VERSION 5.8 ;
BUSBITCHARS "[]" ;
DIVIDERCHAR "/" ;
UNITS
    DATABASE MICRONS 1000 ;
END UNITS

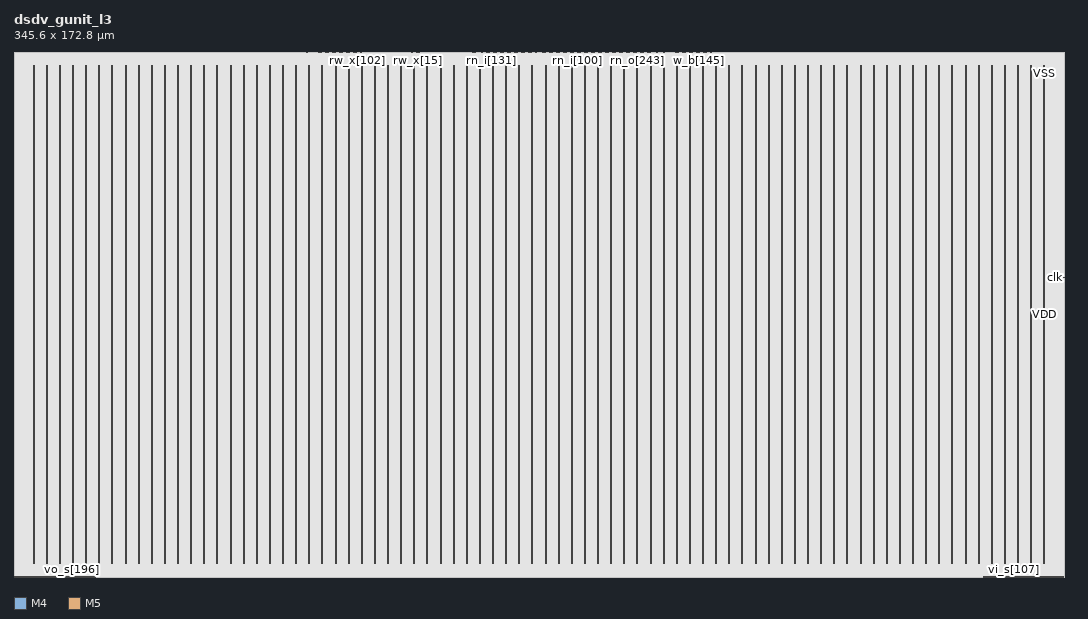
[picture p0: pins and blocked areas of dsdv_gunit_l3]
MACRO dsdv_gunit_l3
  FOREIGN dsdv_gunit_l3 0 0 ;
  CLASS BLOCK ;
  SIZE 345.6 BY 172.8 ;
  PIN clk
    DIRECTION INPUT ;
    USE SIGNAL ;
    PORT
      LAYER M4 ;
        RECT  345.516 98.448 345.6 98.472 ;
    END
  END clk
  PIN fault
    DIRECTION OUTPUT ;
    USE SIGNAL ;
    PORT
      LAYER M5 ;
        RECT  175.92 172.716 175.944 172.8 ;
    END
  END fault
  PIN rn_i[0]
    DIRECTION INPUT ;
    USE SIGNAL ;
    PORT
      LAYER M5 ;
        RECT  176.016 172.716 176.04 172.8 ;
    END
  END rn_i[0]
  PIN rn_i[100]
    DIRECTION INPUT ;
    USE SIGNAL ;
    PORT
      LAYER M5 ;
        RECT  185.616 172.716 185.64 172.8 ;
    END
  END rn_i[100]
  PIN rn_i[101]
    DIRECTION INPUT ;
    USE SIGNAL ;
    PORT
      LAYER M5 ;
        RECT  185.712 172.716 185.736 172.8 ;
    END
  END rn_i[101]
  PIN rn_i[102]
    DIRECTION INPUT ;
    USE SIGNAL ;
    PORT
      LAYER M5 ;
        RECT  185.808 172.716 185.832 172.8 ;
    END
  END rn_i[102]
  PIN rn_i[103]
    DIRECTION INPUT ;
    USE SIGNAL ;
    PORT
      LAYER M5 ;
        RECT  185.904 172.716 185.928 172.8 ;
    END
  END rn_i[103]
  PIN rn_i[104]
    DIRECTION INPUT ;
    USE SIGNAL ;
    PORT
      LAYER M5 ;
        RECT  186 172.716 186.024 172.8 ;
    END
  END rn_i[104]
  PIN rn_i[105]
    DIRECTION INPUT ;
    USE SIGNAL ;
    PORT
      LAYER M5 ;
        RECT  186.096 172.716 186.12 172.8 ;
    END
  END rn_i[105]
  PIN rn_i[106]
    DIRECTION INPUT ;
    USE SIGNAL ;
    PORT
      LAYER M5 ;
        RECT  186.192 172.716 186.216 172.8 ;
    END
  END rn_i[106]
  PIN rn_i[107]
    DIRECTION INPUT ;
    USE SIGNAL ;
    PORT
      LAYER M5 ;
        RECT  186.288 172.716 186.312 172.8 ;
    END
  END rn_i[107]
  PIN rn_i[108]
    DIRECTION INPUT ;
    USE SIGNAL ;
    PORT
      LAYER M5 ;
        RECT  186.384 172.716 186.408 172.8 ;
    END
  END rn_i[108]
  PIN rn_i[109]
    DIRECTION INPUT ;
    USE SIGNAL ;
    PORT
      LAYER M5 ;
        RECT  186.48 172.716 186.504 172.8 ;
    END
  END rn_i[109]
  PIN rn_i[10]
    DIRECTION INPUT ;
    USE SIGNAL ;
    PORT
      LAYER M5 ;
        RECT  176.976 172.716 177 172.8 ;
    END
  END rn_i[10]
  PIN rn_i[110]
    DIRECTION INPUT ;
    USE SIGNAL ;
    PORT
      LAYER M5 ;
        RECT  186.576 172.716 186.6 172.8 ;
    END
  END rn_i[110]
  PIN rn_i[111]
    DIRECTION INPUT ;
    USE SIGNAL ;
    PORT
      LAYER M5 ;
        RECT  186.672 172.716 186.696 172.8 ;
    END
  END rn_i[111]
  PIN rn_i[112]
    DIRECTION INPUT ;
    USE SIGNAL ;
    PORT
      LAYER M5 ;
        RECT  186.768 172.716 186.792 172.8 ;
    END
  END rn_i[112]
  PIN rn_i[113]
    DIRECTION INPUT ;
    USE SIGNAL ;
    PORT
      LAYER M5 ;
        RECT  186.864 172.716 186.888 172.8 ;
    END
  END rn_i[113]
  PIN rn_i[114]
    DIRECTION INPUT ;
    USE SIGNAL ;
    PORT
      LAYER M5 ;
        RECT  186.96 172.716 186.984 172.8 ;
    END
  END rn_i[114]
  PIN rn_i[115]
    DIRECTION INPUT ;
    USE SIGNAL ;
    PORT
      LAYER M5 ;
        RECT  187.056 172.716 187.08 172.8 ;
    END
  END rn_i[115]
  PIN rn_i[116]
    DIRECTION INPUT ;
    USE SIGNAL ;
    PORT
      LAYER M5 ;
        RECT  187.152 172.716 187.176 172.8 ;
    END
  END rn_i[116]
  PIN rn_i[117]
    DIRECTION INPUT ;
    USE SIGNAL ;
    PORT
      LAYER M5 ;
        RECT  187.248 172.716 187.272 172.8 ;
    END
  END rn_i[117]
  PIN rn_i[118]
    DIRECTION INPUT ;
    USE SIGNAL ;
    PORT
      LAYER M5 ;
        RECT  187.344 172.716 187.368 172.8 ;
    END
  END rn_i[118]
  PIN rn_i[119]
    DIRECTION INPUT ;
    USE SIGNAL ;
    PORT
      LAYER M5 ;
        RECT  187.44 172.716 187.464 172.8 ;
    END
  END rn_i[119]
  PIN rn_i[11]
    DIRECTION INPUT ;
    USE SIGNAL ;
    PORT
      LAYER M5 ;
        RECT  177.072 172.716 177.096 172.8 ;
    END
  END rn_i[11]
  PIN rn_i[120]
    DIRECTION INPUT ;
    USE SIGNAL ;
    PORT
      LAYER M5 ;
        RECT  187.536 172.716 187.56 172.8 ;
    END
  END rn_i[120]
  PIN rn_i[121]
    DIRECTION INPUT ;
    USE SIGNAL ;
    PORT
      LAYER M5 ;
        RECT  187.632 172.716 187.656 172.8 ;
    END
  END rn_i[121]
  PIN rn_i[122]
    DIRECTION INPUT ;
    USE SIGNAL ;
    PORT
      LAYER M5 ;
        RECT  187.728 172.716 187.752 172.8 ;
    END
  END rn_i[122]
  PIN rn_i[123]
    DIRECTION INPUT ;
    USE SIGNAL ;
    PORT
      LAYER M5 ;
        RECT  187.824 172.716 187.848 172.8 ;
    END
  END rn_i[123]
  PIN rn_i[124]
    DIRECTION INPUT ;
    USE SIGNAL ;
    PORT
      LAYER M5 ;
        RECT  187.92 172.716 187.944 172.8 ;
    END
  END rn_i[124]
  PIN rn_i[125]
    DIRECTION INPUT ;
    USE SIGNAL ;
    PORT
      LAYER M5 ;
        RECT  188.016 172.716 188.04 172.8 ;
    END
  END rn_i[125]
  PIN rn_i[126]
    DIRECTION INPUT ;
    USE SIGNAL ;
    PORT
      LAYER M5 ;
        RECT  188.112 172.716 188.136 172.8 ;
    END
  END rn_i[126]
  PIN rn_i[127]
    DIRECTION INPUT ;
    USE SIGNAL ;
    PORT
      LAYER M5 ;
        RECT  156.72 172.716 156.744 172.8 ;
    END
  END rn_i[127]
  PIN rn_i[128]
    DIRECTION INPUT ;
    USE SIGNAL ;
    PORT
      LAYER M5 ;
        RECT  156.816 172.716 156.84 172.8 ;
    END
  END rn_i[128]
  PIN rn_i[129]
    DIRECTION INPUT ;
    USE SIGNAL ;
    PORT
      LAYER M5 ;
        RECT  156.912 172.716 156.936 172.8 ;
    END
  END rn_i[129]
  PIN rn_i[12]
    DIRECTION INPUT ;
    USE SIGNAL ;
    PORT
      LAYER M5 ;
        RECT  177.168 172.716 177.192 172.8 ;
    END
  END rn_i[12]
  PIN rn_i[130]
    DIRECTION INPUT ;
    USE SIGNAL ;
    PORT
      LAYER M5 ;
        RECT  157.008 172.716 157.032 172.8 ;
    END
  END rn_i[130]
  PIN rn_i[131]
    DIRECTION INPUT ;
    USE SIGNAL ;
    PORT
      LAYER M5 ;
        RECT  157.104 172.716 157.128 172.8 ;
    END
  END rn_i[131]
  PIN rn_i[132]
    DIRECTION INPUT ;
    USE SIGNAL ;
    PORT
      LAYER M5 ;
        RECT  157.2 172.716 157.224 172.8 ;
    END
  END rn_i[132]
  PIN rn_i[133]
    DIRECTION INPUT ;
    USE SIGNAL ;
    PORT
      LAYER M5 ;
        RECT  157.296 172.716 157.32 172.8 ;
    END
  END rn_i[133]
  PIN rn_i[134]
    DIRECTION INPUT ;
    USE SIGNAL ;
    PORT
      LAYER M5 ;
        RECT  157.392 172.716 157.416 172.8 ;
    END
  END rn_i[134]
  PIN rn_i[135]
    DIRECTION INPUT ;
    USE SIGNAL ;
    PORT
      LAYER M5 ;
        RECT  157.488 172.716 157.512 172.8 ;
    END
  END rn_i[135]
  PIN rn_i[136]
    DIRECTION INPUT ;
    USE SIGNAL ;
    PORT
      LAYER M5 ;
        RECT  157.584 172.716 157.608 172.8 ;
    END
  END rn_i[136]
  PIN rn_i[137]
    DIRECTION INPUT ;
    USE SIGNAL ;
    PORT
      LAYER M5 ;
        RECT  157.68 172.716 157.704 172.8 ;
    END
  END rn_i[137]
  PIN rn_i[138]
    DIRECTION INPUT ;
    USE SIGNAL ;
    PORT
      LAYER M5 ;
        RECT  157.776 172.716 157.8 172.8 ;
    END
  END rn_i[138]
  PIN rn_i[139]
    DIRECTION INPUT ;
    USE SIGNAL ;
    PORT
      LAYER M5 ;
        RECT  157.872 172.716 157.896 172.8 ;
    END
  END rn_i[139]
  PIN rn_i[13]
    DIRECTION INPUT ;
    USE SIGNAL ;
    PORT
      LAYER M5 ;
        RECT  177.264 172.716 177.288 172.8 ;
    END
  END rn_i[13]
  PIN rn_i[140]
    DIRECTION INPUT ;
    USE SIGNAL ;
    PORT
      LAYER M5 ;
        RECT  157.968 172.716 157.992 172.8 ;
    END
  END rn_i[140]
  PIN rn_i[141]
    DIRECTION INPUT ;
    USE SIGNAL ;
    PORT
      LAYER M5 ;
        RECT  158.064 172.716 158.088 172.8 ;
    END
  END rn_i[141]
  PIN rn_i[142]
    DIRECTION INPUT ;
    USE SIGNAL ;
    PORT
      LAYER M5 ;
        RECT  158.16 172.716 158.184 172.8 ;
    END
  END rn_i[142]
  PIN rn_i[143]
    DIRECTION INPUT ;
    USE SIGNAL ;
    PORT
      LAYER M5 ;
        RECT  158.256 172.716 158.28 172.8 ;
    END
  END rn_i[143]
  PIN rn_i[144]
    DIRECTION INPUT ;
    USE SIGNAL ;
    PORT
      LAYER M5 ;
        RECT  158.352 172.716 158.376 172.8 ;
    END
  END rn_i[144]
  PIN rn_i[145]
    DIRECTION INPUT ;
    USE SIGNAL ;
    PORT
      LAYER M5 ;
        RECT  158.448 172.716 158.472 172.8 ;
    END
  END rn_i[145]
  PIN rn_i[146]
    DIRECTION INPUT ;
    USE SIGNAL ;
    PORT
      LAYER M5 ;
        RECT  158.544 172.716 158.568 172.8 ;
    END
  END rn_i[146]
  PIN rn_i[147]
    DIRECTION INPUT ;
    USE SIGNAL ;
    PORT
      LAYER M5 ;
        RECT  158.64 172.716 158.664 172.8 ;
    END
  END rn_i[147]
  PIN rn_i[148]
    DIRECTION INPUT ;
    USE SIGNAL ;
    PORT
      LAYER M5 ;
        RECT  158.736 172.716 158.76 172.8 ;
    END
  END rn_i[148]
  PIN rn_i[149]
    DIRECTION INPUT ;
    USE SIGNAL ;
    PORT
      LAYER M5 ;
        RECT  158.832 172.716 158.856 172.8 ;
    END
  END rn_i[149]
  PIN rn_i[14]
    DIRECTION INPUT ;
    USE SIGNAL ;
    PORT
      LAYER M5 ;
        RECT  177.36 172.716 177.384 172.8 ;
    END
  END rn_i[14]
  PIN rn_i[150]
    DIRECTION INPUT ;
    USE SIGNAL ;
    PORT
      LAYER M5 ;
        RECT  158.928 172.716 158.952 172.8 ;
    END
  END rn_i[150]
  PIN rn_i[151]
    DIRECTION INPUT ;
    USE SIGNAL ;
    PORT
      LAYER M5 ;
        RECT  159.024 172.716 159.048 172.8 ;
    END
  END rn_i[151]
  PIN rn_i[152]
    DIRECTION INPUT ;
    USE SIGNAL ;
    PORT
      LAYER M5 ;
        RECT  159.12 172.716 159.144 172.8 ;
    END
  END rn_i[152]
  PIN rn_i[153]
    DIRECTION INPUT ;
    USE SIGNAL ;
    PORT
      LAYER M5 ;
        RECT  159.216 172.716 159.24 172.8 ;
    END
  END rn_i[153]
  PIN rn_i[154]
    DIRECTION INPUT ;
    USE SIGNAL ;
    PORT
      LAYER M5 ;
        RECT  159.312 172.716 159.336 172.8 ;
    END
  END rn_i[154]
  PIN rn_i[155]
    DIRECTION INPUT ;
    USE SIGNAL ;
    PORT
      LAYER M5 ;
        RECT  159.408 172.716 159.432 172.8 ;
    END
  END rn_i[155]
  PIN rn_i[156]
    DIRECTION INPUT ;
    USE SIGNAL ;
    PORT
      LAYER M5 ;
        RECT  159.504 172.716 159.528 172.8 ;
    END
  END rn_i[156]
  PIN rn_i[157]
    DIRECTION INPUT ;
    USE SIGNAL ;
    PORT
      LAYER M5 ;
        RECT  159.6 172.716 159.624 172.8 ;
    END
  END rn_i[157]
  PIN rn_i[158]
    DIRECTION INPUT ;
    USE SIGNAL ;
    PORT
      LAYER M5 ;
        RECT  159.696 172.716 159.72 172.8 ;
    END
  END rn_i[158]
  PIN rn_i[159]
    DIRECTION INPUT ;
    USE SIGNAL ;
    PORT
      LAYER M5 ;
        RECT  188.208 172.716 188.232 172.8 ;
    END
  END rn_i[159]
  PIN rn_i[15]
    DIRECTION INPUT ;
    USE SIGNAL ;
    PORT
      LAYER M5 ;
        RECT  177.456 172.716 177.48 172.8 ;
    END
  END rn_i[15]
  PIN rn_i[160]
    DIRECTION INPUT ;
    USE SIGNAL ;
    PORT
      LAYER M5 ;
        RECT  188.304 172.716 188.328 172.8 ;
    END
  END rn_i[160]
  PIN rn_i[161]
    DIRECTION INPUT ;
    USE SIGNAL ;
    PORT
      LAYER M5 ;
        RECT  188.4 172.716 188.424 172.8 ;
    END
  END rn_i[161]
  PIN rn_i[162]
    DIRECTION INPUT ;
    USE SIGNAL ;
    PORT
      LAYER M5 ;
        RECT  188.496 172.716 188.52 172.8 ;
    END
  END rn_i[162]
  PIN rn_i[163]
    DIRECTION INPUT ;
    USE SIGNAL ;
    PORT
      LAYER M5 ;
        RECT  188.592 172.716 188.616 172.8 ;
    END
  END rn_i[163]
  PIN rn_i[164]
    DIRECTION INPUT ;
    USE SIGNAL ;
    PORT
      LAYER M5 ;
        RECT  188.688 172.716 188.712 172.8 ;
    END
  END rn_i[164]
  PIN rn_i[165]
    DIRECTION INPUT ;
    USE SIGNAL ;
    PORT
      LAYER M5 ;
        RECT  188.784 172.716 188.808 172.8 ;
    END
  END rn_i[165]
  PIN rn_i[166]
    DIRECTION INPUT ;
    USE SIGNAL ;
    PORT
      LAYER M5 ;
        RECT  188.88 172.716 188.904 172.8 ;
    END
  END rn_i[166]
  PIN rn_i[167]
    DIRECTION INPUT ;
    USE SIGNAL ;
    PORT
      LAYER M5 ;
        RECT  188.976 172.716 189 172.8 ;
    END
  END rn_i[167]
  PIN rn_i[168]
    DIRECTION INPUT ;
    USE SIGNAL ;
    PORT
      LAYER M5 ;
        RECT  189.072 172.716 189.096 172.8 ;
    END
  END rn_i[168]
  PIN rn_i[169]
    DIRECTION INPUT ;
    USE SIGNAL ;
    PORT
      LAYER M5 ;
        RECT  189.168 172.716 189.192 172.8 ;
    END
  END rn_i[169]
  PIN rn_i[16]
    DIRECTION INPUT ;
    USE SIGNAL ;
    PORT
      LAYER M5 ;
        RECT  177.552 172.716 177.576 172.8 ;
    END
  END rn_i[16]
  PIN rn_i[170]
    DIRECTION INPUT ;
    USE SIGNAL ;
    PORT
      LAYER M5 ;
        RECT  189.264 172.716 189.288 172.8 ;
    END
  END rn_i[170]
  PIN rn_i[171]
    DIRECTION INPUT ;
    USE SIGNAL ;
    PORT
      LAYER M5 ;
        RECT  189.36 172.716 189.384 172.8 ;
    END
  END rn_i[171]
  PIN rn_i[172]
    DIRECTION INPUT ;
    USE SIGNAL ;
    PORT
      LAYER M5 ;
        RECT  189.456 172.716 189.48 172.8 ;
    END
  END rn_i[172]
  PIN rn_i[173]
    DIRECTION INPUT ;
    USE SIGNAL ;
    PORT
      LAYER M5 ;
        RECT  189.552 172.716 189.576 172.8 ;
    END
  END rn_i[173]
  PIN rn_i[174]
    DIRECTION INPUT ;
    USE SIGNAL ;
    PORT
      LAYER M5 ;
        RECT  189.648 172.716 189.672 172.8 ;
    END
  END rn_i[174]
  PIN rn_i[175]
    DIRECTION INPUT ;
    USE SIGNAL ;
    PORT
      LAYER M5 ;
        RECT  189.744 172.716 189.768 172.8 ;
    END
  END rn_i[175]
  PIN rn_i[176]
    DIRECTION INPUT ;
    USE SIGNAL ;
    PORT
      LAYER M5 ;
        RECT  189.84 172.716 189.864 172.8 ;
    END
  END rn_i[176]
  PIN rn_i[177]
    DIRECTION INPUT ;
    USE SIGNAL ;
    PORT
      LAYER M5 ;
        RECT  189.936 172.716 189.96 172.8 ;
    END
  END rn_i[177]
  PIN rn_i[178]
    DIRECTION INPUT ;
    USE SIGNAL ;
    PORT
      LAYER M5 ;
        RECT  190.032 172.716 190.056 172.8 ;
    END
  END rn_i[178]
  PIN rn_i[179]
    DIRECTION INPUT ;
    USE SIGNAL ;
    PORT
      LAYER M5 ;
        RECT  190.128 172.716 190.152 172.8 ;
    END
  END rn_i[179]
  PIN rn_i[17]
    DIRECTION INPUT ;
    USE SIGNAL ;
    PORT
      LAYER M5 ;
        RECT  177.648 172.716 177.672 172.8 ;
    END
  END rn_i[17]
  PIN rn_i[180]
    DIRECTION INPUT ;
    USE SIGNAL ;
    PORT
      LAYER M5 ;
        RECT  190.224 172.716 190.248 172.8 ;
    END
  END rn_i[180]
  PIN rn_i[181]
    DIRECTION INPUT ;
    USE SIGNAL ;
    PORT
      LAYER M5 ;
        RECT  190.32 172.716 190.344 172.8 ;
    END
  END rn_i[181]
  PIN rn_i[182]
    DIRECTION INPUT ;
    USE SIGNAL ;
    PORT
      LAYER M5 ;
        RECT  190.416 172.716 190.44 172.8 ;
    END
  END rn_i[182]
  PIN rn_i[183]
    DIRECTION INPUT ;
    USE SIGNAL ;
    PORT
      LAYER M5 ;
        RECT  190.512 172.716 190.536 172.8 ;
    END
  END rn_i[183]
  PIN rn_i[184]
    DIRECTION INPUT ;
    USE SIGNAL ;
    PORT
      LAYER M5 ;
        RECT  190.608 172.716 190.632 172.8 ;
    END
  END rn_i[184]
  PIN rn_i[185]
    DIRECTION INPUT ;
    USE SIGNAL ;
    PORT
      LAYER M5 ;
        RECT  190.704 172.716 190.728 172.8 ;
    END
  END rn_i[185]
  PIN rn_i[186]
    DIRECTION INPUT ;
    USE SIGNAL ;
    PORT
      LAYER M5 ;
        RECT  190.8 172.716 190.824 172.8 ;
    END
  END rn_i[186]
  PIN rn_i[187]
    DIRECTION INPUT ;
    USE SIGNAL ;
    PORT
      LAYER M5 ;
        RECT  190.896 172.716 190.92 172.8 ;
    END
  END rn_i[187]
  PIN rn_i[188]
    DIRECTION INPUT ;
    USE SIGNAL ;
    PORT
      LAYER M5 ;
        RECT  190.992 172.716 191.016 172.8 ;
    END
  END rn_i[188]
  PIN rn_i[189]
    DIRECTION INPUT ;
    USE SIGNAL ;
    PORT
      LAYER M5 ;
        RECT  191.088 172.716 191.112 172.8 ;
    END
  END rn_i[189]
  PIN rn_i[18]
    DIRECTION INPUT ;
    USE SIGNAL ;
    PORT
      LAYER M5 ;
        RECT  177.744 172.716 177.768 172.8 ;
    END
  END rn_i[18]
  PIN rn_i[190]
    DIRECTION INPUT ;
    USE SIGNAL ;
    PORT
      LAYER M5 ;
        RECT  191.184 172.716 191.208 172.8 ;
    END
  END rn_i[190]
  PIN rn_i[191]
    DIRECTION INPUT ;
    USE SIGNAL ;
    PORT
      LAYER M5 ;
        RECT  178.992 172.716 179.016 172.8 ;
    END
  END rn_i[191]
  PIN rn_i[192]
    DIRECTION INPUT ;
    USE SIGNAL ;
    PORT
      LAYER M5 ;
        RECT  179.088 172.716 179.112 172.8 ;
    END
  END rn_i[192]
  PIN rn_i[193]
    DIRECTION INPUT ;
    USE SIGNAL ;
    PORT
      LAYER M5 ;
        RECT  179.184 172.716 179.208 172.8 ;
    END
  END rn_i[193]
  PIN rn_i[194]
    DIRECTION INPUT ;
    USE SIGNAL ;
    PORT
      LAYER M5 ;
        RECT  179.28 172.716 179.304 172.8 ;
    END
  END rn_i[194]
  PIN rn_i[195]
    DIRECTION INPUT ;
    USE SIGNAL ;
    PORT
      LAYER M5 ;
        RECT  179.376 172.716 179.4 172.8 ;
    END
  END rn_i[195]
  PIN rn_i[196]
    DIRECTION INPUT ;
    USE SIGNAL ;
    PORT
      LAYER M5 ;
        RECT  179.472 172.716 179.496 172.8 ;
    END
  END rn_i[196]
  PIN rn_i[197]
    DIRECTION INPUT ;
    USE SIGNAL ;
    PORT
      LAYER M5 ;
        RECT  179.568 172.716 179.592 172.8 ;
    END
  END rn_i[197]
  PIN rn_i[198]
    DIRECTION INPUT ;
    USE SIGNAL ;
    PORT
      LAYER M5 ;
        RECT  179.664 172.716 179.688 172.8 ;
    END
  END rn_i[198]
  PIN rn_i[199]
    DIRECTION INPUT ;
    USE SIGNAL ;
    PORT
      LAYER M5 ;
        RECT  179.76 172.716 179.784 172.8 ;
    END
  END rn_i[199]
  PIN rn_i[19]
    DIRECTION INPUT ;
    USE SIGNAL ;
    PORT
      LAYER M5 ;
        RECT  177.84 172.716 177.864 172.8 ;
    END
  END rn_i[19]
  PIN rn_i[1]
    DIRECTION INPUT ;
    USE SIGNAL ;
    PORT
      LAYER M5 ;
        RECT  176.112 172.716 176.136 172.8 ;
    END
  END rn_i[1]
  PIN rn_i[200]
    DIRECTION INPUT ;
    USE SIGNAL ;
    PORT
      LAYER M5 ;
        RECT  179.856 172.716 179.88 172.8 ;
    END
  END rn_i[200]
  PIN rn_i[201]
    DIRECTION INPUT ;
    USE SIGNAL ;
    PORT
      LAYER M5 ;
        RECT  179.952 172.716 179.976 172.8 ;
    END
  END rn_i[201]
  PIN rn_i[202]
    DIRECTION INPUT ;
    USE SIGNAL ;
    PORT
      LAYER M5 ;
        RECT  180.048 172.716 180.072 172.8 ;
    END
  END rn_i[202]
  PIN rn_i[203]
    DIRECTION INPUT ;
    USE SIGNAL ;
    PORT
      LAYER M5 ;
        RECT  180.144 172.716 180.168 172.8 ;
    END
  END rn_i[203]
  PIN rn_i[204]
    DIRECTION INPUT ;
    USE SIGNAL ;
    PORT
      LAYER M5 ;
        RECT  180.24 172.716 180.264 172.8 ;
    END
  END rn_i[204]
  PIN rn_i[205]
    DIRECTION INPUT ;
    USE SIGNAL ;
    PORT
      LAYER M5 ;
        RECT  180.336 172.716 180.36 172.8 ;
    END
  END rn_i[205]
  PIN rn_i[206]
    DIRECTION INPUT ;
    USE SIGNAL ;
    PORT
      LAYER M5 ;
        RECT  180.432 172.716 180.456 172.8 ;
    END
  END rn_i[206]
  PIN rn_i[207]
    DIRECTION INPUT ;
    USE SIGNAL ;
    PORT
      LAYER M5 ;
        RECT  180.528 172.716 180.552 172.8 ;
    END
  END rn_i[207]
  PIN rn_i[208]
    DIRECTION INPUT ;
    USE SIGNAL ;
    PORT
      LAYER M5 ;
        RECT  180.624 172.716 180.648 172.8 ;
    END
  END rn_i[208]
  PIN rn_i[209]
    DIRECTION INPUT ;
    USE SIGNAL ;
    PORT
      LAYER M5 ;
        RECT  180.72 172.716 180.744 172.8 ;
    END
  END rn_i[209]
  PIN rn_i[20]
    DIRECTION INPUT ;
    USE SIGNAL ;
    PORT
      LAYER M5 ;
        RECT  177.936 172.716 177.96 172.8 ;
    END
  END rn_i[20]
  PIN rn_i[210]
    DIRECTION INPUT ;
    USE SIGNAL ;
    PORT
      LAYER M5 ;
        RECT  180.816 172.716 180.84 172.8 ;
    END
  END rn_i[210]
  PIN rn_i[211]
    DIRECTION INPUT ;
    USE SIGNAL ;
    PORT
      LAYER M5 ;
        RECT  180.912 172.716 180.936 172.8 ;
    END
  END rn_i[211]
  PIN rn_i[212]
    DIRECTION INPUT ;
    USE SIGNAL ;
    PORT
      LAYER M5 ;
        RECT  181.008 172.716 181.032 172.8 ;
    END
  END rn_i[212]
  PIN rn_i[213]
    DIRECTION INPUT ;
    USE SIGNAL ;
    PORT
      LAYER M5 ;
        RECT  181.104 172.716 181.128 172.8 ;
    END
  END rn_i[213]
  PIN rn_i[214]
    DIRECTION INPUT ;
    USE SIGNAL ;
    PORT
      LAYER M5 ;
        RECT  181.2 172.716 181.224 172.8 ;
    END
  END rn_i[214]
  PIN rn_i[215]
    DIRECTION INPUT ;
    USE SIGNAL ;
    PORT
      LAYER M5 ;
        RECT  181.296 172.716 181.32 172.8 ;
    END
  END rn_i[215]
  PIN rn_i[216]
    DIRECTION INPUT ;
    USE SIGNAL ;
    PORT
      LAYER M5 ;
        RECT  181.392 172.716 181.416 172.8 ;
    END
  END rn_i[216]
  PIN rn_i[217]
    DIRECTION INPUT ;
    USE SIGNAL ;
    PORT
      LAYER M5 ;
        RECT  181.488 172.716 181.512 172.8 ;
    END
  END rn_i[217]
  PIN rn_i[218]
    DIRECTION INPUT ;
    USE SIGNAL ;
    PORT
      LAYER M5 ;
        RECT  181.584 172.716 181.608 172.8 ;
    END
  END rn_i[218]
  PIN rn_i[219]
    DIRECTION INPUT ;
    USE SIGNAL ;
    PORT
      LAYER M5 ;
        RECT  181.68 172.716 181.704 172.8 ;
    END
  END rn_i[219]
  PIN rn_i[21]
    DIRECTION INPUT ;
    USE SIGNAL ;
    PORT
      LAYER M5 ;
        RECT  178.032 172.716 178.056 172.8 ;
    END
  END rn_i[21]
  PIN rn_i[220]
    DIRECTION INPUT ;
    USE SIGNAL ;
    PORT
      LAYER M5 ;
        RECT  181.776 172.716 181.8 172.8 ;
    END
  END rn_i[220]
  PIN rn_i[221]
    DIRECTION INPUT ;
    USE SIGNAL ;
    PORT
      LAYER M5 ;
        RECT  181.872 172.716 181.896 172.8 ;
    END
  END rn_i[221]
  PIN rn_i[222]
    DIRECTION INPUT ;
    USE SIGNAL ;
    PORT
      LAYER M5 ;
        RECT  181.968 172.716 181.992 172.8 ;
    END
  END rn_i[222]
  PIN rn_i[223]
    DIRECTION INPUT ;
    USE SIGNAL ;
    PORT
      LAYER M5 ;
        RECT  201.264 172.716 201.288 172.8 ;
    END
  END rn_i[223]
  PIN rn_i[224]
    DIRECTION INPUT ;
    USE SIGNAL ;
    PORT
      LAYER M5 ;
        RECT  201.36 172.716 201.384 172.8 ;
    END
  END rn_i[224]
  PIN rn_i[225]
    DIRECTION INPUT ;
    USE SIGNAL ;
    PORT
      LAYER M5 ;
        RECT  201.456 172.716 201.48 172.8 ;
    END
  END rn_i[225]
  PIN rn_i[226]
    DIRECTION INPUT ;
    USE SIGNAL ;
    PORT
      LAYER M5 ;
        RECT  201.552 172.716 201.576 172.8 ;
    END
  END rn_i[226]
  PIN rn_i[227]
    DIRECTION INPUT ;
    USE SIGNAL ;
    PORT
      LAYER M5 ;
        RECT  201.648 172.716 201.672 172.8 ;
    END
  END rn_i[227]
  PIN rn_i[228]
    DIRECTION INPUT ;
    USE SIGNAL ;
    PORT
      LAYER M5 ;
        RECT  201.744 172.716 201.768 172.8 ;
    END
  END rn_i[228]
  PIN rn_i[229]
    DIRECTION INPUT ;
    USE SIGNAL ;
    PORT
      LAYER M5 ;
        RECT  201.84 172.716 201.864 172.8 ;
    END
  END rn_i[229]
  PIN rn_i[22]
    DIRECTION INPUT ;
    USE SIGNAL ;
    PORT
      LAYER M5 ;
        RECT  178.128 172.716 178.152 172.8 ;
    END
  END rn_i[22]
  PIN rn_i[230]
    DIRECTION INPUT ;
    USE SIGNAL ;
    PORT
      LAYER M5 ;
        RECT  201.936 172.716 201.96 172.8 ;
    END
  END rn_i[230]
  PIN rn_i[231]
    DIRECTION INPUT ;
    USE SIGNAL ;
    PORT
      LAYER M5 ;
        RECT  202.032 172.716 202.056 172.8 ;
    END
  END rn_i[231]
  PIN rn_i[232]
    DIRECTION INPUT ;
    USE SIGNAL ;
    PORT
      LAYER M5 ;
        RECT  202.128 172.716 202.152 172.8 ;
    END
  END rn_i[232]
  PIN rn_i[233]
    DIRECTION INPUT ;
    USE SIGNAL ;
    PORT
      LAYER M5 ;
        RECT  202.224 172.716 202.248 172.8 ;
    END
  END rn_i[233]
  PIN rn_i[234]
    DIRECTION INPUT ;
    USE SIGNAL ;
    PORT
      LAYER M5 ;
        RECT  202.32 172.716 202.344 172.8 ;
    END
  END rn_i[234]
  PIN rn_i[235]
    DIRECTION INPUT ;
    USE SIGNAL ;
    PORT
      LAYER M5 ;
        RECT  202.416 172.716 202.44 172.8 ;
    END
  END rn_i[235]
  PIN rn_i[236]
    DIRECTION INPUT ;
    USE SIGNAL ;
    PORT
      LAYER M5 ;
        RECT  202.512 172.716 202.536 172.8 ;
    END
  END rn_i[236]
  PIN rn_i[237]
    DIRECTION INPUT ;
    USE SIGNAL ;
    PORT
      LAYER M5 ;
        RECT  202.608 172.716 202.632 172.8 ;
    END
  END rn_i[237]
  PIN rn_i[238]
    DIRECTION INPUT ;
    USE SIGNAL ;
    PORT
      LAYER M5 ;
        RECT  202.704 172.716 202.728 172.8 ;
    END
  END rn_i[238]
  PIN rn_i[239]
    DIRECTION INPUT ;
    USE SIGNAL ;
    PORT
      LAYER M5 ;
        RECT  202.8 172.716 202.824 172.8 ;
    END
  END rn_i[239]
  PIN rn_i[23]
    DIRECTION INPUT ;
    USE SIGNAL ;
    PORT
      LAYER M5 ;
        RECT  178.224 172.716 178.248 172.8 ;
    END
  END rn_i[23]
  PIN rn_i[240]
    DIRECTION INPUT ;
    USE SIGNAL ;
    PORT
      LAYER M5 ;
        RECT  202.896 172.716 202.92 172.8 ;
    END
  END rn_i[240]
  PIN rn_i[241]
    DIRECTION INPUT ;
    USE SIGNAL ;
    PORT
      LAYER M5 ;
        RECT  202.992 172.716 203.016 172.8 ;
    END
  END rn_i[241]
  PIN rn_i[242]
    DIRECTION INPUT ;
    USE SIGNAL ;
    PORT
      LAYER M5 ;
        RECT  203.088 172.716 203.112 172.8 ;
    END
  END rn_i[242]
  PIN rn_i[243]
    DIRECTION INPUT ;
    USE SIGNAL ;
    PORT
      LAYER M5 ;
        RECT  203.184 172.716 203.208 172.8 ;
    END
  END rn_i[243]
  PIN rn_i[244]
    DIRECTION INPUT ;
    USE SIGNAL ;
    PORT
      LAYER M5 ;
        RECT  203.28 172.716 203.304 172.8 ;
    END
  END rn_i[244]
  PIN rn_i[245]
    DIRECTION INPUT ;
    USE SIGNAL ;
    PORT
      LAYER M5 ;
        RECT  203.376 172.716 203.4 172.8 ;
    END
  END rn_i[245]
  PIN rn_i[246]
    DIRECTION INPUT ;
    USE SIGNAL ;
    PORT
      LAYER M5 ;
        RECT  203.472 172.716 203.496 172.8 ;
    END
  END rn_i[246]
  PIN rn_i[247]
    DIRECTION INPUT ;
    USE SIGNAL ;
    PORT
      LAYER M5 ;
        RECT  203.568 172.716 203.592 172.8 ;
    END
  END rn_i[247]
  PIN rn_i[248]
    DIRECTION INPUT ;
    USE SIGNAL ;
    PORT
      LAYER M5 ;
        RECT  203.664 172.716 203.688 172.8 ;
    END
  END rn_i[248]
  PIN rn_i[249]
    DIRECTION INPUT ;
    USE SIGNAL ;
    PORT
      LAYER M5 ;
        RECT  203.76 172.716 203.784 172.8 ;
    END
  END rn_i[249]
  PIN rn_i[24]
    DIRECTION INPUT ;
    USE SIGNAL ;
    PORT
      LAYER M5 ;
        RECT  178.32 172.716 178.344 172.8 ;
    END
  END rn_i[24]
  PIN rn_i[250]
    DIRECTION INPUT ;
    USE SIGNAL ;
    PORT
      LAYER M5 ;
        RECT  203.856 172.716 203.88 172.8 ;
    END
  END rn_i[250]
  PIN rn_i[251]
    DIRECTION INPUT ;
    USE SIGNAL ;
    PORT
      LAYER M5 ;
        RECT  203.952 172.716 203.976 172.8 ;
    END
  END rn_i[251]
  PIN rn_i[252]
    DIRECTION INPUT ;
    USE SIGNAL ;
    PORT
      LAYER M5 ;
        RECT  204.048 172.716 204.072 172.8 ;
    END
  END rn_i[252]
  PIN rn_i[253]
    DIRECTION INPUT ;
    USE SIGNAL ;
    PORT
      LAYER M5 ;
        RECT  204.144 172.716 204.168 172.8 ;
    END
  END rn_i[253]
  PIN rn_i[254]
    DIRECTION INPUT ;
    USE SIGNAL ;
    PORT
      LAYER M5 ;
        RECT  204.24 172.716 204.264 172.8 ;
    END
  END rn_i[254]
  PIN rn_i[255]
    DIRECTION INPUT ;
    USE SIGNAL ;
    PORT
      LAYER M5 ;
        RECT  165.936 172.716 165.96 172.8 ;
    END
  END rn_i[255]
  PIN rn_i[256]
    DIRECTION INPUT ;
    USE SIGNAL ;
    PORT
      LAYER M5 ;
        RECT  166.032 172.716 166.056 172.8 ;
    END
  END rn_i[256]
  PIN rn_i[257]
    DIRECTION INPUT ;
    USE SIGNAL ;
    PORT
      LAYER M5 ;
        RECT  166.128 172.716 166.152 172.8 ;
    END
  END rn_i[257]
  PIN rn_i[258]
    DIRECTION INPUT ;
    USE SIGNAL ;
    PORT
      LAYER M5 ;
        RECT  166.224 172.716 166.248 172.8 ;
    END
  END rn_i[258]
  PIN rn_i[259]
    DIRECTION INPUT ;
    USE SIGNAL ;
    PORT
      LAYER M5 ;
        RECT  166.32 172.716 166.344 172.8 ;
    END
  END rn_i[259]
  PIN rn_i[25]
    DIRECTION INPUT ;
    USE SIGNAL ;
    PORT
      LAYER M5 ;
        RECT  178.416 172.716 178.44 172.8 ;
    END
  END rn_i[25]
  PIN rn_i[260]
    DIRECTION INPUT ;
    USE SIGNAL ;
    PORT
      LAYER M5 ;
        RECT  166.416 172.716 166.44 172.8 ;
    END
  END rn_i[260]
  PIN rn_i[261]
    DIRECTION INPUT ;
    USE SIGNAL ;
    PORT
      LAYER M5 ;
        RECT  166.512 172.716 166.536 172.8 ;
    END
  END rn_i[261]
  PIN rn_i[262]
    DIRECTION INPUT ;
    USE SIGNAL ;
    PORT
      LAYER M5 ;
        RECT  166.608 172.716 166.632 172.8 ;
    END
  END rn_i[262]
  PIN rn_i[263]
    DIRECTION INPUT ;
    USE SIGNAL ;
    PORT
      LAYER M5 ;
        RECT  166.704 172.716 166.728 172.8 ;
    END
  END rn_i[263]
  PIN rn_i[264]
    DIRECTION INPUT ;
    USE SIGNAL ;
    PORT
      LAYER M5 ;
        RECT  166.8 172.716 166.824 172.8 ;
    END
  END rn_i[264]
  PIN rn_i[265]
    DIRECTION INPUT ;
    USE SIGNAL ;
    PORT
      LAYER M5 ;
        RECT  166.896 172.716 166.92 172.8 ;
    END
  END rn_i[265]
  PIN rn_i[266]
    DIRECTION INPUT ;
    USE SIGNAL ;
    PORT
      LAYER M5 ;
        RECT  166.992 172.716 167.016 172.8 ;
    END
  END rn_i[266]
  PIN rn_i[267]
    DIRECTION INPUT ;
    USE SIGNAL ;
    PORT
      LAYER M5 ;
        RECT  167.088 172.716 167.112 172.8 ;
    END
  END rn_i[267]
  PIN rn_i[268]
    DIRECTION INPUT ;
    USE SIGNAL ;
    PORT
      LAYER M5 ;
        RECT  167.184 172.716 167.208 172.8 ;
    END
  END rn_i[268]
  PIN rn_i[269]
    DIRECTION INPUT ;
    USE SIGNAL ;
    PORT
      LAYER M5 ;
        RECT  167.28 172.716 167.304 172.8 ;
    END
  END rn_i[269]
  PIN rn_i[26]
    DIRECTION INPUT ;
    USE SIGNAL ;
    PORT
      LAYER M5 ;
        RECT  178.512 172.716 178.536 172.8 ;
    END
  END rn_i[26]
  PIN rn_i[270]
    DIRECTION INPUT ;
    USE SIGNAL ;
    PORT
      LAYER M5 ;
        RECT  167.376 172.716 167.4 172.8 ;
    END
  END rn_i[270]
  PIN rn_i[271]
    DIRECTION INPUT ;
    USE SIGNAL ;
    PORT
      LAYER M5 ;
        RECT  167.472 172.716 167.496 172.8 ;
    END
  END rn_i[271]
  PIN rn_i[272]
    DIRECTION INPUT ;
    USE SIGNAL ;
    PORT
      LAYER M5 ;
        RECT  167.568 172.716 167.592 172.8 ;
    END
  END rn_i[272]
  PIN rn_i[273]
    DIRECTION INPUT ;
    USE SIGNAL ;
    PORT
      LAYER M5 ;
        RECT  167.664 172.716 167.688 172.8 ;
    END
  END rn_i[273]
  PIN rn_i[274]
    DIRECTION INPUT ;
    USE SIGNAL ;
    PORT
      LAYER M5 ;
        RECT  167.76 172.716 167.784 172.8 ;
    END
  END rn_i[274]
  PIN rn_i[275]
    DIRECTION INPUT ;
    USE SIGNAL ;
    PORT
      LAYER M5 ;
        RECT  167.856 172.716 167.88 172.8 ;
    END
  END rn_i[275]
  PIN rn_i[27]
    DIRECTION INPUT ;
    USE SIGNAL ;
    PORT
      LAYER M5 ;
        RECT  178.608 172.716 178.632 172.8 ;
    END
  END rn_i[27]
  PIN rn_i[28]
    DIRECTION INPUT ;
    USE SIGNAL ;
    PORT
      LAYER M5 ;
        RECT  178.704 172.716 178.728 172.8 ;
    END
  END rn_i[28]
  PIN rn_i[29]
    DIRECTION INPUT ;
    USE SIGNAL ;
    PORT
      LAYER M5 ;
        RECT  178.8 172.716 178.824 172.8 ;
    END
  END rn_i[29]
  PIN rn_i[2]
    DIRECTION INPUT ;
    USE SIGNAL ;
    PORT
      LAYER M5 ;
        RECT  176.208 172.716 176.232 172.8 ;
    END
  END rn_i[2]
  PIN rn_i[30]
    DIRECTION INPUT ;
    USE SIGNAL ;
    PORT
      LAYER M5 ;
        RECT  178.896 172.716 178.92 172.8 ;
    END
  END rn_i[30]
  PIN rn_i[31]
    DIRECTION INPUT ;
    USE SIGNAL ;
    PORT
      LAYER M5 ;
        RECT  172.848 172.716 172.872 172.8 ;
    END
  END rn_i[31]
  PIN rn_i[32]
    DIRECTION INPUT ;
    USE SIGNAL ;
    PORT
      LAYER M5 ;
        RECT  172.944 172.716 172.968 172.8 ;
    END
  END rn_i[32]
  PIN rn_i[33]
    DIRECTION INPUT ;
    USE SIGNAL ;
    PORT
      LAYER M5 ;
        RECT  173.04 172.716 173.064 172.8 ;
    END
  END rn_i[33]
  PIN rn_i[34]
    DIRECTION INPUT ;
    USE SIGNAL ;
    PORT
      LAYER M5 ;
        RECT  173.136 172.716 173.16 172.8 ;
    END
  END rn_i[34]
  PIN rn_i[35]
    DIRECTION INPUT ;
    USE SIGNAL ;
    PORT
      LAYER M5 ;
        RECT  173.232 172.716 173.256 172.8 ;
    END
  END rn_i[35]
  PIN rn_i[36]
    DIRECTION INPUT ;
    USE SIGNAL ;
    PORT
      LAYER M5 ;
        RECT  173.328 172.716 173.352 172.8 ;
    END
  END rn_i[36]
  PIN rn_i[37]
    DIRECTION INPUT ;
    USE SIGNAL ;
    PORT
      LAYER M5 ;
        RECT  173.424 172.716 173.448 172.8 ;
    END
  END rn_i[37]
  PIN rn_i[38]
    DIRECTION INPUT ;
    USE SIGNAL ;
    PORT
      LAYER M5 ;
        RECT  173.52 172.716 173.544 172.8 ;
    END
  END rn_i[38]
  PIN rn_i[39]
    DIRECTION INPUT ;
    USE SIGNAL ;
    PORT
      LAYER M5 ;
        RECT  173.616 172.716 173.64 172.8 ;
    END
  END rn_i[39]
  PIN rn_i[3]
    DIRECTION INPUT ;
    USE SIGNAL ;
    PORT
      LAYER M5 ;
        RECT  176.304 172.716 176.328 172.8 ;
    END
  END rn_i[3]
  PIN rn_i[40]
    DIRECTION INPUT ;
    USE SIGNAL ;
    PORT
      LAYER M5 ;
        RECT  173.712 172.716 173.736 172.8 ;
    END
  END rn_i[40]
  PIN rn_i[41]
    DIRECTION INPUT ;
    USE SIGNAL ;
    PORT
      LAYER M5 ;
        RECT  173.808 172.716 173.832 172.8 ;
    END
  END rn_i[41]
  PIN rn_i[42]
    DIRECTION INPUT ;
    USE SIGNAL ;
    PORT
      LAYER M5 ;
        RECT  173.904 172.716 173.928 172.8 ;
    END
  END rn_i[42]
  PIN rn_i[43]
    DIRECTION INPUT ;
    USE SIGNAL ;
    PORT
      LAYER M5 ;
        RECT  174 172.716 174.024 172.8 ;
    END
  END rn_i[43]
  PIN rn_i[44]
    DIRECTION INPUT ;
    USE SIGNAL ;
    PORT
      LAYER M5 ;
        RECT  174.096 172.716 174.12 172.8 ;
    END
  END rn_i[44]
  PIN rn_i[45]
    DIRECTION INPUT ;
    USE SIGNAL ;
    PORT
      LAYER M5 ;
        RECT  174.192 172.716 174.216 172.8 ;
    END
  END rn_i[45]
  PIN rn_i[46]
    DIRECTION INPUT ;
    USE SIGNAL ;
    PORT
      LAYER M5 ;
        RECT  174.288 172.716 174.312 172.8 ;
    END
  END rn_i[46]
  PIN rn_i[47]
    DIRECTION INPUT ;
    USE SIGNAL ;
    PORT
      LAYER M5 ;
        RECT  174.384 172.716 174.408 172.8 ;
    END
  END rn_i[47]
  PIN rn_i[48]
    DIRECTION INPUT ;
    USE SIGNAL ;
    PORT
      LAYER M5 ;
        RECT  174.48 172.716 174.504 172.8 ;
    END
  END rn_i[48]
  PIN rn_i[49]
    DIRECTION INPUT ;
    USE SIGNAL ;
    PORT
      LAYER M5 ;
        RECT  174.576 172.716 174.6 172.8 ;
    END
  END rn_i[49]
  PIN rn_i[4]
    DIRECTION INPUT ;
    USE SIGNAL ;
    PORT
      LAYER M5 ;
        RECT  176.4 172.716 176.424 172.8 ;
    END
  END rn_i[4]
  PIN rn_i[50]
    DIRECTION INPUT ;
    USE SIGNAL ;
    PORT
      LAYER M5 ;
        RECT  174.672 172.716 174.696 172.8 ;
    END
  END rn_i[50]
  PIN rn_i[51]
    DIRECTION INPUT ;
    USE SIGNAL ;
    PORT
      LAYER M5 ;
        RECT  174.768 172.716 174.792 172.8 ;
    END
  END rn_i[51]
  PIN rn_i[52]
    DIRECTION INPUT ;
    USE SIGNAL ;
    PORT
      LAYER M5 ;
        RECT  174.864 172.716 174.888 172.8 ;
    END
  END rn_i[52]
  PIN rn_i[53]
    DIRECTION INPUT ;
    USE SIGNAL ;
    PORT
      LAYER M5 ;
        RECT  174.96 172.716 174.984 172.8 ;
    END
  END rn_i[53]
  PIN rn_i[54]
    DIRECTION INPUT ;
    USE SIGNAL ;
    PORT
      LAYER M5 ;
        RECT  175.056 172.716 175.08 172.8 ;
    END
  END rn_i[54]
  PIN rn_i[55]
    DIRECTION INPUT ;
    USE SIGNAL ;
    PORT
      LAYER M5 ;
        RECT  175.152 172.716 175.176 172.8 ;
    END
  END rn_i[55]
  PIN rn_i[56]
    DIRECTION INPUT ;
    USE SIGNAL ;
    PORT
      LAYER M5 ;
        RECT  175.248 172.716 175.272 172.8 ;
    END
  END rn_i[56]
  PIN rn_i[57]
    DIRECTION INPUT ;
    USE SIGNAL ;
    PORT
      LAYER M5 ;
        RECT  175.344 172.716 175.368 172.8 ;
    END
  END rn_i[57]
  PIN rn_i[58]
    DIRECTION INPUT ;
    USE SIGNAL ;
    PORT
      LAYER M5 ;
        RECT  175.44 172.716 175.464 172.8 ;
    END
  END rn_i[58]
  PIN rn_i[59]
    DIRECTION INPUT ;
    USE SIGNAL ;
    PORT
      LAYER M5 ;
        RECT  175.536 172.716 175.56 172.8 ;
    END
  END rn_i[59]
  PIN rn_i[5]
    DIRECTION INPUT ;
    USE SIGNAL ;
    PORT
      LAYER M5 ;
        RECT  176.496 172.716 176.52 172.8 ;
    END
  END rn_i[5]
  PIN rn_i[60]
    DIRECTION INPUT ;
    USE SIGNAL ;
    PORT
      LAYER M5 ;
        RECT  175.632 172.716 175.656 172.8 ;
    END
  END rn_i[60]
  PIN rn_i[61]
    DIRECTION INPUT ;
    USE SIGNAL ;
    PORT
      LAYER M5 ;
        RECT  175.728 172.716 175.752 172.8 ;
    END
  END rn_i[61]
  PIN rn_i[62]
    DIRECTION INPUT ;
    USE SIGNAL ;
    PORT
      LAYER M5 ;
        RECT  175.824 172.716 175.848 172.8 ;
    END
  END rn_i[62]
  PIN rn_i[63]
    DIRECTION INPUT ;
    USE SIGNAL ;
    PORT
      LAYER M5 ;
        RECT  182.064 172.716 182.088 172.8 ;
    END
  END rn_i[63]
  PIN rn_i[64]
    DIRECTION INPUT ;
    USE SIGNAL ;
    PORT
      LAYER M5 ;
        RECT  182.16 172.716 182.184 172.8 ;
    END
  END rn_i[64]
  PIN rn_i[65]
    DIRECTION INPUT ;
    USE SIGNAL ;
    PORT
      LAYER M5 ;
        RECT  182.256 172.716 182.28 172.8 ;
    END
  END rn_i[65]
  PIN rn_i[66]
    DIRECTION INPUT ;
    USE SIGNAL ;
    PORT
      LAYER M5 ;
        RECT  182.352 172.716 182.376 172.8 ;
    END
  END rn_i[66]
  PIN rn_i[67]
    DIRECTION INPUT ;
    USE SIGNAL ;
    PORT
      LAYER M5 ;
        RECT  182.448 172.716 182.472 172.8 ;
    END
  END rn_i[67]
  PIN rn_i[68]
    DIRECTION INPUT ;
    USE SIGNAL ;
    PORT
      LAYER M5 ;
        RECT  182.544 172.716 182.568 172.8 ;
    END
  END rn_i[68]
  PIN rn_i[69]
    DIRECTION INPUT ;
    USE SIGNAL ;
    PORT
      LAYER M5 ;
        RECT  182.64 172.716 182.664 172.8 ;
    END
  END rn_i[69]
  PIN rn_i[6]
    DIRECTION INPUT ;
    USE SIGNAL ;
    PORT
      LAYER M5 ;
        RECT  176.592 172.716 176.616 172.8 ;
    END
  END rn_i[6]
  PIN rn_i[70]
    DIRECTION INPUT ;
    USE SIGNAL ;
    PORT
      LAYER M5 ;
        RECT  182.736 172.716 182.76 172.8 ;
    END
  END rn_i[70]
  PIN rn_i[71]
    DIRECTION INPUT ;
    USE SIGNAL ;
    PORT
      LAYER M5 ;
        RECT  182.832 172.716 182.856 172.8 ;
    END
  END rn_i[71]
  PIN rn_i[72]
    DIRECTION INPUT ;
    USE SIGNAL ;
    PORT
      LAYER M5 ;
        RECT  182.928 172.716 182.952 172.8 ;
    END
  END rn_i[72]
  PIN rn_i[73]
    DIRECTION INPUT ;
    USE SIGNAL ;
    PORT
      LAYER M5 ;
        RECT  183.024 172.716 183.048 172.8 ;
    END
  END rn_i[73]
  PIN rn_i[74]
    DIRECTION INPUT ;
    USE SIGNAL ;
    PORT
      LAYER M5 ;
        RECT  183.12 172.716 183.144 172.8 ;
    END
  END rn_i[74]
  PIN rn_i[75]
    DIRECTION INPUT ;
    USE SIGNAL ;
    PORT
      LAYER M5 ;
        RECT  183.216 172.716 183.24 172.8 ;
    END
  END rn_i[75]
  PIN rn_i[76]
    DIRECTION INPUT ;
    USE SIGNAL ;
    PORT
      LAYER M5 ;
        RECT  183.312 172.716 183.336 172.8 ;
    END
  END rn_i[76]
  PIN rn_i[77]
    DIRECTION INPUT ;
    USE SIGNAL ;
    PORT
      LAYER M5 ;
        RECT  183.408 172.716 183.432 172.8 ;
    END
  END rn_i[77]
  PIN rn_i[78]
    DIRECTION INPUT ;
    USE SIGNAL ;
    PORT
      LAYER M5 ;
        RECT  183.504 172.716 183.528 172.8 ;
    END
  END rn_i[78]
  PIN rn_i[79]
    DIRECTION INPUT ;
    USE SIGNAL ;
    PORT
      LAYER M5 ;
        RECT  183.6 172.716 183.624 172.8 ;
    END
  END rn_i[79]
  PIN rn_i[7]
    DIRECTION INPUT ;
    USE SIGNAL ;
    PORT
      LAYER M5 ;
        RECT  176.688 172.716 176.712 172.8 ;
    END
  END rn_i[7]
  PIN rn_i[80]
    DIRECTION INPUT ;
    USE SIGNAL ;
    PORT
      LAYER M5 ;
        RECT  183.696 172.716 183.72 172.8 ;
    END
  END rn_i[80]
  PIN rn_i[81]
    DIRECTION INPUT ;
    USE SIGNAL ;
    PORT
      LAYER M5 ;
        RECT  183.792 172.716 183.816 172.8 ;
    END
  END rn_i[81]
  PIN rn_i[82]
    DIRECTION INPUT ;
    USE SIGNAL ;
    PORT
      LAYER M5 ;
        RECT  183.888 172.716 183.912 172.8 ;
    END
  END rn_i[82]
  PIN rn_i[83]
    DIRECTION INPUT ;
    USE SIGNAL ;
    PORT
      LAYER M5 ;
        RECT  183.984 172.716 184.008 172.8 ;
    END
  END rn_i[83]
  PIN rn_i[84]
    DIRECTION INPUT ;
    USE SIGNAL ;
    PORT
      LAYER M5 ;
        RECT  184.08 172.716 184.104 172.8 ;
    END
  END rn_i[84]
  PIN rn_i[85]
    DIRECTION INPUT ;
    USE SIGNAL ;
    PORT
      LAYER M5 ;
        RECT  184.176 172.716 184.2 172.8 ;
    END
  END rn_i[85]
  PIN rn_i[86]
    DIRECTION INPUT ;
    USE SIGNAL ;
    PORT
      LAYER M5 ;
        RECT  184.272 172.716 184.296 172.8 ;
    END
  END rn_i[86]
  PIN rn_i[87]
    DIRECTION INPUT ;
    USE SIGNAL ;
    PORT
      LAYER M5 ;
        RECT  184.368 172.716 184.392 172.8 ;
    END
  END rn_i[87]
  PIN rn_i[88]
    DIRECTION INPUT ;
    USE SIGNAL ;
    PORT
      LAYER M5 ;
        RECT  184.464 172.716 184.488 172.8 ;
    END
  END rn_i[88]
  PIN rn_i[89]
    DIRECTION INPUT ;
    USE SIGNAL ;
    PORT
      LAYER M5 ;
        RECT  184.56 172.716 184.584 172.8 ;
    END
  END rn_i[89]
  PIN rn_i[8]
    DIRECTION INPUT ;
    USE SIGNAL ;
    PORT
      LAYER M5 ;
        RECT  176.784 172.716 176.808 172.8 ;
    END
  END rn_i[8]
  PIN rn_i[90]
    DIRECTION INPUT ;
    USE SIGNAL ;
    PORT
      LAYER M5 ;
        RECT  184.656 172.716 184.68 172.8 ;
    END
  END rn_i[90]
  PIN rn_i[91]
    DIRECTION INPUT ;
    USE SIGNAL ;
    PORT
      LAYER M5 ;
        RECT  184.752 172.716 184.776 172.8 ;
    END
  END rn_i[91]
  PIN rn_i[92]
    DIRECTION INPUT ;
    USE SIGNAL ;
    PORT
      LAYER M5 ;
        RECT  184.848 172.716 184.872 172.8 ;
    END
  END rn_i[92]
  PIN rn_i[93]
    DIRECTION INPUT ;
    USE SIGNAL ;
    PORT
      LAYER M5 ;
        RECT  184.944 172.716 184.968 172.8 ;
    END
  END rn_i[93]
  PIN rn_i[94]
    DIRECTION INPUT ;
    USE SIGNAL ;
    PORT
      LAYER M5 ;
        RECT  185.04 172.716 185.064 172.8 ;
    END
  END rn_i[94]
  PIN rn_i[95]
    DIRECTION INPUT ;
    USE SIGNAL ;
    PORT
      LAYER M5 ;
        RECT  185.136 172.716 185.16 172.8 ;
    END
  END rn_i[95]
  PIN rn_i[96]
    DIRECTION INPUT ;
    USE SIGNAL ;
    PORT
      LAYER M5 ;
        RECT  185.232 172.716 185.256 172.8 ;
    END
  END rn_i[96]
  PIN rn_i[97]
    DIRECTION INPUT ;
    USE SIGNAL ;
    PORT
      LAYER M5 ;
        RECT  185.328 172.716 185.352 172.8 ;
    END
  END rn_i[97]
  PIN rn_i[98]
    DIRECTION INPUT ;
    USE SIGNAL ;
    PORT
      LAYER M5 ;
        RECT  185.424 172.716 185.448 172.8 ;
    END
  END rn_i[98]
  PIN rn_i[99]
    DIRECTION INPUT ;
    USE SIGNAL ;
    PORT
      LAYER M5 ;
        RECT  185.52 172.716 185.544 172.8 ;
    END
  END rn_i[99]
  PIN rn_i[9]
    DIRECTION INPUT ;
    USE SIGNAL ;
    PORT
      LAYER M5 ;
        RECT  176.88 172.716 176.904 172.8 ;
    END
  END rn_i[9]
  PIN rn_o[0]
    DIRECTION OUTPUT ;
    USE SIGNAL ;
    PORT
      LAYER M5 ;
        RECT  167.952 172.716 167.976 172.8 ;
    END
  END rn_o[0]
  PIN rn_o[100]
    DIRECTION OUTPUT ;
    USE SIGNAL ;
    PORT
      LAYER M5 ;
        RECT  209.808 172.716 209.832 172.8 ;
    END
  END rn_o[100]
  PIN rn_o[101]
    DIRECTION OUTPUT ;
    USE SIGNAL ;
    PORT
      LAYER M5 ;
        RECT  209.904 172.716 209.928 172.8 ;
    END
  END rn_o[101]
  PIN rn_o[102]
    DIRECTION OUTPUT ;
    USE SIGNAL ;
    PORT
      LAYER M5 ;
        RECT  210 172.716 210.024 172.8 ;
    END
  END rn_o[102]
  PIN rn_o[103]
    DIRECTION OUTPUT ;
    USE SIGNAL ;
    PORT
      LAYER M5 ;
        RECT  210.096 172.716 210.12 172.8 ;
    END
  END rn_o[103]
  PIN rn_o[104]
    DIRECTION OUTPUT ;
    USE SIGNAL ;
    PORT
      LAYER M5 ;
        RECT  210.192 172.716 210.216 172.8 ;
    END
  END rn_o[104]
  PIN rn_o[105]
    DIRECTION OUTPUT ;
    USE SIGNAL ;
    PORT
      LAYER M5 ;
        RECT  210.288 172.716 210.312 172.8 ;
    END
  END rn_o[105]
  PIN rn_o[106]
    DIRECTION OUTPUT ;
    USE SIGNAL ;
    PORT
      LAYER M5 ;
        RECT  210.384 172.716 210.408 172.8 ;
    END
  END rn_o[106]
  PIN rn_o[107]
    DIRECTION OUTPUT ;
    USE SIGNAL ;
    PORT
      LAYER M5 ;
        RECT  153.648 172.716 153.672 172.8 ;
    END
  END rn_o[107]
  PIN rn_o[108]
    DIRECTION OUTPUT ;
    USE SIGNAL ;
    PORT
      LAYER M5 ;
        RECT  153.744 172.716 153.768 172.8 ;
    END
  END rn_o[108]
  PIN rn_o[109]
    DIRECTION OUTPUT ;
    USE SIGNAL ;
    PORT
      LAYER M5 ;
        RECT  153.84 172.716 153.864 172.8 ;
    END
  END rn_o[109]
  PIN rn_o[10]
    DIRECTION OUTPUT ;
    USE SIGNAL ;
    PORT
      LAYER M5 ;
        RECT  168.912 172.716 168.936 172.8 ;
    END
  END rn_o[10]
  PIN rn_o[110]
    DIRECTION OUTPUT ;
    USE SIGNAL ;
    PORT
      LAYER M5 ;
        RECT  153.936 172.716 153.96 172.8 ;
    END
  END rn_o[110]
  PIN rn_o[111]
    DIRECTION OUTPUT ;
    USE SIGNAL ;
    PORT
      LAYER M5 ;
        RECT  154.032 172.716 154.056 172.8 ;
    END
  END rn_o[111]
  PIN rn_o[112]
    DIRECTION OUTPUT ;
    USE SIGNAL ;
    PORT
      LAYER M5 ;
        RECT  154.128 172.716 154.152 172.8 ;
    END
  END rn_o[112]
  PIN rn_o[113]
    DIRECTION OUTPUT ;
    USE SIGNAL ;
    PORT
      LAYER M5 ;
        RECT  154.224 172.716 154.248 172.8 ;
    END
  END rn_o[113]
  PIN rn_o[114]
    DIRECTION OUTPUT ;
    USE SIGNAL ;
    PORT
      LAYER M5 ;
        RECT  154.32 172.716 154.344 172.8 ;
    END
  END rn_o[114]
  PIN rn_o[115]
    DIRECTION OUTPUT ;
    USE SIGNAL ;
    PORT
      LAYER M5 ;
        RECT  154.416 172.716 154.44 172.8 ;
    END
  END rn_o[115]
  PIN rn_o[116]
    DIRECTION OUTPUT ;
    USE SIGNAL ;
    PORT
      LAYER M5 ;
        RECT  154.512 172.716 154.536 172.8 ;
    END
  END rn_o[116]
  PIN rn_o[117]
    DIRECTION OUTPUT ;
    USE SIGNAL ;
    PORT
      LAYER M5 ;
        RECT  154.608 172.716 154.632 172.8 ;
    END
  END rn_o[117]
  PIN rn_o[118]
    DIRECTION OUTPUT ;
    USE SIGNAL ;
    PORT
      LAYER M5 ;
        RECT  154.704 172.716 154.728 172.8 ;
    END
  END rn_o[118]
  PIN rn_o[119]
    DIRECTION OUTPUT ;
    USE SIGNAL ;
    PORT
      LAYER M5 ;
        RECT  154.8 172.716 154.824 172.8 ;
    END
  END rn_o[119]
  PIN rn_o[11]
    DIRECTION OUTPUT ;
    USE SIGNAL ;
    PORT
      LAYER M5 ;
        RECT  162.864 172.716 162.888 172.8 ;
    END
  END rn_o[11]
  PIN rn_o[120]
    DIRECTION OUTPUT ;
    USE SIGNAL ;
    PORT
      LAYER M5 ;
        RECT  154.896 172.716 154.92 172.8 ;
    END
  END rn_o[120]
  PIN rn_o[121]
    DIRECTION OUTPUT ;
    USE SIGNAL ;
    PORT
      LAYER M5 ;
        RECT  154.992 172.716 155.016 172.8 ;
    END
  END rn_o[121]
  PIN rn_o[122]
    DIRECTION OUTPUT ;
    USE SIGNAL ;
    PORT
      LAYER M5 ;
        RECT  155.088 172.716 155.112 172.8 ;
    END
  END rn_o[122]
  PIN rn_o[123]
    DIRECTION OUTPUT ;
    USE SIGNAL ;
    PORT
      LAYER M5 ;
        RECT  155.184 172.716 155.208 172.8 ;
    END
  END rn_o[123]
  PIN rn_o[124]
    DIRECTION OUTPUT ;
    USE SIGNAL ;
    PORT
      LAYER M5 ;
        RECT  155.28 172.716 155.304 172.8 ;
    END
  END rn_o[124]
  PIN rn_o[125]
    DIRECTION OUTPUT ;
    USE SIGNAL ;
    PORT
      LAYER M5 ;
        RECT  155.376 172.716 155.4 172.8 ;
    END
  END rn_o[125]
  PIN rn_o[126]
    DIRECTION OUTPUT ;
    USE SIGNAL ;
    PORT
      LAYER M5 ;
        RECT  155.472 172.716 155.496 172.8 ;
    END
  END rn_o[126]
  PIN rn_o[127]
    DIRECTION OUTPUT ;
    USE SIGNAL ;
    PORT
      LAYER M5 ;
        RECT  155.568 172.716 155.592 172.8 ;
    END
  END rn_o[127]
  PIN rn_o[128]
    DIRECTION OUTPUT ;
    USE SIGNAL ;
    PORT
      LAYER M5 ;
        RECT  155.664 172.716 155.688 172.8 ;
    END
  END rn_o[128]
  PIN rn_o[129]
    DIRECTION OUTPUT ;
    USE SIGNAL ;
    PORT
      LAYER M5 ;
        RECT  155.76 172.716 155.784 172.8 ;
    END
  END rn_o[129]
  PIN rn_o[12]
    DIRECTION OUTPUT ;
    USE SIGNAL ;
    PORT
      LAYER M5 ;
        RECT  162.96 172.716 162.984 172.8 ;
    END
  END rn_o[12]
  PIN rn_o[130]
    DIRECTION OUTPUT ;
    USE SIGNAL ;
    PORT
      LAYER M5 ;
        RECT  155.856 172.716 155.88 172.8 ;
    END
  END rn_o[130]
  PIN rn_o[131]
    DIRECTION OUTPUT ;
    USE SIGNAL ;
    PORT
      LAYER M5 ;
        RECT  155.952 172.716 155.976 172.8 ;
    END
  END rn_o[131]
  PIN rn_o[132]
    DIRECTION OUTPUT ;
    USE SIGNAL ;
    PORT
      LAYER M5 ;
        RECT  156.048 172.716 156.072 172.8 ;
    END
  END rn_o[132]
  PIN rn_o[133]
    DIRECTION OUTPUT ;
    USE SIGNAL ;
    PORT
      LAYER M5 ;
        RECT  156.144 172.716 156.168 172.8 ;
    END
  END rn_o[133]
  PIN rn_o[134]
    DIRECTION OUTPUT ;
    USE SIGNAL ;
    PORT
      LAYER M5 ;
        RECT  156.24 172.716 156.264 172.8 ;
    END
  END rn_o[134]
  PIN rn_o[135]
    DIRECTION OUTPUT ;
    USE SIGNAL ;
    PORT
      LAYER M5 ;
        RECT  156.336 172.716 156.36 172.8 ;
    END
  END rn_o[135]
  PIN rn_o[136]
    DIRECTION OUTPUT ;
    USE SIGNAL ;
    PORT
      LAYER M5 ;
        RECT  156.432 172.716 156.456 172.8 ;
    END
  END rn_o[136]
  PIN rn_o[137]
    DIRECTION OUTPUT ;
    USE SIGNAL ;
    PORT
      LAYER M5 ;
        RECT  156.528 172.716 156.552 172.8 ;
    END
  END rn_o[137]
  PIN rn_o[138]
    DIRECTION OUTPUT ;
    USE SIGNAL ;
    PORT
      LAYER M5 ;
        RECT  156.624 172.716 156.648 172.8 ;
    END
  END rn_o[138]
  PIN rn_o[139]
    DIRECTION OUTPUT ;
    USE SIGNAL ;
    PORT
      LAYER M5 ;
        RECT  159.792 172.716 159.816 172.8 ;
    END
  END rn_o[139]
  PIN rn_o[13]
    DIRECTION OUTPUT ;
    USE SIGNAL ;
    PORT
      LAYER M5 ;
        RECT  163.056 172.716 163.08 172.8 ;
    END
  END rn_o[13]
  PIN rn_o[140]
    DIRECTION OUTPUT ;
    USE SIGNAL ;
    PORT
      LAYER M5 ;
        RECT  159.888 172.716 159.912 172.8 ;
    END
  END rn_o[140]
  PIN rn_o[141]
    DIRECTION OUTPUT ;
    USE SIGNAL ;
    PORT
      LAYER M5 ;
        RECT  159.984 172.716 160.008 172.8 ;
    END
  END rn_o[141]
  PIN rn_o[142]
    DIRECTION OUTPUT ;
    USE SIGNAL ;
    PORT
      LAYER M5 ;
        RECT  160.08 172.716 160.104 172.8 ;
    END
  END rn_o[142]
  PIN rn_o[143]
    DIRECTION OUTPUT ;
    USE SIGNAL ;
    PORT
      LAYER M5 ;
        RECT  160.176 172.716 160.2 172.8 ;
    END
  END rn_o[143]
  PIN rn_o[144]
    DIRECTION OUTPUT ;
    USE SIGNAL ;
    PORT
      LAYER M5 ;
        RECT  160.272 172.716 160.296 172.8 ;
    END
  END rn_o[144]
  PIN rn_o[145]
    DIRECTION OUTPUT ;
    USE SIGNAL ;
    PORT
      LAYER M5 ;
        RECT  160.368 172.716 160.392 172.8 ;
    END
  END rn_o[145]
  PIN rn_o[146]
    DIRECTION OUTPUT ;
    USE SIGNAL ;
    PORT
      LAYER M5 ;
        RECT  160.464 172.716 160.488 172.8 ;
    END
  END rn_o[146]
  PIN rn_o[147]
    DIRECTION OUTPUT ;
    USE SIGNAL ;
    PORT
      LAYER M5 ;
        RECT  160.56 172.716 160.584 172.8 ;
    END
  END rn_o[147]
  PIN rn_o[148]
    DIRECTION OUTPUT ;
    USE SIGNAL ;
    PORT
      LAYER M5 ;
        RECT  160.656 172.716 160.68 172.8 ;
    END
  END rn_o[148]
  PIN rn_o[149]
    DIRECTION OUTPUT ;
    USE SIGNAL ;
    PORT
      LAYER M5 ;
        RECT  160.752 172.716 160.776 172.8 ;
    END
  END rn_o[149]
  PIN rn_o[14]
    DIRECTION OUTPUT ;
    USE SIGNAL ;
    PORT
      LAYER M5 ;
        RECT  163.152 172.716 163.176 172.8 ;
    END
  END rn_o[14]
  PIN rn_o[150]
    DIRECTION OUTPUT ;
    USE SIGNAL ;
    PORT
      LAYER M5 ;
        RECT  160.848 172.716 160.872 172.8 ;
    END
  END rn_o[150]
  PIN rn_o[151]
    DIRECTION OUTPUT ;
    USE SIGNAL ;
    PORT
      LAYER M5 ;
        RECT  160.944 172.716 160.968 172.8 ;
    END
  END rn_o[151]
  PIN rn_o[152]
    DIRECTION OUTPUT ;
    USE SIGNAL ;
    PORT
      LAYER M5 ;
        RECT  161.04 172.716 161.064 172.8 ;
    END
  END rn_o[152]
  PIN rn_o[153]
    DIRECTION OUTPUT ;
    USE SIGNAL ;
    PORT
      LAYER M5 ;
        RECT  161.136 172.716 161.16 172.8 ;
    END
  END rn_o[153]
  PIN rn_o[154]
    DIRECTION OUTPUT ;
    USE SIGNAL ;
    PORT
      LAYER M5 ;
        RECT  161.232 172.716 161.256 172.8 ;
    END
  END rn_o[154]
  PIN rn_o[155]
    DIRECTION OUTPUT ;
    USE SIGNAL ;
    PORT
      LAYER M5 ;
        RECT  161.328 172.716 161.352 172.8 ;
    END
  END rn_o[155]
  PIN rn_o[156]
    DIRECTION OUTPUT ;
    USE SIGNAL ;
    PORT
      LAYER M5 ;
        RECT  161.424 172.716 161.448 172.8 ;
    END
  END rn_o[156]
  PIN rn_o[157]
    DIRECTION OUTPUT ;
    USE SIGNAL ;
    PORT
      LAYER M5 ;
        RECT  161.52 172.716 161.544 172.8 ;
    END
  END rn_o[157]
  PIN rn_o[158]
    DIRECTION OUTPUT ;
    USE SIGNAL ;
    PORT
      LAYER M5 ;
        RECT  161.616 172.716 161.64 172.8 ;
    END
  END rn_o[158]
  PIN rn_o[159]
    DIRECTION OUTPUT ;
    USE SIGNAL ;
    PORT
      LAYER M5 ;
        RECT  161.712 172.716 161.736 172.8 ;
    END
  END rn_o[159]
  PIN rn_o[15]
    DIRECTION OUTPUT ;
    USE SIGNAL ;
    PORT
      LAYER M5 ;
        RECT  163.248 172.716 163.272 172.8 ;
    END
  END rn_o[15]
  PIN rn_o[160]
    DIRECTION OUTPUT ;
    USE SIGNAL ;
    PORT
      LAYER M5 ;
        RECT  161.808 172.716 161.832 172.8 ;
    END
  END rn_o[160]
  PIN rn_o[161]
    DIRECTION OUTPUT ;
    USE SIGNAL ;
    PORT
      LAYER M5 ;
        RECT  161.904 172.716 161.928 172.8 ;
    END
  END rn_o[161]
  PIN rn_o[162]
    DIRECTION OUTPUT ;
    USE SIGNAL ;
    PORT
      LAYER M5 ;
        RECT  162 172.716 162.024 172.8 ;
    END
  END rn_o[162]
  PIN rn_o[163]
    DIRECTION OUTPUT ;
    USE SIGNAL ;
    PORT
      LAYER M5 ;
        RECT  162.096 172.716 162.12 172.8 ;
    END
  END rn_o[163]
  PIN rn_o[164]
    DIRECTION OUTPUT ;
    USE SIGNAL ;
    PORT
      LAYER M5 ;
        RECT  162.192 172.716 162.216 172.8 ;
    END
  END rn_o[164]
  PIN rn_o[165]
    DIRECTION OUTPUT ;
    USE SIGNAL ;
    PORT
      LAYER M5 ;
        RECT  162.288 172.716 162.312 172.8 ;
    END
  END rn_o[165]
  PIN rn_o[166]
    DIRECTION OUTPUT ;
    USE SIGNAL ;
    PORT
      LAYER M5 ;
        RECT  162.384 172.716 162.408 172.8 ;
    END
  END rn_o[166]
  PIN rn_o[167]
    DIRECTION OUTPUT ;
    USE SIGNAL ;
    PORT
      LAYER M5 ;
        RECT  162.48 172.716 162.504 172.8 ;
    END
  END rn_o[167]
  PIN rn_o[168]
    DIRECTION OUTPUT ;
    USE SIGNAL ;
    PORT
      LAYER M5 ;
        RECT  162.576 172.716 162.6 172.8 ;
    END
  END rn_o[168]
  PIN rn_o[169]
    DIRECTION OUTPUT ;
    USE SIGNAL ;
    PORT
      LAYER M5 ;
        RECT  162.672 172.716 162.696 172.8 ;
    END
  END rn_o[169]
  PIN rn_o[16]
    DIRECTION OUTPUT ;
    USE SIGNAL ;
    PORT
      LAYER M5 ;
        RECT  163.344 172.716 163.368 172.8 ;
    END
  END rn_o[16]
  PIN rn_o[170]
    DIRECTION OUTPUT ;
    USE SIGNAL ;
    PORT
      LAYER M5 ;
        RECT  162.768 172.716 162.792 172.8 ;
    END
  END rn_o[170]
  PIN rn_o[171]
    DIRECTION OUTPUT ;
    USE SIGNAL ;
    PORT
      LAYER M5 ;
        RECT  192.048 172.716 192.072 172.8 ;
    END
  END rn_o[171]
  PIN rn_o[172]
    DIRECTION OUTPUT ;
    USE SIGNAL ;
    PORT
      LAYER M5 ;
        RECT  192.144 172.716 192.168 172.8 ;
    END
  END rn_o[172]
  PIN rn_o[173]
    DIRECTION OUTPUT ;
    USE SIGNAL ;
    PORT
      LAYER M5 ;
        RECT  192.24 172.716 192.264 172.8 ;
    END
  END rn_o[173]
  PIN rn_o[174]
    DIRECTION OUTPUT ;
    USE SIGNAL ;
    PORT
      LAYER M5 ;
        RECT  192.336 172.716 192.36 172.8 ;
    END
  END rn_o[174]
  PIN rn_o[175]
    DIRECTION OUTPUT ;
    USE SIGNAL ;
    PORT
      LAYER M5 ;
        RECT  192.432 172.716 192.456 172.8 ;
    END
  END rn_o[175]
  PIN rn_o[176]
    DIRECTION OUTPUT ;
    USE SIGNAL ;
    PORT
      LAYER M5 ;
        RECT  192.528 172.716 192.552 172.8 ;
    END
  END rn_o[176]
  PIN rn_o[177]
    DIRECTION OUTPUT ;
    USE SIGNAL ;
    PORT
      LAYER M5 ;
        RECT  192.624 172.716 192.648 172.8 ;
    END
  END rn_o[177]
  PIN rn_o[178]
    DIRECTION OUTPUT ;
    USE SIGNAL ;
    PORT
      LAYER M5 ;
        RECT  192.72 172.716 192.744 172.8 ;
    END
  END rn_o[178]
  PIN rn_o[179]
    DIRECTION OUTPUT ;
    USE SIGNAL ;
    PORT
      LAYER M5 ;
        RECT  192.816 172.716 192.84 172.8 ;
    END
  END rn_o[179]
  PIN rn_o[17]
    DIRECTION OUTPUT ;
    USE SIGNAL ;
    PORT
      LAYER M5 ;
        RECT  163.44 172.716 163.464 172.8 ;
    END
  END rn_o[17]
  PIN rn_o[180]
    DIRECTION OUTPUT ;
    USE SIGNAL ;
    PORT
      LAYER M5 ;
        RECT  192.912 172.716 192.936 172.8 ;
    END
  END rn_o[180]
  PIN rn_o[181]
    DIRECTION OUTPUT ;
    USE SIGNAL ;
    PORT
      LAYER M5 ;
        RECT  193.008 172.716 193.032 172.8 ;
    END
  END rn_o[181]
  PIN rn_o[182]
    DIRECTION OUTPUT ;
    USE SIGNAL ;
    PORT
      LAYER M5 ;
        RECT  193.104 172.716 193.128 172.8 ;
    END
  END rn_o[182]
  PIN rn_o[183]
    DIRECTION OUTPUT ;
    USE SIGNAL ;
    PORT
      LAYER M5 ;
        RECT  193.2 172.716 193.224 172.8 ;
    END
  END rn_o[183]
  PIN rn_o[184]
    DIRECTION OUTPUT ;
    USE SIGNAL ;
    PORT
      LAYER M5 ;
        RECT  193.296 172.716 193.32 172.8 ;
    END
  END rn_o[184]
  PIN rn_o[185]
    DIRECTION OUTPUT ;
    USE SIGNAL ;
    PORT
      LAYER M5 ;
        RECT  193.392 172.716 193.416 172.8 ;
    END
  END rn_o[185]
  PIN rn_o[186]
    DIRECTION OUTPUT ;
    USE SIGNAL ;
    PORT
      LAYER M5 ;
        RECT  193.488 172.716 193.512 172.8 ;
    END
  END rn_o[186]
  PIN rn_o[187]
    DIRECTION OUTPUT ;
    USE SIGNAL ;
    PORT
      LAYER M5 ;
        RECT  193.584 172.716 193.608 172.8 ;
    END
  END rn_o[187]
  PIN rn_o[188]
    DIRECTION OUTPUT ;
    USE SIGNAL ;
    PORT
      LAYER M5 ;
        RECT  193.68 172.716 193.704 172.8 ;
    END
  END rn_o[188]
  PIN rn_o[189]
    DIRECTION OUTPUT ;
    USE SIGNAL ;
    PORT
      LAYER M5 ;
        RECT  193.776 172.716 193.8 172.8 ;
    END
  END rn_o[189]
  PIN rn_o[18]
    DIRECTION OUTPUT ;
    USE SIGNAL ;
    PORT
      LAYER M5 ;
        RECT  163.536 172.716 163.56 172.8 ;
    END
  END rn_o[18]
  PIN rn_o[190]
    DIRECTION OUTPUT ;
    USE SIGNAL ;
    PORT
      LAYER M5 ;
        RECT  193.872 172.716 193.896 172.8 ;
    END
  END rn_o[190]
  PIN rn_o[191]
    DIRECTION OUTPUT ;
    USE SIGNAL ;
    PORT
      LAYER M5 ;
        RECT  193.968 172.716 193.992 172.8 ;
    END
  END rn_o[191]
  PIN rn_o[192]
    DIRECTION OUTPUT ;
    USE SIGNAL ;
    PORT
      LAYER M5 ;
        RECT  194.064 172.716 194.088 172.8 ;
    END
  END rn_o[192]
  PIN rn_o[193]
    DIRECTION OUTPUT ;
    USE SIGNAL ;
    PORT
      LAYER M5 ;
        RECT  194.16 172.716 194.184 172.8 ;
    END
  END rn_o[193]
  PIN rn_o[194]
    DIRECTION OUTPUT ;
    USE SIGNAL ;
    PORT
      LAYER M5 ;
        RECT  194.256 172.716 194.28 172.8 ;
    END
  END rn_o[194]
  PIN rn_o[195]
    DIRECTION OUTPUT ;
    USE SIGNAL ;
    PORT
      LAYER M5 ;
        RECT  194.352 172.716 194.376 172.8 ;
    END
  END rn_o[195]
  PIN rn_o[196]
    DIRECTION OUTPUT ;
    USE SIGNAL ;
    PORT
      LAYER M5 ;
        RECT  194.448 172.716 194.472 172.8 ;
    END
  END rn_o[196]
  PIN rn_o[197]
    DIRECTION OUTPUT ;
    USE SIGNAL ;
    PORT
      LAYER M5 ;
        RECT  194.544 172.716 194.568 172.8 ;
    END
  END rn_o[197]
  PIN rn_o[198]
    DIRECTION OUTPUT ;
    USE SIGNAL ;
    PORT
      LAYER M5 ;
        RECT  194.64 172.716 194.664 172.8 ;
    END
  END rn_o[198]
  PIN rn_o[199]
    DIRECTION OUTPUT ;
    USE SIGNAL ;
    PORT
      LAYER M5 ;
        RECT  194.736 172.716 194.76 172.8 ;
    END
  END rn_o[199]
  PIN rn_o[19]
    DIRECTION OUTPUT ;
    USE SIGNAL ;
    PORT
      LAYER M5 ;
        RECT  163.632 172.716 163.656 172.8 ;
    END
  END rn_o[19]
  PIN rn_o[1]
    DIRECTION OUTPUT ;
    USE SIGNAL ;
    PORT
      LAYER M5 ;
        RECT  168.048 172.716 168.072 172.8 ;
    END
  END rn_o[1]
  PIN rn_o[200]
    DIRECTION OUTPUT ;
    USE SIGNAL ;
    PORT
      LAYER M5 ;
        RECT  194.832 172.716 194.856 172.8 ;
    END
  END rn_o[200]
  PIN rn_o[201]
    DIRECTION OUTPUT ;
    USE SIGNAL ;
    PORT
      LAYER M5 ;
        RECT  194.928 172.716 194.952 172.8 ;
    END
  END rn_o[201]
  PIN rn_o[202]
    DIRECTION OUTPUT ;
    USE SIGNAL ;
    PORT
      LAYER M5 ;
        RECT  195.024 172.716 195.048 172.8 ;
    END
  END rn_o[202]
  PIN rn_o[203]
    DIRECTION OUTPUT ;
    USE SIGNAL ;
    PORT
      LAYER M5 ;
        RECT  198.192 172.716 198.216 172.8 ;
    END
  END rn_o[203]
  PIN rn_o[204]
    DIRECTION OUTPUT ;
    USE SIGNAL ;
    PORT
      LAYER M5 ;
        RECT  198.288 172.716 198.312 172.8 ;
    END
  END rn_o[204]
  PIN rn_o[205]
    DIRECTION OUTPUT ;
    USE SIGNAL ;
    PORT
      LAYER M5 ;
        RECT  198.384 172.716 198.408 172.8 ;
    END
  END rn_o[205]
  PIN rn_o[206]
    DIRECTION OUTPUT ;
    USE SIGNAL ;
    PORT
      LAYER M5 ;
        RECT  198.48 172.716 198.504 172.8 ;
    END
  END rn_o[206]
  PIN rn_o[207]
    DIRECTION OUTPUT ;
    USE SIGNAL ;
    PORT
      LAYER M5 ;
        RECT  198.576 172.716 198.6 172.8 ;
    END
  END rn_o[207]
  PIN rn_o[208]
    DIRECTION OUTPUT ;
    USE SIGNAL ;
    PORT
      LAYER M5 ;
        RECT  198.672 172.716 198.696 172.8 ;
    END
  END rn_o[208]
  PIN rn_o[209]
    DIRECTION OUTPUT ;
    USE SIGNAL ;
    PORT
      LAYER M5 ;
        RECT  198.768 172.716 198.792 172.8 ;
    END
  END rn_o[209]
  PIN rn_o[20]
    DIRECTION OUTPUT ;
    USE SIGNAL ;
    PORT
      LAYER M5 ;
        RECT  163.728 172.716 163.752 172.8 ;
    END
  END rn_o[20]
  PIN rn_o[210]
    DIRECTION OUTPUT ;
    USE SIGNAL ;
    PORT
      LAYER M5 ;
        RECT  198.864 172.716 198.888 172.8 ;
    END
  END rn_o[210]
  PIN rn_o[211]
    DIRECTION OUTPUT ;
    USE SIGNAL ;
    PORT
      LAYER M5 ;
        RECT  198.96 172.716 198.984 172.8 ;
    END
  END rn_o[211]
  PIN rn_o[212]
    DIRECTION OUTPUT ;
    USE SIGNAL ;
    PORT
      LAYER M5 ;
        RECT  199.056 172.716 199.08 172.8 ;
    END
  END rn_o[212]
  PIN rn_o[213]
    DIRECTION OUTPUT ;
    USE SIGNAL ;
    PORT
      LAYER M5 ;
        RECT  199.152 172.716 199.176 172.8 ;
    END
  END rn_o[213]
  PIN rn_o[214]
    DIRECTION OUTPUT ;
    USE SIGNAL ;
    PORT
      LAYER M5 ;
        RECT  199.248 172.716 199.272 172.8 ;
    END
  END rn_o[214]
  PIN rn_o[215]
    DIRECTION OUTPUT ;
    USE SIGNAL ;
    PORT
      LAYER M5 ;
        RECT  199.344 172.716 199.368 172.8 ;
    END
  END rn_o[215]
  PIN rn_o[216]
    DIRECTION OUTPUT ;
    USE SIGNAL ;
    PORT
      LAYER M5 ;
        RECT  199.44 172.716 199.464 172.8 ;
    END
  END rn_o[216]
  PIN rn_o[217]
    DIRECTION OUTPUT ;
    USE SIGNAL ;
    PORT
      LAYER M5 ;
        RECT  199.536 172.716 199.56 172.8 ;
    END
  END rn_o[217]
  PIN rn_o[218]
    DIRECTION OUTPUT ;
    USE SIGNAL ;
    PORT
      LAYER M5 ;
        RECT  199.632 172.716 199.656 172.8 ;
    END
  END rn_o[218]
  PIN rn_o[219]
    DIRECTION OUTPUT ;
    USE SIGNAL ;
    PORT
      LAYER M5 ;
        RECT  199.728 172.716 199.752 172.8 ;
    END
  END rn_o[219]
  PIN rn_o[21]
    DIRECTION OUTPUT ;
    USE SIGNAL ;
    PORT
      LAYER M5 ;
        RECT  163.824 172.716 163.848 172.8 ;
    END
  END rn_o[21]
  PIN rn_o[220]
    DIRECTION OUTPUT ;
    USE SIGNAL ;
    PORT
      LAYER M5 ;
        RECT  199.824 172.716 199.848 172.8 ;
    END
  END rn_o[220]
  PIN rn_o[221]
    DIRECTION OUTPUT ;
    USE SIGNAL ;
    PORT
      LAYER M5 ;
        RECT  199.92 172.716 199.944 172.8 ;
    END
  END rn_o[221]
  PIN rn_o[222]
    DIRECTION OUTPUT ;
    USE SIGNAL ;
    PORT
      LAYER M5 ;
        RECT  200.016 172.716 200.04 172.8 ;
    END
  END rn_o[222]
  PIN rn_o[223]
    DIRECTION OUTPUT ;
    USE SIGNAL ;
    PORT
      LAYER M5 ;
        RECT  200.112 172.716 200.136 172.8 ;
    END
  END rn_o[223]
  PIN rn_o[224]
    DIRECTION OUTPUT ;
    USE SIGNAL ;
    PORT
      LAYER M5 ;
        RECT  200.208 172.716 200.232 172.8 ;
    END
  END rn_o[224]
  PIN rn_o[225]
    DIRECTION OUTPUT ;
    USE SIGNAL ;
    PORT
      LAYER M5 ;
        RECT  200.304 172.716 200.328 172.8 ;
    END
  END rn_o[225]
  PIN rn_o[226]
    DIRECTION OUTPUT ;
    USE SIGNAL ;
    PORT
      LAYER M5 ;
        RECT  200.4 172.716 200.424 172.8 ;
    END
  END rn_o[226]
  PIN rn_o[227]
    DIRECTION OUTPUT ;
    USE SIGNAL ;
    PORT
      LAYER M5 ;
        RECT  200.496 172.716 200.52 172.8 ;
    END
  END rn_o[227]
  PIN rn_o[228]
    DIRECTION OUTPUT ;
    USE SIGNAL ;
    PORT
      LAYER M5 ;
        RECT  200.592 172.716 200.616 172.8 ;
    END
  END rn_o[228]
  PIN rn_o[229]
    DIRECTION OUTPUT ;
    USE SIGNAL ;
    PORT
      LAYER M5 ;
        RECT  200.688 172.716 200.712 172.8 ;
    END
  END rn_o[229]
  PIN rn_o[22]
    DIRECTION OUTPUT ;
    USE SIGNAL ;
    PORT
      LAYER M5 ;
        RECT  163.92 172.716 163.944 172.8 ;
    END
  END rn_o[22]
  PIN rn_o[230]
    DIRECTION OUTPUT ;
    USE SIGNAL ;
    PORT
      LAYER M5 ;
        RECT  200.784 172.716 200.808 172.8 ;
    END
  END rn_o[230]
  PIN rn_o[231]
    DIRECTION OUTPUT ;
    USE SIGNAL ;
    PORT
      LAYER M5 ;
        RECT  200.88 172.716 200.904 172.8 ;
    END
  END rn_o[231]
  PIN rn_o[232]
    DIRECTION OUTPUT ;
    USE SIGNAL ;
    PORT
      LAYER M5 ;
        RECT  200.976 172.716 201 172.8 ;
    END
  END rn_o[232]
  PIN rn_o[233]
    DIRECTION OUTPUT ;
    USE SIGNAL ;
    PORT
      LAYER M5 ;
        RECT  201.072 172.716 201.096 172.8 ;
    END
  END rn_o[233]
  PIN rn_o[234]
    DIRECTION OUTPUT ;
    USE SIGNAL ;
    PORT
      LAYER M5 ;
        RECT  201.168 172.716 201.192 172.8 ;
    END
  END rn_o[234]
  PIN rn_o[235]
    DIRECTION OUTPUT ;
    USE SIGNAL ;
    PORT
      LAYER M5 ;
        RECT  204.336 172.716 204.36 172.8 ;
    END
  END rn_o[235]
  PIN rn_o[236]
    DIRECTION OUTPUT ;
    USE SIGNAL ;
    PORT
      LAYER M5 ;
        RECT  204.432 172.716 204.456 172.8 ;
    END
  END rn_o[236]
  PIN rn_o[237]
    DIRECTION OUTPUT ;
    USE SIGNAL ;
    PORT
      LAYER M5 ;
        RECT  204.528 172.716 204.552 172.8 ;
    END
  END rn_o[237]
  PIN rn_o[238]
    DIRECTION OUTPUT ;
    USE SIGNAL ;
    PORT
      LAYER M5 ;
        RECT  204.624 172.716 204.648 172.8 ;
    END
  END rn_o[238]
  PIN rn_o[239]
    DIRECTION OUTPUT ;
    USE SIGNAL ;
    PORT
      LAYER M5 ;
        RECT  204.72 172.716 204.744 172.8 ;
    END
  END rn_o[239]
  PIN rn_o[23]
    DIRECTION OUTPUT ;
    USE SIGNAL ;
    PORT
      LAYER M5 ;
        RECT  164.016 172.716 164.04 172.8 ;
    END
  END rn_o[23]
  PIN rn_o[240]
    DIRECTION OUTPUT ;
    USE SIGNAL ;
    PORT
      LAYER M5 ;
        RECT  204.816 172.716 204.84 172.8 ;
    END
  END rn_o[240]
  PIN rn_o[241]
    DIRECTION OUTPUT ;
    USE SIGNAL ;
    PORT
      LAYER M5 ;
        RECT  204.912 172.716 204.936 172.8 ;
    END
  END rn_o[241]
  PIN rn_o[242]
    DIRECTION OUTPUT ;
    USE SIGNAL ;
    PORT
      LAYER M5 ;
        RECT  205.008 172.716 205.032 172.8 ;
    END
  END rn_o[242]
  PIN rn_o[243]
    DIRECTION OUTPUT ;
    USE SIGNAL ;
    PORT
      LAYER M5 ;
        RECT  205.104 172.716 205.128 172.8 ;
    END
  END rn_o[243]
  PIN rn_o[244]
    DIRECTION OUTPUT ;
    USE SIGNAL ;
    PORT
      LAYER M5 ;
        RECT  205.2 172.716 205.224 172.8 ;
    END
  END rn_o[244]
  PIN rn_o[245]
    DIRECTION OUTPUT ;
    USE SIGNAL ;
    PORT
      LAYER M5 ;
        RECT  205.296 172.716 205.32 172.8 ;
    END
  END rn_o[245]
  PIN rn_o[246]
    DIRECTION OUTPUT ;
    USE SIGNAL ;
    PORT
      LAYER M5 ;
        RECT  205.392 172.716 205.416 172.8 ;
    END
  END rn_o[246]
  PIN rn_o[247]
    DIRECTION OUTPUT ;
    USE SIGNAL ;
    PORT
      LAYER M5 ;
        RECT  205.488 172.716 205.512 172.8 ;
    END
  END rn_o[247]
  PIN rn_o[248]
    DIRECTION OUTPUT ;
    USE SIGNAL ;
    PORT
      LAYER M5 ;
        RECT  205.584 172.716 205.608 172.8 ;
    END
  END rn_o[248]
  PIN rn_o[249]
    DIRECTION OUTPUT ;
    USE SIGNAL ;
    PORT
      LAYER M5 ;
        RECT  205.68 172.716 205.704 172.8 ;
    END
  END rn_o[249]
  PIN rn_o[24]
    DIRECTION OUTPUT ;
    USE SIGNAL ;
    PORT
      LAYER M5 ;
        RECT  164.112 172.716 164.136 172.8 ;
    END
  END rn_o[24]
  PIN rn_o[250]
    DIRECTION OUTPUT ;
    USE SIGNAL ;
    PORT
      LAYER M5 ;
        RECT  205.776 172.716 205.8 172.8 ;
    END
  END rn_o[250]
  PIN rn_o[251]
    DIRECTION OUTPUT ;
    USE SIGNAL ;
    PORT
      LAYER M5 ;
        RECT  205.872 172.716 205.896 172.8 ;
    END
  END rn_o[251]
  PIN rn_o[252]
    DIRECTION OUTPUT ;
    USE SIGNAL ;
    PORT
      LAYER M5 ;
        RECT  205.968 172.716 205.992 172.8 ;
    END
  END rn_o[252]
  PIN rn_o[253]
    DIRECTION OUTPUT ;
    USE SIGNAL ;
    PORT
      LAYER M5 ;
        RECT  206.064 172.716 206.088 172.8 ;
    END
  END rn_o[253]
  PIN rn_o[254]
    DIRECTION OUTPUT ;
    USE SIGNAL ;
    PORT
      LAYER M5 ;
        RECT  206.16 172.716 206.184 172.8 ;
    END
  END rn_o[254]
  PIN rn_o[255]
    DIRECTION OUTPUT ;
    USE SIGNAL ;
    PORT
      LAYER M5 ;
        RECT  206.256 172.716 206.28 172.8 ;
    END
  END rn_o[255]
  PIN rn_o[256]
    DIRECTION OUTPUT ;
    USE SIGNAL ;
    PORT
      LAYER M5 ;
        RECT  206.352 172.716 206.376 172.8 ;
    END
  END rn_o[256]
  PIN rn_o[257]
    DIRECTION OUTPUT ;
    USE SIGNAL ;
    PORT
      LAYER M5 ;
        RECT  206.448 172.716 206.472 172.8 ;
    END
  END rn_o[257]
  PIN rn_o[258]
    DIRECTION OUTPUT ;
    USE SIGNAL ;
    PORT
      LAYER M5 ;
        RECT  206.544 172.716 206.568 172.8 ;
    END
  END rn_o[258]
  PIN rn_o[259]
    DIRECTION OUTPUT ;
    USE SIGNAL ;
    PORT
      LAYER M5 ;
        RECT  206.64 172.716 206.664 172.8 ;
    END
  END rn_o[259]
  PIN rn_o[25]
    DIRECTION OUTPUT ;
    USE SIGNAL ;
    PORT
      LAYER M5 ;
        RECT  164.208 172.716 164.232 172.8 ;
    END
  END rn_o[25]
  PIN rn_o[260]
    DIRECTION OUTPUT ;
    USE SIGNAL ;
    PORT
      LAYER M5 ;
        RECT  206.736 172.716 206.76 172.8 ;
    END
  END rn_o[260]
  PIN rn_o[261]
    DIRECTION OUTPUT ;
    USE SIGNAL ;
    PORT
      LAYER M5 ;
        RECT  206.832 172.716 206.856 172.8 ;
    END
  END rn_o[261]
  PIN rn_o[262]
    DIRECTION OUTPUT ;
    USE SIGNAL ;
    PORT
      LAYER M5 ;
        RECT  206.928 172.716 206.952 172.8 ;
    END
  END rn_o[262]
  PIN rn_o[263]
    DIRECTION OUTPUT ;
    USE SIGNAL ;
    PORT
      LAYER M5 ;
        RECT  207.024 172.716 207.048 172.8 ;
    END
  END rn_o[263]
  PIN rn_o[264]
    DIRECTION OUTPUT ;
    USE SIGNAL ;
    PORT
      LAYER M5 ;
        RECT  207.12 172.716 207.144 172.8 ;
    END
  END rn_o[264]
  PIN rn_o[265]
    DIRECTION OUTPUT ;
    USE SIGNAL ;
    PORT
      LAYER M5 ;
        RECT  207.216 172.716 207.24 172.8 ;
    END
  END rn_o[265]
  PIN rn_o[266]
    DIRECTION OUTPUT ;
    USE SIGNAL ;
    PORT
      LAYER M5 ;
        RECT  207.312 172.716 207.336 172.8 ;
    END
  END rn_o[266]
  PIN rn_o[267]
    DIRECTION OUTPUT ;
    USE SIGNAL ;
    PORT
      LAYER M5 ;
        RECT  195.12 172.716 195.144 172.8 ;
    END
  END rn_o[267]
  PIN rn_o[268]
    DIRECTION OUTPUT ;
    USE SIGNAL ;
    PORT
      LAYER M5 ;
        RECT  195.216 172.716 195.24 172.8 ;
    END
  END rn_o[268]
  PIN rn_o[269]
    DIRECTION OUTPUT ;
    USE SIGNAL ;
    PORT
      LAYER M5 ;
        RECT  195.312 172.716 195.336 172.8 ;
    END
  END rn_o[269]
  PIN rn_o[26]
    DIRECTION OUTPUT ;
    USE SIGNAL ;
    PORT
      LAYER M5 ;
        RECT  164.304 172.716 164.328 172.8 ;
    END
  END rn_o[26]
  PIN rn_o[270]
    DIRECTION OUTPUT ;
    USE SIGNAL ;
    PORT
      LAYER M5 ;
        RECT  195.408 172.716 195.432 172.8 ;
    END
  END rn_o[270]
  PIN rn_o[271]
    DIRECTION OUTPUT ;
    USE SIGNAL ;
    PORT
      LAYER M5 ;
        RECT  195.504 172.716 195.528 172.8 ;
    END
  END rn_o[271]
  PIN rn_o[272]
    DIRECTION OUTPUT ;
    USE SIGNAL ;
    PORT
      LAYER M5 ;
        RECT  195.6 172.716 195.624 172.8 ;
    END
  END rn_o[272]
  PIN rn_o[273]
    DIRECTION OUTPUT ;
    USE SIGNAL ;
    PORT
      LAYER M5 ;
        RECT  195.696 172.716 195.72 172.8 ;
    END
  END rn_o[273]
  PIN rn_o[274]
    DIRECTION OUTPUT ;
    USE SIGNAL ;
    PORT
      LAYER M5 ;
        RECT  195.792 172.716 195.816 172.8 ;
    END
  END rn_o[274]
  PIN rn_o[275]
    DIRECTION OUTPUT ;
    USE SIGNAL ;
    PORT
      LAYER M5 ;
        RECT  195.888 172.716 195.912 172.8 ;
    END
  END rn_o[275]
  PIN rn_o[27]
    DIRECTION OUTPUT ;
    USE SIGNAL ;
    PORT
      LAYER M5 ;
        RECT  164.4 172.716 164.424 172.8 ;
    END
  END rn_o[27]
  PIN rn_o[28]
    DIRECTION OUTPUT ;
    USE SIGNAL ;
    PORT
      LAYER M5 ;
        RECT  164.496 172.716 164.52 172.8 ;
    END
  END rn_o[28]
  PIN rn_o[29]
    DIRECTION OUTPUT ;
    USE SIGNAL ;
    PORT
      LAYER M5 ;
        RECT  164.592 172.716 164.616 172.8 ;
    END
  END rn_o[29]
  PIN rn_o[2]
    DIRECTION OUTPUT ;
    USE SIGNAL ;
    PORT
      LAYER M5 ;
        RECT  168.144 172.716 168.168 172.8 ;
    END
  END rn_o[2]
  PIN rn_o[30]
    DIRECTION OUTPUT ;
    USE SIGNAL ;
    PORT
      LAYER M5 ;
        RECT  164.688 172.716 164.712 172.8 ;
    END
  END rn_o[30]
  PIN rn_o[31]
    DIRECTION OUTPUT ;
    USE SIGNAL ;
    PORT
      LAYER M5 ;
        RECT  164.784 172.716 164.808 172.8 ;
    END
  END rn_o[31]
  PIN rn_o[32]
    DIRECTION OUTPUT ;
    USE SIGNAL ;
    PORT
      LAYER M5 ;
        RECT  164.88 172.716 164.904 172.8 ;
    END
  END rn_o[32]
  PIN rn_o[33]
    DIRECTION OUTPUT ;
    USE SIGNAL ;
    PORT
      LAYER M5 ;
        RECT  164.976 172.716 165 172.8 ;
    END
  END rn_o[33]
  PIN rn_o[34]
    DIRECTION OUTPUT ;
    USE SIGNAL ;
    PORT
      LAYER M5 ;
        RECT  165.072 172.716 165.096 172.8 ;
    END
  END rn_o[34]
  PIN rn_o[35]
    DIRECTION OUTPUT ;
    USE SIGNAL ;
    PORT
      LAYER M5 ;
        RECT  165.168 172.716 165.192 172.8 ;
    END
  END rn_o[35]
  PIN rn_o[36]
    DIRECTION OUTPUT ;
    USE SIGNAL ;
    PORT
      LAYER M5 ;
        RECT  165.264 172.716 165.288 172.8 ;
    END
  END rn_o[36]
  PIN rn_o[37]
    DIRECTION OUTPUT ;
    USE SIGNAL ;
    PORT
      LAYER M5 ;
        RECT  165.36 172.716 165.384 172.8 ;
    END
  END rn_o[37]
  PIN rn_o[38]
    DIRECTION OUTPUT ;
    USE SIGNAL ;
    PORT
      LAYER M5 ;
        RECT  165.456 172.716 165.48 172.8 ;
    END
  END rn_o[38]
  PIN rn_o[39]
    DIRECTION OUTPUT ;
    USE SIGNAL ;
    PORT
      LAYER M5 ;
        RECT  165.552 172.716 165.576 172.8 ;
    END
  END rn_o[39]
  PIN rn_o[3]
    DIRECTION OUTPUT ;
    USE SIGNAL ;
    PORT
      LAYER M5 ;
        RECT  168.24 172.716 168.264 172.8 ;
    END
  END rn_o[3]
  PIN rn_o[40]
    DIRECTION OUTPUT ;
    USE SIGNAL ;
    PORT
      LAYER M5 ;
        RECT  165.648 172.716 165.672 172.8 ;
    END
  END rn_o[40]
  PIN rn_o[41]
    DIRECTION OUTPUT ;
    USE SIGNAL ;
    PORT
      LAYER M5 ;
        RECT  165.744 172.716 165.768 172.8 ;
    END
  END rn_o[41]
  PIN rn_o[42]
    DIRECTION OUTPUT ;
    USE SIGNAL ;
    PORT
      LAYER M5 ;
        RECT  165.84 172.716 165.864 172.8 ;
    END
  END rn_o[42]
  PIN rn_o[43]
    DIRECTION OUTPUT ;
    USE SIGNAL ;
    PORT
      LAYER M5 ;
        RECT  169.008 172.716 169.032 172.8 ;
    END
  END rn_o[43]
  PIN rn_o[44]
    DIRECTION OUTPUT ;
    USE SIGNAL ;
    PORT
      LAYER M5 ;
        RECT  169.104 172.716 169.128 172.8 ;
    END
  END rn_o[44]
  PIN rn_o[45]
    DIRECTION OUTPUT ;
    USE SIGNAL ;
    PORT
      LAYER M5 ;
        RECT  169.2 172.716 169.224 172.8 ;
    END
  END rn_o[45]
  PIN rn_o[46]
    DIRECTION OUTPUT ;
    USE SIGNAL ;
    PORT
      LAYER M5 ;
        RECT  169.296 172.716 169.32 172.8 ;
    END
  END rn_o[46]
  PIN rn_o[47]
    DIRECTION OUTPUT ;
    USE SIGNAL ;
    PORT
      LAYER M5 ;
        RECT  169.392 172.716 169.416 172.8 ;
    END
  END rn_o[47]
  PIN rn_o[48]
    DIRECTION OUTPUT ;
    USE SIGNAL ;
    PORT
      LAYER M5 ;
        RECT  169.488 172.716 169.512 172.8 ;
    END
  END rn_o[48]
  PIN rn_o[49]
    DIRECTION OUTPUT ;
    USE SIGNAL ;
    PORT
      LAYER M5 ;
        RECT  169.584 172.716 169.608 172.8 ;
    END
  END rn_o[49]
  PIN rn_o[4]
    DIRECTION OUTPUT ;
    USE SIGNAL ;
    PORT
      LAYER M5 ;
        RECT  168.336 172.716 168.36 172.8 ;
    END
  END rn_o[4]
  PIN rn_o[50]
    DIRECTION OUTPUT ;
    USE SIGNAL ;
    PORT
      LAYER M5 ;
        RECT  169.68 172.716 169.704 172.8 ;
    END
  END rn_o[50]
  PIN rn_o[51]
    DIRECTION OUTPUT ;
    USE SIGNAL ;
    PORT
      LAYER M5 ;
        RECT  169.776 172.716 169.8 172.8 ;
    END
  END rn_o[51]
  PIN rn_o[52]
    DIRECTION OUTPUT ;
    USE SIGNAL ;
    PORT
      LAYER M5 ;
        RECT  169.872 172.716 169.896 172.8 ;
    END
  END rn_o[52]
  PIN rn_o[53]
    DIRECTION OUTPUT ;
    USE SIGNAL ;
    PORT
      LAYER M5 ;
        RECT  169.968 172.716 169.992 172.8 ;
    END
  END rn_o[53]
  PIN rn_o[54]
    DIRECTION OUTPUT ;
    USE SIGNAL ;
    PORT
      LAYER M5 ;
        RECT  170.064 172.716 170.088 172.8 ;
    END
  END rn_o[54]
  PIN rn_o[55]
    DIRECTION OUTPUT ;
    USE SIGNAL ;
    PORT
      LAYER M5 ;
        RECT  170.16 172.716 170.184 172.8 ;
    END
  END rn_o[55]
  PIN rn_o[56]
    DIRECTION OUTPUT ;
    USE SIGNAL ;
    PORT
      LAYER M5 ;
        RECT  170.256 172.716 170.28 172.8 ;
    END
  END rn_o[56]
  PIN rn_o[57]
    DIRECTION OUTPUT ;
    USE SIGNAL ;
    PORT
      LAYER M5 ;
        RECT  170.352 172.716 170.376 172.8 ;
    END
  END rn_o[57]
  PIN rn_o[58]
    DIRECTION OUTPUT ;
    USE SIGNAL ;
    PORT
      LAYER M5 ;
        RECT  170.448 172.716 170.472 172.8 ;
    END
  END rn_o[58]
  PIN rn_o[59]
    DIRECTION OUTPUT ;
    USE SIGNAL ;
    PORT
      LAYER M5 ;
        RECT  170.544 172.716 170.568 172.8 ;
    END
  END rn_o[59]
  PIN rn_o[5]
    DIRECTION OUTPUT ;
    USE SIGNAL ;
    PORT
      LAYER M5 ;
        RECT  168.432 172.716 168.456 172.8 ;
    END
  END rn_o[5]
  PIN rn_o[60]
    DIRECTION OUTPUT ;
    USE SIGNAL ;
    PORT
      LAYER M5 ;
        RECT  170.64 172.716 170.664 172.8 ;
    END
  END rn_o[60]
  PIN rn_o[61]
    DIRECTION OUTPUT ;
    USE SIGNAL ;
    PORT
      LAYER M5 ;
        RECT  170.736 172.716 170.76 172.8 ;
    END
  END rn_o[61]
  PIN rn_o[62]
    DIRECTION OUTPUT ;
    USE SIGNAL ;
    PORT
      LAYER M5 ;
        RECT  170.832 172.716 170.856 172.8 ;
    END
  END rn_o[62]
  PIN rn_o[63]
    DIRECTION OUTPUT ;
    USE SIGNAL ;
    PORT
      LAYER M5 ;
        RECT  170.928 172.716 170.952 172.8 ;
    END
  END rn_o[63]
  PIN rn_o[64]
    DIRECTION OUTPUT ;
    USE SIGNAL ;
    PORT
      LAYER M5 ;
        RECT  171.024 172.716 171.048 172.8 ;
    END
  END rn_o[64]
  PIN rn_o[65]
    DIRECTION OUTPUT ;
    USE SIGNAL ;
    PORT
      LAYER M5 ;
        RECT  171.12 172.716 171.144 172.8 ;
    END
  END rn_o[65]
  PIN rn_o[66]
    DIRECTION OUTPUT ;
    USE SIGNAL ;
    PORT
      LAYER M5 ;
        RECT  171.216 172.716 171.24 172.8 ;
    END
  END rn_o[66]
  PIN rn_o[67]
    DIRECTION OUTPUT ;
    USE SIGNAL ;
    PORT
      LAYER M5 ;
        RECT  171.312 172.716 171.336 172.8 ;
    END
  END rn_o[67]
  PIN rn_o[68]
    DIRECTION OUTPUT ;
    USE SIGNAL ;
    PORT
      LAYER M5 ;
        RECT  171.408 172.716 171.432 172.8 ;
    END
  END rn_o[68]
  PIN rn_o[69]
    DIRECTION OUTPUT ;
    USE SIGNAL ;
    PORT
      LAYER M5 ;
        RECT  171.504 172.716 171.528 172.8 ;
    END
  END rn_o[69]
  PIN rn_o[6]
    DIRECTION OUTPUT ;
    USE SIGNAL ;
    PORT
      LAYER M5 ;
        RECT  168.528 172.716 168.552 172.8 ;
    END
  END rn_o[6]
  PIN rn_o[70]
    DIRECTION OUTPUT ;
    USE SIGNAL ;
    PORT
      LAYER M5 ;
        RECT  171.6 172.716 171.624 172.8 ;
    END
  END rn_o[70]
  PIN rn_o[71]
    DIRECTION OUTPUT ;
    USE SIGNAL ;
    PORT
      LAYER M5 ;
        RECT  171.696 172.716 171.72 172.8 ;
    END
  END rn_o[71]
  PIN rn_o[72]
    DIRECTION OUTPUT ;
    USE SIGNAL ;
    PORT
      LAYER M5 ;
        RECT  171.792 172.716 171.816 172.8 ;
    END
  END rn_o[72]
  PIN rn_o[73]
    DIRECTION OUTPUT ;
    USE SIGNAL ;
    PORT
      LAYER M5 ;
        RECT  171.888 172.716 171.912 172.8 ;
    END
  END rn_o[73]
  PIN rn_o[74]
    DIRECTION OUTPUT ;
    USE SIGNAL ;
    PORT
      LAYER M5 ;
        RECT  171.984 172.716 172.008 172.8 ;
    END
  END rn_o[74]
  PIN rn_o[75]
    DIRECTION OUTPUT ;
    USE SIGNAL ;
    PORT
      LAYER M5 ;
        RECT  207.408 172.716 207.432 172.8 ;
    END
  END rn_o[75]
  PIN rn_o[76]
    DIRECTION OUTPUT ;
    USE SIGNAL ;
    PORT
      LAYER M5 ;
        RECT  207.504 172.716 207.528 172.8 ;
    END
  END rn_o[76]
  PIN rn_o[77]
    DIRECTION OUTPUT ;
    USE SIGNAL ;
    PORT
      LAYER M5 ;
        RECT  207.6 172.716 207.624 172.8 ;
    END
  END rn_o[77]
  PIN rn_o[78]
    DIRECTION OUTPUT ;
    USE SIGNAL ;
    PORT
      LAYER M5 ;
        RECT  207.696 172.716 207.72 172.8 ;
    END
  END rn_o[78]
  PIN rn_o[79]
    DIRECTION OUTPUT ;
    USE SIGNAL ;
    PORT
      LAYER M5 ;
        RECT  207.792 172.716 207.816 172.8 ;
    END
  END rn_o[79]
  PIN rn_o[7]
    DIRECTION OUTPUT ;
    USE SIGNAL ;
    PORT
      LAYER M5 ;
        RECT  168.624 172.716 168.648 172.8 ;
    END
  END rn_o[7]
  PIN rn_o[80]
    DIRECTION OUTPUT ;
    USE SIGNAL ;
    PORT
      LAYER M5 ;
        RECT  207.888 172.716 207.912 172.8 ;
    END
  END rn_o[80]
  PIN rn_o[81]
    DIRECTION OUTPUT ;
    USE SIGNAL ;
    PORT
      LAYER M5 ;
        RECT  207.984 172.716 208.008 172.8 ;
    END
  END rn_o[81]
  PIN rn_o[82]
    DIRECTION OUTPUT ;
    USE SIGNAL ;
    PORT
      LAYER M5 ;
        RECT  208.08 172.716 208.104 172.8 ;
    END
  END rn_o[82]
  PIN rn_o[83]
    DIRECTION OUTPUT ;
    USE SIGNAL ;
    PORT
      LAYER M5 ;
        RECT  208.176 172.716 208.2 172.8 ;
    END
  END rn_o[83]
  PIN rn_o[84]
    DIRECTION OUTPUT ;
    USE SIGNAL ;
    PORT
      LAYER M5 ;
        RECT  208.272 172.716 208.296 172.8 ;
    END
  END rn_o[84]
  PIN rn_o[85]
    DIRECTION OUTPUT ;
    USE SIGNAL ;
    PORT
      LAYER M5 ;
        RECT  208.368 172.716 208.392 172.8 ;
    END
  END rn_o[85]
  PIN rn_o[86]
    DIRECTION OUTPUT ;
    USE SIGNAL ;
    PORT
      LAYER M5 ;
        RECT  208.464 172.716 208.488 172.8 ;
    END
  END rn_o[86]
  PIN rn_o[87]
    DIRECTION OUTPUT ;
    USE SIGNAL ;
    PORT
      LAYER M5 ;
        RECT  208.56 172.716 208.584 172.8 ;
    END
  END rn_o[87]
  PIN rn_o[88]
    DIRECTION OUTPUT ;
    USE SIGNAL ;
    PORT
      LAYER M5 ;
        RECT  208.656 172.716 208.68 172.8 ;
    END
  END rn_o[88]
  PIN rn_o[89]
    DIRECTION OUTPUT ;
    USE SIGNAL ;
    PORT
      LAYER M5 ;
        RECT  208.752 172.716 208.776 172.8 ;
    END
  END rn_o[89]
  PIN rn_o[8]
    DIRECTION OUTPUT ;
    USE SIGNAL ;
    PORT
      LAYER M5 ;
        RECT  168.72 172.716 168.744 172.8 ;
    END
  END rn_o[8]
  PIN rn_o[90]
    DIRECTION OUTPUT ;
    USE SIGNAL ;
    PORT
      LAYER M5 ;
        RECT  208.848 172.716 208.872 172.8 ;
    END
  END rn_o[90]
  PIN rn_o[91]
    DIRECTION OUTPUT ;
    USE SIGNAL ;
    PORT
      LAYER M5 ;
        RECT  208.944 172.716 208.968 172.8 ;
    END
  END rn_o[91]
  PIN rn_o[92]
    DIRECTION OUTPUT ;
    USE SIGNAL ;
    PORT
      LAYER M5 ;
        RECT  209.04 172.716 209.064 172.8 ;
    END
  END rn_o[92]
  PIN rn_o[93]
    DIRECTION OUTPUT ;
    USE SIGNAL ;
    PORT
      LAYER M5 ;
        RECT  209.136 172.716 209.16 172.8 ;
    END
  END rn_o[93]
  PIN rn_o[94]
    DIRECTION OUTPUT ;
    USE SIGNAL ;
    PORT
      LAYER M5 ;
        RECT  209.232 172.716 209.256 172.8 ;
    END
  END rn_o[94]
  PIN rn_o[95]
    DIRECTION OUTPUT ;
    USE SIGNAL ;
    PORT
      LAYER M5 ;
        RECT  209.328 172.716 209.352 172.8 ;
    END
  END rn_o[95]
  PIN rn_o[96]
    DIRECTION OUTPUT ;
    USE SIGNAL ;
    PORT
      LAYER M5 ;
        RECT  209.424 172.716 209.448 172.8 ;
    END
  END rn_o[96]
  PIN rn_o[97]
    DIRECTION OUTPUT ;
    USE SIGNAL ;
    PORT
      LAYER M5 ;
        RECT  209.52 172.716 209.544 172.8 ;
    END
  END rn_o[97]
  PIN rn_o[98]
    DIRECTION OUTPUT ;
    USE SIGNAL ;
    PORT
      LAYER M5 ;
        RECT  209.616 172.716 209.64 172.8 ;
    END
  END rn_o[98]
  PIN rn_o[99]
    DIRECTION OUTPUT ;
    USE SIGNAL ;
    PORT
      LAYER M5 ;
        RECT  209.712 172.716 209.736 172.8 ;
    END
  END rn_o[99]
  PIN rn_o[9]
    DIRECTION OUTPUT ;
    USE SIGNAL ;
    PORT
      LAYER M5 ;
        RECT  168.816 172.716 168.84 172.8 ;
    END
  END rn_o[9]
  PIN rst_n
    DIRECTION INPUT ;
    USE SIGNAL ;
    PORT
      LAYER M4 ;
        RECT  345.516 98.544 345.6 98.568 ;
    END
  END rst_n
  PIN rw_l
    DIRECTION INPUT ;
    USE SIGNAL ;
    PORT
      LAYER M5 ;
        RECT  195.984 172.716 196.008 172.8 ;
    END
  END rw_l
  PIN rw_lm[0]
    DIRECTION INPUT ;
    USE SIGNAL ;
    PORT
      LAYER M5 ;
        RECT  196.08 172.716 196.104 172.8 ;
    END
  END rw_lm[0]
  PIN rw_lm[1]
    DIRECTION INPUT ;
    USE SIGNAL ;
    PORT
      LAYER M5 ;
        RECT  196.176 172.716 196.2 172.8 ;
    END
  END rw_lm[1]
  PIN rw_lm[2]
    DIRECTION INPUT ;
    USE SIGNAL ;
    PORT
      LAYER M5 ;
        RECT  196.272 172.716 196.296 172.8 ;
    END
  END rw_lm[2]
  PIN rw_lm[3]
    DIRECTION INPUT ;
    USE SIGNAL ;
    PORT
      LAYER M5 ;
        RECT  196.368 172.716 196.392 172.8 ;
    END
  END rw_lm[3]
  PIN rw_lm[4]
    DIRECTION INPUT ;
    USE SIGNAL ;
    PORT
      LAYER M5 ;
        RECT  196.464 172.716 196.488 172.8 ;
    END
  END rw_lm[4]
  PIN rw_row[0]
    DIRECTION INPUT ;
    USE SIGNAL ;
    PORT
      LAYER M5 ;
        RECT  196.56 172.716 196.584 172.8 ;
    END
  END rw_row[0]
  PIN rw_row[1]
    DIRECTION INPUT ;
    USE SIGNAL ;
    PORT
      LAYER M5 ;
        RECT  196.656 172.716 196.68 172.8 ;
    END
  END rw_row[1]
  PIN rw_row[2]
    DIRECTION INPUT ;
    USE SIGNAL ;
    PORT
      LAYER M5 ;
        RECT  196.752 172.716 196.776 172.8 ;
    END
  END rw_row[2]
  PIN rw_row[3]
    DIRECTION INPUT ;
    USE SIGNAL ;
    PORT
      LAYER M5 ;
        RECT  196.848 172.716 196.872 172.8 ;
    END
  END rw_row[3]
  PIN rw_row[4]
    DIRECTION INPUT ;
    USE SIGNAL ;
    PORT
      LAYER M5 ;
        RECT  196.944 172.716 196.968 172.8 ;
    END
  END rw_row[4]
  PIN rw_row[5]
    DIRECTION INPUT ;
    USE SIGNAL ;
    PORT
      LAYER M5 ;
        RECT  197.04 172.716 197.064 172.8 ;
    END
  END rw_row[5]
  PIN rw_row[6]
    DIRECTION INPUT ;
    USE SIGNAL ;
    PORT
      LAYER M5 ;
        RECT  197.136 172.716 197.16 172.8 ;
    END
  END rw_row[6]
  PIN rw_row[7]
    DIRECTION INPUT ;
    USE SIGNAL ;
    PORT
      LAYER M5 ;
        RECT  197.232 172.716 197.256 172.8 ;
    END
  END rw_row[7]
  PIN rw_row[8]
    DIRECTION INPUT ;
    USE SIGNAL ;
    PORT
      LAYER M5 ;
        RECT  197.328 172.716 197.352 172.8 ;
    END
  END rw_row[8]
  PIN rw_row[9]
    DIRECTION INPUT ;
    USE SIGNAL ;
    PORT
      LAYER M5 ;
        RECT  197.424 172.716 197.448 172.8 ;
    END
  END rw_row[9]
  PIN rw_scale[0]
    DIRECTION INPUT ;
    USE SIGNAL ;
    PORT
      LAYER M5 ;
        RECT  197.52 172.716 197.544 172.8 ;
    END
  END rw_scale[0]
  PIN rw_scale[10]
    DIRECTION INPUT ;
    USE SIGNAL ;
    PORT
      LAYER M5 ;
        RECT  150.096 172.716 150.12 172.8 ;
    END
  END rw_scale[10]
  PIN rw_scale[11]
    DIRECTION INPUT ;
    USE SIGNAL ;
    PORT
      LAYER M5 ;
        RECT  150.192 172.716 150.216 172.8 ;
    END
  END rw_scale[11]
  PIN rw_scale[12]
    DIRECTION INPUT ;
    USE SIGNAL ;
    PORT
      LAYER M5 ;
        RECT  150.288 172.716 150.312 172.8 ;
    END
  END rw_scale[12]
  PIN rw_scale[13]
    DIRECTION INPUT ;
    USE SIGNAL ;
    PORT
      LAYER M5 ;
        RECT  150.384 172.716 150.408 172.8 ;
    END
  END rw_scale[13]
  PIN rw_scale[14]
    DIRECTION INPUT ;
    USE SIGNAL ;
    PORT
      LAYER M5 ;
        RECT  150.48 172.716 150.504 172.8 ;
    END
  END rw_scale[14]
  PIN rw_scale[15]
    DIRECTION INPUT ;
    USE SIGNAL ;
    PORT
      LAYER M5 ;
        RECT  150.576 172.716 150.6 172.8 ;
    END
  END rw_scale[15]
  PIN rw_scale[16]
    DIRECTION INPUT ;
    USE SIGNAL ;
    PORT
      LAYER M5 ;
        RECT  150.672 172.716 150.696 172.8 ;
    END
  END rw_scale[16]
  PIN rw_scale[17]
    DIRECTION INPUT ;
    USE SIGNAL ;
    PORT
      LAYER M5 ;
        RECT  150.768 172.716 150.792 172.8 ;
    END
  END rw_scale[17]
  PIN rw_scale[18]
    DIRECTION INPUT ;
    USE SIGNAL ;
    PORT
      LAYER M5 ;
        RECT  150.864 172.716 150.888 172.8 ;
    END
  END rw_scale[18]
  PIN rw_scale[19]
    DIRECTION INPUT ;
    USE SIGNAL ;
    PORT
      LAYER M5 ;
        RECT  150.96 172.716 150.984 172.8 ;
    END
  END rw_scale[19]
  PIN rw_scale[1]
    DIRECTION INPUT ;
    USE SIGNAL ;
    PORT
      LAYER M5 ;
        RECT  197.616 172.716 197.64 172.8 ;
    END
  END rw_scale[1]
  PIN rw_scale[20]
    DIRECTION INPUT ;
    USE SIGNAL ;
    PORT
      LAYER M5 ;
        RECT  151.056 172.716 151.08 172.8 ;
    END
  END rw_scale[20]
  PIN rw_scale[21]
    DIRECTION INPUT ;
    USE SIGNAL ;
    PORT
      LAYER M5 ;
        RECT  151.152 172.716 151.176 172.8 ;
    END
  END rw_scale[21]
  PIN rw_scale[22]
    DIRECTION INPUT ;
    USE SIGNAL ;
    PORT
      LAYER M5 ;
        RECT  151.248 172.716 151.272 172.8 ;
    END
  END rw_scale[22]
  PIN rw_scale[23]
    DIRECTION INPUT ;
    USE SIGNAL ;
    PORT
      LAYER M5 ;
        RECT  151.344 172.716 151.368 172.8 ;
    END
  END rw_scale[23]
  PIN rw_scale[24]
    DIRECTION INPUT ;
    USE SIGNAL ;
    PORT
      LAYER M5 ;
        RECT  151.44 172.716 151.464 172.8 ;
    END
  END rw_scale[24]
  PIN rw_scale[25]
    DIRECTION INPUT ;
    USE SIGNAL ;
    PORT
      LAYER M5 ;
        RECT  151.536 172.716 151.56 172.8 ;
    END
  END rw_scale[25]
  PIN rw_scale[26]
    DIRECTION INPUT ;
    USE SIGNAL ;
    PORT
      LAYER M5 ;
        RECT  151.632 172.716 151.656 172.8 ;
    END
  END rw_scale[26]
  PIN rw_scale[27]
    DIRECTION INPUT ;
    USE SIGNAL ;
    PORT
      LAYER M5 ;
        RECT  151.728 172.716 151.752 172.8 ;
    END
  END rw_scale[27]
  PIN rw_scale[28]
    DIRECTION INPUT ;
    USE SIGNAL ;
    PORT
      LAYER M5 ;
        RECT  151.824 172.716 151.848 172.8 ;
    END
  END rw_scale[28]
  PIN rw_scale[29]
    DIRECTION INPUT ;
    USE SIGNAL ;
    PORT
      LAYER M5 ;
        RECT  151.92 172.716 151.944 172.8 ;
    END
  END rw_scale[29]
  PIN rw_scale[2]
    DIRECTION INPUT ;
    USE SIGNAL ;
    PORT
      LAYER M5 ;
        RECT  197.712 172.716 197.736 172.8 ;
    END
  END rw_scale[2]
  PIN rw_scale[30]
    DIRECTION INPUT ;
    USE SIGNAL ;
    PORT
      LAYER M5 ;
        RECT  152.016 172.716 152.04 172.8 ;
    END
  END rw_scale[30]
  PIN rw_scale[31]
    DIRECTION INPUT ;
    USE SIGNAL ;
    PORT
      LAYER M5 ;
        RECT  152.112 172.716 152.136 172.8 ;
    END
  END rw_scale[31]
  PIN rw_scale[3]
    DIRECTION INPUT ;
    USE SIGNAL ;
    PORT
      LAYER M5 ;
        RECT  197.808 172.716 197.832 172.8 ;
    END
  END rw_scale[3]
  PIN rw_scale[4]
    DIRECTION INPUT ;
    USE SIGNAL ;
    PORT
      LAYER M5 ;
        RECT  197.904 172.716 197.928 172.8 ;
    END
  END rw_scale[4]
  PIN rw_scale[5]
    DIRECTION INPUT ;
    USE SIGNAL ;
    PORT
      LAYER M5 ;
        RECT  198 172.716 198.024 172.8 ;
    END
  END rw_scale[5]
  PIN rw_scale[6]
    DIRECTION INPUT ;
    USE SIGNAL ;
    PORT
      LAYER M5 ;
        RECT  198.096 172.716 198.12 172.8 ;
    END
  END rw_scale[6]
  PIN rw_scale[7]
    DIRECTION INPUT ;
    USE SIGNAL ;
    PORT
      LAYER M5 ;
        RECT  149.808 172.716 149.832 172.8 ;
    END
  END rw_scale[7]
  PIN rw_scale[8]
    DIRECTION INPUT ;
    USE SIGNAL ;
    PORT
      LAYER M5 ;
        RECT  149.904 172.716 149.928 172.8 ;
    END
  END rw_scale[8]
  PIN rw_scale[9]
    DIRECTION INPUT ;
    USE SIGNAL ;
    PORT
      LAYER M5 ;
        RECT  150 172.716 150.024 172.8 ;
    END
  END rw_scale[9]
  PIN rw_sm[0]
    DIRECTION INPUT ;
    USE SIGNAL ;
    PORT
      LAYER M5 ;
        RECT  152.208 172.716 152.232 172.8 ;
    END
  END rw_sm[0]
  PIN rw_sm[10]
    DIRECTION INPUT ;
    USE SIGNAL ;
    PORT
      LAYER M5 ;
        RECT  130.896 172.716 130.92 172.8 ;
    END
  END rw_sm[10]
  PIN rw_sm[11]
    DIRECTION INPUT ;
    USE SIGNAL ;
    PORT
      LAYER M5 ;
        RECT  130.992 172.716 131.016 172.8 ;
    END
  END rw_sm[11]
  PIN rw_sm[12]
    DIRECTION INPUT ;
    USE SIGNAL ;
    PORT
      LAYER M5 ;
        RECT  131.088 172.716 131.112 172.8 ;
    END
  END rw_sm[12]
  PIN rw_sm[13]
    DIRECTION INPUT ;
    USE SIGNAL ;
    PORT
      LAYER M5 ;
        RECT  131.184 172.716 131.208 172.8 ;
    END
  END rw_sm[13]
  PIN rw_sm[14]
    DIRECTION INPUT ;
    USE SIGNAL ;
    PORT
      LAYER M5 ;
        RECT  131.28 172.716 131.304 172.8 ;
    END
  END rw_sm[14]
  PIN rw_sm[15]
    DIRECTION INPUT ;
    USE SIGNAL ;
    PORT
      LAYER M5 ;
        RECT  131.376 172.716 131.4 172.8 ;
    END
  END rw_sm[15]
  PIN rw_sm[1]
    DIRECTION INPUT ;
    USE SIGNAL ;
    PORT
      LAYER M5 ;
        RECT  152.304 172.716 152.328 172.8 ;
    END
  END rw_sm[1]
  PIN rw_sm[2]
    DIRECTION INPUT ;
    USE SIGNAL ;
    PORT
      LAYER M5 ;
        RECT  152.4 172.716 152.424 172.8 ;
    END
  END rw_sm[2]
  PIN rw_sm[3]
    DIRECTION INPUT ;
    USE SIGNAL ;
    PORT
      LAYER M5 ;
        RECT  152.496 172.716 152.52 172.8 ;
    END
  END rw_sm[3]
  PIN rw_sm[4]
    DIRECTION INPUT ;
    USE SIGNAL ;
    PORT
      LAYER M5 ;
        RECT  152.592 172.716 152.616 172.8 ;
    END
  END rw_sm[4]
  PIN rw_sm[5]
    DIRECTION INPUT ;
    USE SIGNAL ;
    PORT
      LAYER M5 ;
        RECT  152.688 172.716 152.712 172.8 ;
    END
  END rw_sm[5]
  PIN rw_sm[6]
    DIRECTION INPUT ;
    USE SIGNAL ;
    PORT
      LAYER M5 ;
        RECT  152.784 172.716 152.808 172.8 ;
    END
  END rw_sm[6]
  PIN rw_sm[7]
    DIRECTION INPUT ;
    USE SIGNAL ;
    PORT
      LAYER M5 ;
        RECT  130.608 172.716 130.632 172.8 ;
    END
  END rw_sm[7]
  PIN rw_sm[8]
    DIRECTION INPUT ;
    USE SIGNAL ;
    PORT
      LAYER M5 ;
        RECT  130.704 172.716 130.728 172.8 ;
    END
  END rw_sm[8]
  PIN rw_sm[9]
    DIRECTION INPUT ;
    USE SIGNAL ;
    PORT
      LAYER M5 ;
        RECT  130.8 172.716 130.824 172.8 ;
    END
  END rw_sm[9]
  PIN rw_st
    DIRECTION INPUT ;
    USE SIGNAL ;
    PORT
      LAYER M5 ;
        RECT  131.472 172.716 131.496 172.8 ;
    END
  END rw_st
  PIN rw_v
    DIRECTION INPUT ;
    USE SIGNAL ;
    PORT
      LAYER M5 ;
        RECT  131.568 172.716 131.592 172.8 ;
    END
  END rw_v
  PIN rw_x[0]
    DIRECTION INPUT ;
    USE SIGNAL ;
    PORT
      LAYER M5 ;
        RECT  131.664 172.716 131.688 172.8 ;
    END
  END rw_x[0]
  PIN rw_x[100]
    DIRECTION INPUT ;
    USE SIGNAL ;
    PORT
      LAYER M5 ;
        RECT  112.848 172.716 112.872 172.8 ;
    END
  END rw_x[100]
  PIN rw_x[101]
    DIRECTION INPUT ;
    USE SIGNAL ;
    PORT
      LAYER M5 ;
        RECT  112.944 172.716 112.968 172.8 ;
    END
  END rw_x[101]
  PIN rw_x[102]
    DIRECTION INPUT ;
    USE SIGNAL ;
    PORT
      LAYER M5 ;
        RECT  113.04 172.716 113.064 172.8 ;
    END
  END rw_x[102]
  PIN rw_x[103]
    DIRECTION INPUT ;
    USE SIGNAL ;
    PORT
      LAYER M5 ;
        RECT  113.136 172.716 113.16 172.8 ;
    END
  END rw_x[103]
  PIN rw_x[104]
    DIRECTION INPUT ;
    USE SIGNAL ;
    PORT
      LAYER M5 ;
        RECT  113.232 172.716 113.256 172.8 ;
    END
  END rw_x[104]
  PIN rw_x[105]
    DIRECTION INPUT ;
    USE SIGNAL ;
    PORT
      LAYER M5 ;
        RECT  113.328 172.716 113.352 172.8 ;
    END
  END rw_x[105]
  PIN rw_x[106]
    DIRECTION INPUT ;
    USE SIGNAL ;
    PORT
      LAYER M5 ;
        RECT  113.424 172.716 113.448 172.8 ;
    END
  END rw_x[106]
  PIN rw_x[107]
    DIRECTION INPUT ;
    USE SIGNAL ;
    PORT
      LAYER M5 ;
        RECT  113.52 172.716 113.544 172.8 ;
    END
  END rw_x[107]
  PIN rw_x[108]
    DIRECTION INPUT ;
    USE SIGNAL ;
    PORT
      LAYER M5 ;
        RECT  113.616 172.716 113.64 172.8 ;
    END
  END rw_x[108]
  PIN rw_x[109]
    DIRECTION INPUT ;
    USE SIGNAL ;
    PORT
      LAYER M5 ;
        RECT  113.712 172.716 113.736 172.8 ;
    END
  END rw_x[109]
  PIN rw_x[10]
    DIRECTION INPUT ;
    USE SIGNAL ;
    PORT
      LAYER M5 ;
        RECT  132.624 172.716 132.648 172.8 ;
    END
  END rw_x[10]
  PIN rw_x[110]
    DIRECTION INPUT ;
    USE SIGNAL ;
    PORT
      LAYER M5 ;
        RECT  113.808 172.716 113.832 172.8 ;
    END
  END rw_x[110]
  PIN rw_x[111]
    DIRECTION INPUT ;
    USE SIGNAL ;
    PORT
      LAYER M5 ;
        RECT  113.904 172.716 113.928 172.8 ;
    END
  END rw_x[111]
  PIN rw_x[112]
    DIRECTION INPUT ;
    USE SIGNAL ;
    PORT
      LAYER M5 ;
        RECT  114 172.716 114.024 172.8 ;
    END
  END rw_x[112]
  PIN rw_x[113]
    DIRECTION INPUT ;
    USE SIGNAL ;
    PORT
      LAYER M5 ;
        RECT  114.096 172.716 114.12 172.8 ;
    END
  END rw_x[113]
  PIN rw_x[114]
    DIRECTION INPUT ;
    USE SIGNAL ;
    PORT
      LAYER M5 ;
        RECT  114.192 172.716 114.216 172.8 ;
    END
  END rw_x[114]
  PIN rw_x[115]
    DIRECTION INPUT ;
    USE SIGNAL ;
    PORT
      LAYER M5 ;
        RECT  114.288 172.716 114.312 172.8 ;
    END
  END rw_x[115]
  PIN rw_x[116]
    DIRECTION INPUT ;
    USE SIGNAL ;
    PORT
      LAYER M5 ;
        RECT  114.384 172.716 114.408 172.8 ;
    END
  END rw_x[116]
  PIN rw_x[117]
    DIRECTION INPUT ;
    USE SIGNAL ;
    PORT
      LAYER M5 ;
        RECT  102.192 172.716 102.216 172.8 ;
    END
  END rw_x[117]
  PIN rw_x[118]
    DIRECTION INPUT ;
    USE SIGNAL ;
    PORT
      LAYER M5 ;
        RECT  102.288 172.716 102.312 172.8 ;
    END
  END rw_x[118]
  PIN rw_x[119]
    DIRECTION INPUT ;
    USE SIGNAL ;
    PORT
      LAYER M5 ;
        RECT  102.384 172.716 102.408 172.8 ;
    END
  END rw_x[119]
  PIN rw_x[11]
    DIRECTION INPUT ;
    USE SIGNAL ;
    PORT
      LAYER M5 ;
        RECT  132.72 172.716 132.744 172.8 ;
    END
  END rw_x[11]
  PIN rw_x[120]
    DIRECTION INPUT ;
    USE SIGNAL ;
    PORT
      LAYER M5 ;
        RECT  102.48 172.716 102.504 172.8 ;
    END
  END rw_x[120]
  PIN rw_x[121]
    DIRECTION INPUT ;
    USE SIGNAL ;
    PORT
      LAYER M5 ;
        RECT  102.576 172.716 102.6 172.8 ;
    END
  END rw_x[121]
  PIN rw_x[122]
    DIRECTION INPUT ;
    USE SIGNAL ;
    PORT
      LAYER M5 ;
        RECT  102.672 172.716 102.696 172.8 ;
    END
  END rw_x[122]
  PIN rw_x[123]
    DIRECTION INPUT ;
    USE SIGNAL ;
    PORT
      LAYER M5 ;
        RECT  102.768 172.716 102.792 172.8 ;
    END
  END rw_x[123]
  PIN rw_x[124]
    DIRECTION INPUT ;
    USE SIGNAL ;
    PORT
      LAYER M5 ;
        RECT  102.864 172.716 102.888 172.8 ;
    END
  END rw_x[124]
  PIN rw_x[125]
    DIRECTION INPUT ;
    USE SIGNAL ;
    PORT
      LAYER M5 ;
        RECT  102.96 172.716 102.984 172.8 ;
    END
  END rw_x[125]
  PIN rw_x[126]
    DIRECTION INPUT ;
    USE SIGNAL ;
    PORT
      LAYER M5 ;
        RECT  103.056 172.716 103.08 172.8 ;
    END
  END rw_x[126]
  PIN rw_x[127]
    DIRECTION INPUT ;
    USE SIGNAL ;
    PORT
      LAYER M5 ;
        RECT  103.152 172.716 103.176 172.8 ;
    END
  END rw_x[127]
  PIN rw_x[128]
    DIRECTION INPUT ;
    USE SIGNAL ;
    PORT
      LAYER M5 ;
        RECT  103.248 172.716 103.272 172.8 ;
    END
  END rw_x[128]
  PIN rw_x[129]
    DIRECTION INPUT ;
    USE SIGNAL ;
    PORT
      LAYER M5 ;
        RECT  103.344 172.716 103.368 172.8 ;
    END
  END rw_x[129]
  PIN rw_x[12]
    DIRECTION INPUT ;
    USE SIGNAL ;
    PORT
      LAYER M5 ;
        RECT  132.816 172.716 132.84 172.8 ;
    END
  END rw_x[12]
  PIN rw_x[130]
    DIRECTION INPUT ;
    USE SIGNAL ;
    PORT
      LAYER M5 ;
        RECT  103.44 172.716 103.464 172.8 ;
    END
  END rw_x[130]
  PIN rw_x[131]
    DIRECTION INPUT ;
    USE SIGNAL ;
    PORT
      LAYER M5 ;
        RECT  103.536 172.716 103.56 172.8 ;
    END
  END rw_x[131]
  PIN rw_x[132]
    DIRECTION INPUT ;
    USE SIGNAL ;
    PORT
      LAYER M5 ;
        RECT  103.632 172.716 103.656 172.8 ;
    END
  END rw_x[132]
  PIN rw_x[133]
    DIRECTION INPUT ;
    USE SIGNAL ;
    PORT
      LAYER M5 ;
        RECT  103.728 172.716 103.752 172.8 ;
    END
  END rw_x[133]
  PIN rw_x[134]
    DIRECTION INPUT ;
    USE SIGNAL ;
    PORT
      LAYER M5 ;
        RECT  103.824 172.716 103.848 172.8 ;
    END
  END rw_x[134]
  PIN rw_x[135]
    DIRECTION INPUT ;
    USE SIGNAL ;
    PORT
      LAYER M5 ;
        RECT  103.92 172.716 103.944 172.8 ;
    END
  END rw_x[135]
  PIN rw_x[136]
    DIRECTION INPUT ;
    USE SIGNAL ;
    PORT
      LAYER M5 ;
        RECT  104.016 172.716 104.04 172.8 ;
    END
  END rw_x[136]
  PIN rw_x[137]
    DIRECTION INPUT ;
    USE SIGNAL ;
    PORT
      LAYER M5 ;
        RECT  104.112 172.716 104.136 172.8 ;
    END
  END rw_x[137]
  PIN rw_x[138]
    DIRECTION INPUT ;
    USE SIGNAL ;
    PORT
      LAYER M5 ;
        RECT  104.208 172.716 104.232 172.8 ;
    END
  END rw_x[138]
  PIN rw_x[139]
    DIRECTION INPUT ;
    USE SIGNAL ;
    PORT
      LAYER M5 ;
        RECT  104.304 172.716 104.328 172.8 ;
    END
  END rw_x[139]
  PIN rw_x[13]
    DIRECTION INPUT ;
    USE SIGNAL ;
    PORT
      LAYER M5 ;
        RECT  132.912 172.716 132.936 172.8 ;
    END
  END rw_x[13]
  PIN rw_x[140]
    DIRECTION INPUT ;
    USE SIGNAL ;
    PORT
      LAYER M5 ;
        RECT  104.4 172.716 104.424 172.8 ;
    END
  END rw_x[140]
  PIN rw_x[141]
    DIRECTION INPUT ;
    USE SIGNAL ;
    PORT
      LAYER M5 ;
        RECT  104.496 172.716 104.52 172.8 ;
    END
  END rw_x[141]
  PIN rw_x[142]
    DIRECTION INPUT ;
    USE SIGNAL ;
    PORT
      LAYER M5 ;
        RECT  104.592 172.716 104.616 172.8 ;
    END
  END rw_x[142]
  PIN rw_x[143]
    DIRECTION INPUT ;
    USE SIGNAL ;
    PORT
      LAYER M5 ;
        RECT  104.688 172.716 104.712 172.8 ;
    END
  END rw_x[143]
  PIN rw_x[144]
    DIRECTION INPUT ;
    USE SIGNAL ;
    PORT
      LAYER M5 ;
        RECT  104.784 172.716 104.808 172.8 ;
    END
  END rw_x[144]
  PIN rw_x[145]
    DIRECTION INPUT ;
    USE SIGNAL ;
    PORT
      LAYER M5 ;
        RECT  104.88 172.716 104.904 172.8 ;
    END
  END rw_x[145]
  PIN rw_x[146]
    DIRECTION INPUT ;
    USE SIGNAL ;
    PORT
      LAYER M5 ;
        RECT  104.976 172.716 105 172.8 ;
    END
  END rw_x[146]
  PIN rw_x[147]
    DIRECTION INPUT ;
    USE SIGNAL ;
    PORT
      LAYER M5 ;
        RECT  105.072 172.716 105.096 172.8 ;
    END
  END rw_x[147]
  PIN rw_x[148]
    DIRECTION INPUT ;
    USE SIGNAL ;
    PORT
      LAYER M5 ;
        RECT  105.168 172.716 105.192 172.8 ;
    END
  END rw_x[148]
  PIN rw_x[149]
    DIRECTION INPUT ;
    USE SIGNAL ;
    PORT
      LAYER M5 ;
        RECT  99.12 172.716 99.144 172.8 ;
    END
  END rw_x[149]
  PIN rw_x[14]
    DIRECTION INPUT ;
    USE SIGNAL ;
    PORT
      LAYER M5 ;
        RECT  133.008 172.716 133.032 172.8 ;
    END
  END rw_x[14]
  PIN rw_x[150]
    DIRECTION INPUT ;
    USE SIGNAL ;
    PORT
      LAYER M5 ;
        RECT  99.216 172.716 99.24 172.8 ;
    END
  END rw_x[150]
  PIN rw_x[151]
    DIRECTION INPUT ;
    USE SIGNAL ;
    PORT
      LAYER M5 ;
        RECT  99.312 172.716 99.336 172.8 ;
    END
  END rw_x[151]
  PIN rw_x[152]
    DIRECTION INPUT ;
    USE SIGNAL ;
    PORT
      LAYER M5 ;
        RECT  99.408 172.716 99.432 172.8 ;
    END
  END rw_x[152]
  PIN rw_x[153]
    DIRECTION INPUT ;
    USE SIGNAL ;
    PORT
      LAYER M5 ;
        RECT  99.504 172.716 99.528 172.8 ;
    END
  END rw_x[153]
  PIN rw_x[154]
    DIRECTION INPUT ;
    USE SIGNAL ;
    PORT
      LAYER M5 ;
        RECT  99.6 172.716 99.624 172.8 ;
    END
  END rw_x[154]
  PIN rw_x[155]
    DIRECTION INPUT ;
    USE SIGNAL ;
    PORT
      LAYER M5 ;
        RECT  99.696 172.716 99.72 172.8 ;
    END
  END rw_x[155]
  PIN rw_x[156]
    DIRECTION INPUT ;
    USE SIGNAL ;
    PORT
      LAYER M5 ;
        RECT  99.792 172.716 99.816 172.8 ;
    END
  END rw_x[156]
  PIN rw_x[157]
    DIRECTION INPUT ;
    USE SIGNAL ;
    PORT
      LAYER M5 ;
        RECT  99.888 172.716 99.912 172.8 ;
    END
  END rw_x[157]
  PIN rw_x[158]
    DIRECTION INPUT ;
    USE SIGNAL ;
    PORT
      LAYER M5 ;
        RECT  99.984 172.716 100.008 172.8 ;
    END
  END rw_x[158]
  PIN rw_x[159]
    DIRECTION INPUT ;
    USE SIGNAL ;
    PORT
      LAYER M5 ;
        RECT  100.08 172.716 100.104 172.8 ;
    END
  END rw_x[159]
  PIN rw_x[15]
    DIRECTION INPUT ;
    USE SIGNAL ;
    PORT
      LAYER M5 ;
        RECT  133.104 172.716 133.128 172.8 ;
    END
  END rw_x[15]
  PIN rw_x[160]
    DIRECTION INPUT ;
    USE SIGNAL ;
    PORT
      LAYER M5 ;
        RECT  100.176 172.716 100.2 172.8 ;
    END
  END rw_x[160]
  PIN rw_x[161]
    DIRECTION INPUT ;
    USE SIGNAL ;
    PORT
      LAYER M5 ;
        RECT  100.272 172.716 100.296 172.8 ;
    END
  END rw_x[161]
  PIN rw_x[162]
    DIRECTION INPUT ;
    USE SIGNAL ;
    PORT
      LAYER M5 ;
        RECT  100.368 172.716 100.392 172.8 ;
    END
  END rw_x[162]
  PIN rw_x[163]
    DIRECTION INPUT ;
    USE SIGNAL ;
    PORT
      LAYER M5 ;
        RECT  100.464 172.716 100.488 172.8 ;
    END
  END rw_x[163]
  PIN rw_x[164]
    DIRECTION INPUT ;
    USE SIGNAL ;
    PORT
      LAYER M5 ;
        RECT  100.56 172.716 100.584 172.8 ;
    END
  END rw_x[164]
  PIN rw_x[165]
    DIRECTION INPUT ;
    USE SIGNAL ;
    PORT
      LAYER M5 ;
        RECT  100.656 172.716 100.68 172.8 ;
    END
  END rw_x[165]
  PIN rw_x[166]
    DIRECTION INPUT ;
    USE SIGNAL ;
    PORT
      LAYER M5 ;
        RECT  100.752 172.716 100.776 172.8 ;
    END
  END rw_x[166]
  PIN rw_x[167]
    DIRECTION INPUT ;
    USE SIGNAL ;
    PORT
      LAYER M5 ;
        RECT  100.848 172.716 100.872 172.8 ;
    END
  END rw_x[167]
  PIN rw_x[168]
    DIRECTION INPUT ;
    USE SIGNAL ;
    PORT
      LAYER M5 ;
        RECT  100.944 172.716 100.968 172.8 ;
    END
  END rw_x[168]
  PIN rw_x[169]
    DIRECTION INPUT ;
    USE SIGNAL ;
    PORT
      LAYER M5 ;
        RECT  101.04 172.716 101.064 172.8 ;
    END
  END rw_x[169]
  PIN rw_x[16]
    DIRECTION INPUT ;
    USE SIGNAL ;
    PORT
      LAYER M5 ;
        RECT  133.2 172.716 133.224 172.8 ;
    END
  END rw_x[16]
  PIN rw_x[170]
    DIRECTION INPUT ;
    USE SIGNAL ;
    PORT
      LAYER M5 ;
        RECT  101.136 172.716 101.16 172.8 ;
    END
  END rw_x[170]
  PIN rw_x[171]
    DIRECTION INPUT ;
    USE SIGNAL ;
    PORT
      LAYER M5 ;
        RECT  101.232 172.716 101.256 172.8 ;
    END
  END rw_x[171]
  PIN rw_x[172]
    DIRECTION INPUT ;
    USE SIGNAL ;
    PORT
      LAYER M5 ;
        RECT  101.328 172.716 101.352 172.8 ;
    END
  END rw_x[172]
  PIN rw_x[173]
    DIRECTION INPUT ;
    USE SIGNAL ;
    PORT
      LAYER M5 ;
        RECT  101.424 172.716 101.448 172.8 ;
    END
  END rw_x[173]
  PIN rw_x[174]
    DIRECTION INPUT ;
    USE SIGNAL ;
    PORT
      LAYER M5 ;
        RECT  101.52 172.716 101.544 172.8 ;
    END
  END rw_x[174]
  PIN rw_x[175]
    DIRECTION INPUT ;
    USE SIGNAL ;
    PORT
      LAYER M5 ;
        RECT  101.616 172.716 101.64 172.8 ;
    END
  END rw_x[175]
  PIN rw_x[176]
    DIRECTION INPUT ;
    USE SIGNAL ;
    PORT
      LAYER M5 ;
        RECT  101.712 172.716 101.736 172.8 ;
    END
  END rw_x[176]
  PIN rw_x[177]
    DIRECTION INPUT ;
    USE SIGNAL ;
    PORT
      LAYER M5 ;
        RECT  101.808 172.716 101.832 172.8 ;
    END
  END rw_x[177]
  PIN rw_x[178]
    DIRECTION INPUT ;
    USE SIGNAL ;
    PORT
      LAYER M5 ;
        RECT  101.904 172.716 101.928 172.8 ;
    END
  END rw_x[178]
  PIN rw_x[179]
    DIRECTION INPUT ;
    USE SIGNAL ;
    PORT
      LAYER M5 ;
        RECT  102 172.716 102.024 172.8 ;
    END
  END rw_x[179]
  PIN rw_x[17]
    DIRECTION INPUT ;
    USE SIGNAL ;
    PORT
      LAYER M5 ;
        RECT  133.296 172.716 133.32 172.8 ;
    END
  END rw_x[17]
  PIN rw_x[180]
    DIRECTION INPUT ;
    USE SIGNAL ;
    PORT
      LAYER M5 ;
        RECT  102.096 172.716 102.12 172.8 ;
    END
  END rw_x[180]
  PIN rw_x[181]
    DIRECTION INPUT ;
    USE SIGNAL ;
    PORT
      LAYER M5 ;
        RECT  96.048 172.716 96.072 172.8 ;
    END
  END rw_x[181]
  PIN rw_x[182]
    DIRECTION INPUT ;
    USE SIGNAL ;
    PORT
      LAYER M5 ;
        RECT  96.144 172.716 96.168 172.8 ;
    END
  END rw_x[182]
  PIN rw_x[183]
    DIRECTION INPUT ;
    USE SIGNAL ;
    PORT
      LAYER M5 ;
        RECT  96.24 172.716 96.264 172.8 ;
    END
  END rw_x[183]
  PIN rw_x[184]
    DIRECTION INPUT ;
    USE SIGNAL ;
    PORT
      LAYER M5 ;
        RECT  96.336 172.716 96.36 172.8 ;
    END
  END rw_x[184]
  PIN rw_x[185]
    DIRECTION INPUT ;
    USE SIGNAL ;
    PORT
      LAYER M5 ;
        RECT  96.432 172.716 96.456 172.8 ;
    END
  END rw_x[185]
  PIN rw_x[186]
    DIRECTION INPUT ;
    USE SIGNAL ;
    PORT
      LAYER M5 ;
        RECT  96.528 172.716 96.552 172.8 ;
    END
  END rw_x[186]
  PIN rw_x[187]
    DIRECTION INPUT ;
    USE SIGNAL ;
    PORT
      LAYER M5 ;
        RECT  96.624 172.716 96.648 172.8 ;
    END
  END rw_x[187]
  PIN rw_x[188]
    DIRECTION INPUT ;
    USE SIGNAL ;
    PORT
      LAYER M5 ;
        RECT  96.72 172.716 96.744 172.8 ;
    END
  END rw_x[188]
  PIN rw_x[189]
    DIRECTION INPUT ;
    USE SIGNAL ;
    PORT
      LAYER M5 ;
        RECT  96.816 172.716 96.84 172.8 ;
    END
  END rw_x[189]
  PIN rw_x[18]
    DIRECTION INPUT ;
    USE SIGNAL ;
    PORT
      LAYER M5 ;
        RECT  133.392 172.716 133.416 172.8 ;
    END
  END rw_x[18]
  PIN rw_x[190]
    DIRECTION INPUT ;
    USE SIGNAL ;
    PORT
      LAYER M5 ;
        RECT  96.912 172.716 96.936 172.8 ;
    END
  END rw_x[190]
  PIN rw_x[191]
    DIRECTION INPUT ;
    USE SIGNAL ;
    PORT
      LAYER M5 ;
        RECT  97.008 172.716 97.032 172.8 ;
    END
  END rw_x[191]
  PIN rw_x[19]
    DIRECTION INPUT ;
    USE SIGNAL ;
    PORT
      LAYER M5 ;
        RECT  133.488 172.716 133.512 172.8 ;
    END
  END rw_x[19]
  PIN rw_x[1]
    DIRECTION INPUT ;
    USE SIGNAL ;
    PORT
      LAYER M5 ;
        RECT  131.76 172.716 131.784 172.8 ;
    END
  END rw_x[1]
  PIN rw_x[20]
    DIRECTION INPUT ;
    USE SIGNAL ;
    PORT
      LAYER M5 ;
        RECT  133.584 172.716 133.608 172.8 ;
    END
  END rw_x[20]
  PIN rw_x[21]
    DIRECTION INPUT ;
    USE SIGNAL ;
    PORT
      LAYER M5 ;
        RECT  105.264 172.716 105.288 172.8 ;
    END
  END rw_x[21]
  PIN rw_x[22]
    DIRECTION INPUT ;
    USE SIGNAL ;
    PORT
      LAYER M5 ;
        RECT  105.36 172.716 105.384 172.8 ;
    END
  END rw_x[22]
  PIN rw_x[23]
    DIRECTION INPUT ;
    USE SIGNAL ;
    PORT
      LAYER M5 ;
        RECT  105.456 172.716 105.48 172.8 ;
    END
  END rw_x[23]
  PIN rw_x[24]
    DIRECTION INPUT ;
    USE SIGNAL ;
    PORT
      LAYER M5 ;
        RECT  105.552 172.716 105.576 172.8 ;
    END
  END rw_x[24]
  PIN rw_x[25]
    DIRECTION INPUT ;
    USE SIGNAL ;
    PORT
      LAYER M5 ;
        RECT  105.648 172.716 105.672 172.8 ;
    END
  END rw_x[25]
  PIN rw_x[26]
    DIRECTION INPUT ;
    USE SIGNAL ;
    PORT
      LAYER M5 ;
        RECT  105.744 172.716 105.768 172.8 ;
    END
  END rw_x[26]
  PIN rw_x[27]
    DIRECTION INPUT ;
    USE SIGNAL ;
    PORT
      LAYER M5 ;
        RECT  105.84 172.716 105.864 172.8 ;
    END
  END rw_x[27]
  PIN rw_x[28]
    DIRECTION INPUT ;
    USE SIGNAL ;
    PORT
      LAYER M5 ;
        RECT  105.936 172.716 105.96 172.8 ;
    END
  END rw_x[28]
  PIN rw_x[29]
    DIRECTION INPUT ;
    USE SIGNAL ;
    PORT
      LAYER M5 ;
        RECT  106.032 172.716 106.056 172.8 ;
    END
  END rw_x[29]
  PIN rw_x[2]
    DIRECTION INPUT ;
    USE SIGNAL ;
    PORT
      LAYER M5 ;
        RECT  131.856 172.716 131.88 172.8 ;
    END
  END rw_x[2]
  PIN rw_x[30]
    DIRECTION INPUT ;
    USE SIGNAL ;
    PORT
      LAYER M5 ;
        RECT  106.128 172.716 106.152 172.8 ;
    END
  END rw_x[30]
  PIN rw_x[31]
    DIRECTION INPUT ;
    USE SIGNAL ;
    PORT
      LAYER M5 ;
        RECT  106.224 172.716 106.248 172.8 ;
    END
  END rw_x[31]
  PIN rw_x[32]
    DIRECTION INPUT ;
    USE SIGNAL ;
    PORT
      LAYER M5 ;
        RECT  106.32 172.716 106.344 172.8 ;
    END
  END rw_x[32]
  PIN rw_x[33]
    DIRECTION INPUT ;
    USE SIGNAL ;
    PORT
      LAYER M5 ;
        RECT  106.416 172.716 106.44 172.8 ;
    END
  END rw_x[33]
  PIN rw_x[34]
    DIRECTION INPUT ;
    USE SIGNAL ;
    PORT
      LAYER M5 ;
        RECT  106.512 172.716 106.536 172.8 ;
    END
  END rw_x[34]
  PIN rw_x[35]
    DIRECTION INPUT ;
    USE SIGNAL ;
    PORT
      LAYER M5 ;
        RECT  106.608 172.716 106.632 172.8 ;
    END
  END rw_x[35]
  PIN rw_x[36]
    DIRECTION INPUT ;
    USE SIGNAL ;
    PORT
      LAYER M5 ;
        RECT  106.704 172.716 106.728 172.8 ;
    END
  END rw_x[36]
  PIN rw_x[37]
    DIRECTION INPUT ;
    USE SIGNAL ;
    PORT
      LAYER M5 ;
        RECT  106.8 172.716 106.824 172.8 ;
    END
  END rw_x[37]
  PIN rw_x[38]
    DIRECTION INPUT ;
    USE SIGNAL ;
    PORT
      LAYER M5 ;
        RECT  106.896 172.716 106.92 172.8 ;
    END
  END rw_x[38]
  PIN rw_x[39]
    DIRECTION INPUT ;
    USE SIGNAL ;
    PORT
      LAYER M5 ;
        RECT  106.992 172.716 107.016 172.8 ;
    END
  END rw_x[39]
  PIN rw_x[3]
    DIRECTION INPUT ;
    USE SIGNAL ;
    PORT
      LAYER M5 ;
        RECT  131.952 172.716 131.976 172.8 ;
    END
  END rw_x[3]
  PIN rw_x[40]
    DIRECTION INPUT ;
    USE SIGNAL ;
    PORT
      LAYER M5 ;
        RECT  107.088 172.716 107.112 172.8 ;
    END
  END rw_x[40]
  PIN rw_x[41]
    DIRECTION INPUT ;
    USE SIGNAL ;
    PORT
      LAYER M5 ;
        RECT  107.184 172.716 107.208 172.8 ;
    END
  END rw_x[41]
  PIN rw_x[42]
    DIRECTION INPUT ;
    USE SIGNAL ;
    PORT
      LAYER M5 ;
        RECT  107.28 172.716 107.304 172.8 ;
    END
  END rw_x[42]
  PIN rw_x[43]
    DIRECTION INPUT ;
    USE SIGNAL ;
    PORT
      LAYER M5 ;
        RECT  107.376 172.716 107.4 172.8 ;
    END
  END rw_x[43]
  PIN rw_x[44]
    DIRECTION INPUT ;
    USE SIGNAL ;
    PORT
      LAYER M5 ;
        RECT  107.472 172.716 107.496 172.8 ;
    END
  END rw_x[44]
  PIN rw_x[45]
    DIRECTION INPUT ;
    USE SIGNAL ;
    PORT
      LAYER M5 ;
        RECT  107.568 172.716 107.592 172.8 ;
    END
  END rw_x[45]
  PIN rw_x[46]
    DIRECTION INPUT ;
    USE SIGNAL ;
    PORT
      LAYER M5 ;
        RECT  107.664 172.716 107.688 172.8 ;
    END
  END rw_x[46]
  PIN rw_x[47]
    DIRECTION INPUT ;
    USE SIGNAL ;
    PORT
      LAYER M5 ;
        RECT  107.76 172.716 107.784 172.8 ;
    END
  END rw_x[47]
  PIN rw_x[48]
    DIRECTION INPUT ;
    USE SIGNAL ;
    PORT
      LAYER M5 ;
        RECT  107.856 172.716 107.88 172.8 ;
    END
  END rw_x[48]
  PIN rw_x[49]
    DIRECTION INPUT ;
    USE SIGNAL ;
    PORT
      LAYER M5 ;
        RECT  107.952 172.716 107.976 172.8 ;
    END
  END rw_x[49]
  PIN rw_x[4]
    DIRECTION INPUT ;
    USE SIGNAL ;
    PORT
      LAYER M5 ;
        RECT  132.048 172.716 132.072 172.8 ;
    END
  END rw_x[4]
  PIN rw_x[50]
    DIRECTION INPUT ;
    USE SIGNAL ;
    PORT
      LAYER M5 ;
        RECT  108.048 172.716 108.072 172.8 ;
    END
  END rw_x[50]
  PIN rw_x[51]
    DIRECTION INPUT ;
    USE SIGNAL ;
    PORT
      LAYER M5 ;
        RECT  108.144 172.716 108.168 172.8 ;
    END
  END rw_x[51]
  PIN rw_x[52]
    DIRECTION INPUT ;
    USE SIGNAL ;
    PORT
      LAYER M5 ;
        RECT  108.24 172.716 108.264 172.8 ;
    END
  END rw_x[52]
  PIN rw_x[53]
    DIRECTION INPUT ;
    USE SIGNAL ;
    PORT
      LAYER M5 ;
        RECT  108.336 172.716 108.36 172.8 ;
    END
  END rw_x[53]
  PIN rw_x[54]
    DIRECTION INPUT ;
    USE SIGNAL ;
    PORT
      LAYER M5 ;
        RECT  108.432 172.716 108.456 172.8 ;
    END
  END rw_x[54]
  PIN rw_x[55]
    DIRECTION INPUT ;
    USE SIGNAL ;
    PORT
      LAYER M5 ;
        RECT  108.528 172.716 108.552 172.8 ;
    END
  END rw_x[55]
  PIN rw_x[56]
    DIRECTION INPUT ;
    USE SIGNAL ;
    PORT
      LAYER M5 ;
        RECT  108.624 172.716 108.648 172.8 ;
    END
  END rw_x[56]
  PIN rw_x[57]
    DIRECTION INPUT ;
    USE SIGNAL ;
    PORT
      LAYER M5 ;
        RECT  108.72 172.716 108.744 172.8 ;
    END
  END rw_x[57]
  PIN rw_x[58]
    DIRECTION INPUT ;
    USE SIGNAL ;
    PORT
      LAYER M5 ;
        RECT  108.816 172.716 108.84 172.8 ;
    END
  END rw_x[58]
  PIN rw_x[59]
    DIRECTION INPUT ;
    USE SIGNAL ;
    PORT
      LAYER M5 ;
        RECT  108.912 172.716 108.936 172.8 ;
    END
  END rw_x[59]
  PIN rw_x[5]
    DIRECTION INPUT ;
    USE SIGNAL ;
    PORT
      LAYER M5 ;
        RECT  132.144 172.716 132.168 172.8 ;
    END
  END rw_x[5]
  PIN rw_x[60]
    DIRECTION INPUT ;
    USE SIGNAL ;
    PORT
      LAYER M5 ;
        RECT  109.008 172.716 109.032 172.8 ;
    END
  END rw_x[60]
  PIN rw_x[61]
    DIRECTION INPUT ;
    USE SIGNAL ;
    PORT
      LAYER M5 ;
        RECT  109.104 172.716 109.128 172.8 ;
    END
  END rw_x[61]
  PIN rw_x[62]
    DIRECTION INPUT ;
    USE SIGNAL ;
    PORT
      LAYER M5 ;
        RECT  109.2 172.716 109.224 172.8 ;
    END
  END rw_x[62]
  PIN rw_x[63]
    DIRECTION INPUT ;
    USE SIGNAL ;
    PORT
      LAYER M5 ;
        RECT  109.296 172.716 109.32 172.8 ;
    END
  END rw_x[63]
  PIN rw_x[64]
    DIRECTION INPUT ;
    USE SIGNAL ;
    PORT
      LAYER M5 ;
        RECT  109.392 172.716 109.416 172.8 ;
    END
  END rw_x[64]
  PIN rw_x[65]
    DIRECTION INPUT ;
    USE SIGNAL ;
    PORT
      LAYER M5 ;
        RECT  109.488 172.716 109.512 172.8 ;
    END
  END rw_x[65]
  PIN rw_x[66]
    DIRECTION INPUT ;
    USE SIGNAL ;
    PORT
      LAYER M5 ;
        RECT  109.584 172.716 109.608 172.8 ;
    END
  END rw_x[66]
  PIN rw_x[67]
    DIRECTION INPUT ;
    USE SIGNAL ;
    PORT
      LAYER M5 ;
        RECT  109.68 172.716 109.704 172.8 ;
    END
  END rw_x[67]
  PIN rw_x[68]
    DIRECTION INPUT ;
    USE SIGNAL ;
    PORT
      LAYER M5 ;
        RECT  109.776 172.716 109.8 172.8 ;
    END
  END rw_x[68]
  PIN rw_x[69]
    DIRECTION INPUT ;
    USE SIGNAL ;
    PORT
      LAYER M5 ;
        RECT  109.872 172.716 109.896 172.8 ;
    END
  END rw_x[69]
  PIN rw_x[6]
    DIRECTION INPUT ;
    USE SIGNAL ;
    PORT
      LAYER M5 ;
        RECT  132.24 172.716 132.264 172.8 ;
    END
  END rw_x[6]
  PIN rw_x[70]
    DIRECTION INPUT ;
    USE SIGNAL ;
    PORT
      LAYER M5 ;
        RECT  109.968 172.716 109.992 172.8 ;
    END
  END rw_x[70]
  PIN rw_x[71]
    DIRECTION INPUT ;
    USE SIGNAL ;
    PORT
      LAYER M5 ;
        RECT  110.064 172.716 110.088 172.8 ;
    END
  END rw_x[71]
  PIN rw_x[72]
    DIRECTION INPUT ;
    USE SIGNAL ;
    PORT
      LAYER M5 ;
        RECT  110.16 172.716 110.184 172.8 ;
    END
  END rw_x[72]
  PIN rw_x[73]
    DIRECTION INPUT ;
    USE SIGNAL ;
    PORT
      LAYER M5 ;
        RECT  110.256 172.716 110.28 172.8 ;
    END
  END rw_x[73]
  PIN rw_x[74]
    DIRECTION INPUT ;
    USE SIGNAL ;
    PORT
      LAYER M5 ;
        RECT  110.352 172.716 110.376 172.8 ;
    END
  END rw_x[74]
  PIN rw_x[75]
    DIRECTION INPUT ;
    USE SIGNAL ;
    PORT
      LAYER M5 ;
        RECT  110.448 172.716 110.472 172.8 ;
    END
  END rw_x[75]
  PIN rw_x[76]
    DIRECTION INPUT ;
    USE SIGNAL ;
    PORT
      LAYER M5 ;
        RECT  110.544 172.716 110.568 172.8 ;
    END
  END rw_x[76]
  PIN rw_x[77]
    DIRECTION INPUT ;
    USE SIGNAL ;
    PORT
      LAYER M5 ;
        RECT  110.64 172.716 110.664 172.8 ;
    END
  END rw_x[77]
  PIN rw_x[78]
    DIRECTION INPUT ;
    USE SIGNAL ;
    PORT
      LAYER M5 ;
        RECT  110.736 172.716 110.76 172.8 ;
    END
  END rw_x[78]
  PIN rw_x[79]
    DIRECTION INPUT ;
    USE SIGNAL ;
    PORT
      LAYER M5 ;
        RECT  110.832 172.716 110.856 172.8 ;
    END
  END rw_x[79]
  PIN rw_x[7]
    DIRECTION INPUT ;
    USE SIGNAL ;
    PORT
      LAYER M5 ;
        RECT  132.336 172.716 132.36 172.8 ;
    END
  END rw_x[7]
  PIN rw_x[80]
    DIRECTION INPUT ;
    USE SIGNAL ;
    PORT
      LAYER M5 ;
        RECT  110.928 172.716 110.952 172.8 ;
    END
  END rw_x[80]
  PIN rw_x[81]
    DIRECTION INPUT ;
    USE SIGNAL ;
    PORT
      LAYER M5 ;
        RECT  111.024 172.716 111.048 172.8 ;
    END
  END rw_x[81]
  PIN rw_x[82]
    DIRECTION INPUT ;
    USE SIGNAL ;
    PORT
      LAYER M5 ;
        RECT  111.12 172.716 111.144 172.8 ;
    END
  END rw_x[82]
  PIN rw_x[83]
    DIRECTION INPUT ;
    USE SIGNAL ;
    PORT
      LAYER M5 ;
        RECT  111.216 172.716 111.24 172.8 ;
    END
  END rw_x[83]
  PIN rw_x[84]
    DIRECTION INPUT ;
    USE SIGNAL ;
    PORT
      LAYER M5 ;
        RECT  111.312 172.716 111.336 172.8 ;
    END
  END rw_x[84]
  PIN rw_x[85]
    DIRECTION INPUT ;
    USE SIGNAL ;
    PORT
      LAYER M5 ;
        RECT  111.408 172.716 111.432 172.8 ;
    END
  END rw_x[85]
  PIN rw_x[86]
    DIRECTION INPUT ;
    USE SIGNAL ;
    PORT
      LAYER M5 ;
        RECT  111.504 172.716 111.528 172.8 ;
    END
  END rw_x[86]
  PIN rw_x[87]
    DIRECTION INPUT ;
    USE SIGNAL ;
    PORT
      LAYER M5 ;
        RECT  111.6 172.716 111.624 172.8 ;
    END
  END rw_x[87]
  PIN rw_x[88]
    DIRECTION INPUT ;
    USE SIGNAL ;
    PORT
      LAYER M5 ;
        RECT  111.696 172.716 111.72 172.8 ;
    END
  END rw_x[88]
  PIN rw_x[89]
    DIRECTION INPUT ;
    USE SIGNAL ;
    PORT
      LAYER M5 ;
        RECT  111.792 172.716 111.816 172.8 ;
    END
  END rw_x[89]
  PIN rw_x[8]
    DIRECTION INPUT ;
    USE SIGNAL ;
    PORT
      LAYER M5 ;
        RECT  132.432 172.716 132.456 172.8 ;
    END
  END rw_x[8]
  PIN rw_x[90]
    DIRECTION INPUT ;
    USE SIGNAL ;
    PORT
      LAYER M5 ;
        RECT  111.888 172.716 111.912 172.8 ;
    END
  END rw_x[90]
  PIN rw_x[91]
    DIRECTION INPUT ;
    USE SIGNAL ;
    PORT
      LAYER M5 ;
        RECT  111.984 172.716 112.008 172.8 ;
    END
  END rw_x[91]
  PIN rw_x[92]
    DIRECTION INPUT ;
    USE SIGNAL ;
    PORT
      LAYER M5 ;
        RECT  112.08 172.716 112.104 172.8 ;
    END
  END rw_x[92]
  PIN rw_x[93]
    DIRECTION INPUT ;
    USE SIGNAL ;
    PORT
      LAYER M5 ;
        RECT  112.176 172.716 112.2 172.8 ;
    END
  END rw_x[93]
  PIN rw_x[94]
    DIRECTION INPUT ;
    USE SIGNAL ;
    PORT
      LAYER M5 ;
        RECT  112.272 172.716 112.296 172.8 ;
    END
  END rw_x[94]
  PIN rw_x[95]
    DIRECTION INPUT ;
    USE SIGNAL ;
    PORT
      LAYER M5 ;
        RECT  112.368 172.716 112.392 172.8 ;
    END
  END rw_x[95]
  PIN rw_x[96]
    DIRECTION INPUT ;
    USE SIGNAL ;
    PORT
      LAYER M5 ;
        RECT  112.464 172.716 112.488 172.8 ;
    END
  END rw_x[96]
  PIN rw_x[97]
    DIRECTION INPUT ;
    USE SIGNAL ;
    PORT
      LAYER M5 ;
        RECT  112.56 172.716 112.584 172.8 ;
    END
  END rw_x[97]
  PIN rw_x[98]
    DIRECTION INPUT ;
    USE SIGNAL ;
    PORT
      LAYER M5 ;
        RECT  112.656 172.716 112.68 172.8 ;
    END
  END rw_x[98]
  PIN rw_x[99]
    DIRECTION INPUT ;
    USE SIGNAL ;
    PORT
      LAYER M5 ;
        RECT  112.752 172.716 112.776 172.8 ;
    END
  END rw_x[99]
  PIN rw_x[9]
    DIRECTION INPUT ;
    USE SIGNAL ;
    PORT
      LAYER M5 ;
        RECT  132.528 172.716 132.552 172.8 ;
    END
  END rw_x[9]
  PIN sid_i[0]
    DIRECTION INPUT ;
    USE SIGNAL ;
    PORT
      LAYER M5 ;
        RECT  147.792 172.716 147.816 172.8 ;
    END
  END sid_i[0]
  PIN sid_i[1]
    DIRECTION INPUT ;
    USE SIGNAL ;
    PORT
      LAYER M5 ;
        RECT  147.888 172.716 147.912 172.8 ;
    END
  END sid_i[1]
  PIN sid_i[2]
    DIRECTION INPUT ;
    USE SIGNAL ;
    PORT
      LAYER M5 ;
        RECT  147.984 172.716 148.008 172.8 ;
    END
  END sid_i[2]
  PIN sid_i[3]
    DIRECTION INPUT ;
    USE SIGNAL ;
    PORT
      LAYER M5 ;
        RECT  148.08 172.716 148.104 172.8 ;
    END
  END sid_i[3]
  PIN vi_s[0]
    DIRECTION INPUT ;
    USE SIGNAL ;
    PORT
      LAYER M5 ;
        RECT  318.96 0 318.984 0.084 ;
    END
  END vi_s[0]
  PIN vi_s[100]
    DIRECTION INPUT ;
    USE SIGNAL ;
    PORT
      LAYER M5 ;
        RECT  328.56 0 328.584 0.084 ;
    END
  END vi_s[100]
  PIN vi_s[101]
    DIRECTION INPUT ;
    USE SIGNAL ;
    PORT
      LAYER M5 ;
        RECT  328.656 0 328.68 0.084 ;
    END
  END vi_s[101]
  PIN vi_s[102]
    DIRECTION INPUT ;
    USE SIGNAL ;
    PORT
      LAYER M5 ;
        RECT  328.752 0 328.776 0.084 ;
    END
  END vi_s[102]
  PIN vi_s[103]
    DIRECTION INPUT ;
    USE SIGNAL ;
    PORT
      LAYER M5 ;
        RECT  328.848 0 328.872 0.084 ;
    END
  END vi_s[103]
  PIN vi_s[104]
    DIRECTION INPUT ;
    USE SIGNAL ;
    PORT
      LAYER M5 ;
        RECT  328.944 0 328.968 0.084 ;
    END
  END vi_s[104]
  PIN vi_s[105]
    DIRECTION INPUT ;
    USE SIGNAL ;
    PORT
      LAYER M5 ;
        RECT  329.04 0 329.064 0.084 ;
    END
  END vi_s[105]
  PIN vi_s[106]
    DIRECTION INPUT ;
    USE SIGNAL ;
    PORT
      LAYER M5 ;
        RECT  329.136 0 329.16 0.084 ;
    END
  END vi_s[106]
  PIN vi_s[107]
    DIRECTION INPUT ;
    USE SIGNAL ;
    PORT
      LAYER M5 ;
        RECT  329.232 0 329.256 0.084 ;
    END
  END vi_s[107]
  PIN vi_s[108]
    DIRECTION INPUT ;
    USE SIGNAL ;
    PORT
      LAYER M5 ;
        RECT  329.328 0 329.352 0.084 ;
    END
  END vi_s[108]
  PIN vi_s[109]
    DIRECTION INPUT ;
    USE SIGNAL ;
    PORT
      LAYER M5 ;
        RECT  329.424 0 329.448 0.084 ;
    END
  END vi_s[109]
  PIN vi_s[10]
    DIRECTION INPUT ;
    USE SIGNAL ;
    PORT
      LAYER M5 ;
        RECT  319.92 0 319.944 0.084 ;
    END
  END vi_s[10]
  PIN vi_s[110]
    DIRECTION INPUT ;
    USE SIGNAL ;
    PORT
      LAYER M5 ;
        RECT  329.52 0 329.544 0.084 ;
    END
  END vi_s[110]
  PIN vi_s[111]
    DIRECTION INPUT ;
    USE SIGNAL ;
    PORT
      LAYER M5 ;
        RECT  329.616 0 329.64 0.084 ;
    END
  END vi_s[111]
  PIN vi_s[112]
    DIRECTION INPUT ;
    USE SIGNAL ;
    PORT
      LAYER M5 ;
        RECT  329.712 0 329.736 0.084 ;
    END
  END vi_s[112]
  PIN vi_s[113]
    DIRECTION INPUT ;
    USE SIGNAL ;
    PORT
      LAYER M5 ;
        RECT  329.808 0 329.832 0.084 ;
    END
  END vi_s[113]
  PIN vi_s[114]
    DIRECTION INPUT ;
    USE SIGNAL ;
    PORT
      LAYER M5 ;
        RECT  329.904 0 329.928 0.084 ;
    END
  END vi_s[114]
  PIN vi_s[115]
    DIRECTION INPUT ;
    USE SIGNAL ;
    PORT
      LAYER M5 ;
        RECT  330 0 330.024 0.084 ;
    END
  END vi_s[115]
  PIN vi_s[116]
    DIRECTION INPUT ;
    USE SIGNAL ;
    PORT
      LAYER M5 ;
        RECT  330.096 0 330.12 0.084 ;
    END
  END vi_s[116]
  PIN vi_s[117]
    DIRECTION INPUT ;
    USE SIGNAL ;
    PORT
      LAYER M5 ;
        RECT  330.192 0 330.216 0.084 ;
    END
  END vi_s[117]
  PIN vi_s[118]
    DIRECTION INPUT ;
    USE SIGNAL ;
    PORT
      LAYER M5 ;
        RECT  330.288 0 330.312 0.084 ;
    END
  END vi_s[118]
  PIN vi_s[119]
    DIRECTION INPUT ;
    USE SIGNAL ;
    PORT
      LAYER M5 ;
        RECT  330.384 0 330.408 0.084 ;
    END
  END vi_s[119]
  PIN vi_s[11]
    DIRECTION INPUT ;
    USE SIGNAL ;
    PORT
      LAYER M5 ;
        RECT  320.016 0 320.04 0.084 ;
    END
  END vi_s[11]
  PIN vi_s[120]
    DIRECTION INPUT ;
    USE SIGNAL ;
    PORT
      LAYER M5 ;
        RECT  330.48 0 330.504 0.084 ;
    END
  END vi_s[120]
  PIN vi_s[121]
    DIRECTION INPUT ;
    USE SIGNAL ;
    PORT
      LAYER M5 ;
        RECT  330.576 0 330.6 0.084 ;
    END
  END vi_s[121]
  PIN vi_s[122]
    DIRECTION INPUT ;
    USE SIGNAL ;
    PORT
      LAYER M5 ;
        RECT  330.672 0 330.696 0.084 ;
    END
  END vi_s[122]
  PIN vi_s[123]
    DIRECTION INPUT ;
    USE SIGNAL ;
    PORT
      LAYER M5 ;
        RECT  330.768 0 330.792 0.084 ;
    END
  END vi_s[123]
  PIN vi_s[124]
    DIRECTION INPUT ;
    USE SIGNAL ;
    PORT
      LAYER M5 ;
        RECT  330.864 0 330.888 0.084 ;
    END
  END vi_s[124]
  PIN vi_s[125]
    DIRECTION INPUT ;
    USE SIGNAL ;
    PORT
      LAYER M5 ;
        RECT  330.96 0 330.984 0.084 ;
    END
  END vi_s[125]
  PIN vi_s[126]
    DIRECTION INPUT ;
    USE SIGNAL ;
    PORT
      LAYER M5 ;
        RECT  331.056 0 331.08 0.084 ;
    END
  END vi_s[126]
  PIN vi_s[127]
    DIRECTION INPUT ;
    USE SIGNAL ;
    PORT
      LAYER M5 ;
        RECT  331.152 0 331.176 0.084 ;
    END
  END vi_s[127]
  PIN vi_s[128]
    DIRECTION INPUT ;
    USE SIGNAL ;
    PORT
      LAYER M5 ;
        RECT  331.248 0 331.272 0.084 ;
    END
  END vi_s[128]
  PIN vi_s[129]
    DIRECTION INPUT ;
    USE SIGNAL ;
    PORT
      LAYER M5 ;
        RECT  331.344 0 331.368 0.084 ;
    END
  END vi_s[129]
  PIN vi_s[12]
    DIRECTION INPUT ;
    USE SIGNAL ;
    PORT
      LAYER M5 ;
        RECT  320.112 0 320.136 0.084 ;
    END
  END vi_s[12]
  PIN vi_s[130]
    DIRECTION INPUT ;
    USE SIGNAL ;
    PORT
      LAYER M5 ;
        RECT  331.44 0 331.464 0.084 ;
    END
  END vi_s[130]
  PIN vi_s[131]
    DIRECTION INPUT ;
    USE SIGNAL ;
    PORT
      LAYER M5 ;
        RECT  331.536 0 331.56 0.084 ;
    END
  END vi_s[131]
  PIN vi_s[132]
    DIRECTION INPUT ;
    USE SIGNAL ;
    PORT
      LAYER M5 ;
        RECT  331.632 0 331.656 0.084 ;
    END
  END vi_s[132]
  PIN vi_s[133]
    DIRECTION INPUT ;
    USE SIGNAL ;
    PORT
      LAYER M5 ;
        RECT  331.728 0 331.752 0.084 ;
    END
  END vi_s[133]
  PIN vi_s[134]
    DIRECTION INPUT ;
    USE SIGNAL ;
    PORT
      LAYER M5 ;
        RECT  331.824 0 331.848 0.084 ;
    END
  END vi_s[134]
  PIN vi_s[135]
    DIRECTION INPUT ;
    USE SIGNAL ;
    PORT
      LAYER M5 ;
        RECT  331.92 0 331.944 0.084 ;
    END
  END vi_s[135]
  PIN vi_s[136]
    DIRECTION INPUT ;
    USE SIGNAL ;
    PORT
      LAYER M5 ;
        RECT  332.016 0 332.04 0.084 ;
    END
  END vi_s[136]
  PIN vi_s[137]
    DIRECTION INPUT ;
    USE SIGNAL ;
    PORT
      LAYER M5 ;
        RECT  332.112 0 332.136 0.084 ;
    END
  END vi_s[137]
  PIN vi_s[138]
    DIRECTION INPUT ;
    USE SIGNAL ;
    PORT
      LAYER M5 ;
        RECT  332.208 0 332.232 0.084 ;
    END
  END vi_s[138]
  PIN vi_s[139]
    DIRECTION INPUT ;
    USE SIGNAL ;
    PORT
      LAYER M5 ;
        RECT  332.304 0 332.328 0.084 ;
    END
  END vi_s[139]
  PIN vi_s[13]
    DIRECTION INPUT ;
    USE SIGNAL ;
    PORT
      LAYER M5 ;
        RECT  320.208 0 320.232 0.084 ;
    END
  END vi_s[13]
  PIN vi_s[140]
    DIRECTION INPUT ;
    USE SIGNAL ;
    PORT
      LAYER M5 ;
        RECT  332.4 0 332.424 0.084 ;
    END
  END vi_s[140]
  PIN vi_s[141]
    DIRECTION INPUT ;
    USE SIGNAL ;
    PORT
      LAYER M5 ;
        RECT  332.496 0 332.52 0.084 ;
    END
  END vi_s[141]
  PIN vi_s[142]
    DIRECTION INPUT ;
    USE SIGNAL ;
    PORT
      LAYER M5 ;
        RECT  332.592 0 332.616 0.084 ;
    END
  END vi_s[142]
  PIN vi_s[143]
    DIRECTION INPUT ;
    USE SIGNAL ;
    PORT
      LAYER M5 ;
        RECT  332.688 0 332.712 0.084 ;
    END
  END vi_s[143]
  PIN vi_s[144]
    DIRECTION INPUT ;
    USE SIGNAL ;
    PORT
      LAYER M5 ;
        RECT  332.784 0 332.808 0.084 ;
    END
  END vi_s[144]
  PIN vi_s[145]
    DIRECTION INPUT ;
    USE SIGNAL ;
    PORT
      LAYER M5 ;
        RECT  332.88 0 332.904 0.084 ;
    END
  END vi_s[145]
  PIN vi_s[146]
    DIRECTION INPUT ;
    USE SIGNAL ;
    PORT
      LAYER M5 ;
        RECT  332.976 0 333 0.084 ;
    END
  END vi_s[146]
  PIN vi_s[147]
    DIRECTION INPUT ;
    USE SIGNAL ;
    PORT
      LAYER M5 ;
        RECT  333.072 0 333.096 0.084 ;
    END
  END vi_s[147]
  PIN vi_s[148]
    DIRECTION INPUT ;
    USE SIGNAL ;
    PORT
      LAYER M5 ;
        RECT  333.168 0 333.192 0.084 ;
    END
  END vi_s[148]
  PIN vi_s[149]
    DIRECTION INPUT ;
    USE SIGNAL ;
    PORT
      LAYER M5 ;
        RECT  333.264 0 333.288 0.084 ;
    END
  END vi_s[149]
  PIN vi_s[14]
    DIRECTION INPUT ;
    USE SIGNAL ;
    PORT
      LAYER M5 ;
        RECT  320.304 0 320.328 0.084 ;
    END
  END vi_s[14]
  PIN vi_s[150]
    DIRECTION INPUT ;
    USE SIGNAL ;
    PORT
      LAYER M5 ;
        RECT  333.36 0 333.384 0.084 ;
    END
  END vi_s[150]
  PIN vi_s[151]
    DIRECTION INPUT ;
    USE SIGNAL ;
    PORT
      LAYER M5 ;
        RECT  333.456 0 333.48 0.084 ;
    END
  END vi_s[151]
  PIN vi_s[152]
    DIRECTION INPUT ;
    USE SIGNAL ;
    PORT
      LAYER M5 ;
        RECT  333.552 0 333.576 0.084 ;
    END
  END vi_s[152]
  PIN vi_s[153]
    DIRECTION INPUT ;
    USE SIGNAL ;
    PORT
      LAYER M5 ;
        RECT  333.648 0 333.672 0.084 ;
    END
  END vi_s[153]
  PIN vi_s[154]
    DIRECTION INPUT ;
    USE SIGNAL ;
    PORT
      LAYER M5 ;
        RECT  333.744 0 333.768 0.084 ;
    END
  END vi_s[154]
  PIN vi_s[155]
    DIRECTION INPUT ;
    USE SIGNAL ;
    PORT
      LAYER M5 ;
        RECT  333.84 0 333.864 0.084 ;
    END
  END vi_s[155]
  PIN vi_s[156]
    DIRECTION INPUT ;
    USE SIGNAL ;
    PORT
      LAYER M5 ;
        RECT  333.936 0 333.96 0.084 ;
    END
  END vi_s[156]
  PIN vi_s[157]
    DIRECTION INPUT ;
    USE SIGNAL ;
    PORT
      LAYER M5 ;
        RECT  334.032 0 334.056 0.084 ;
    END
  END vi_s[157]
  PIN vi_s[158]
    DIRECTION INPUT ;
    USE SIGNAL ;
    PORT
      LAYER M5 ;
        RECT  334.128 0 334.152 0.084 ;
    END
  END vi_s[158]
  PIN vi_s[159]
    DIRECTION INPUT ;
    USE SIGNAL ;
    PORT
      LAYER M5 ;
        RECT  334.224 0 334.248 0.084 ;
    END
  END vi_s[159]
  PIN vi_s[15]
    DIRECTION INPUT ;
    USE SIGNAL ;
    PORT
      LAYER M5 ;
        RECT  320.4 0 320.424 0.084 ;
    END
  END vi_s[15]
  PIN vi_s[160]
    DIRECTION INPUT ;
    USE SIGNAL ;
    PORT
      LAYER M5 ;
        RECT  334.32 0 334.344 0.084 ;
    END
  END vi_s[160]
  PIN vi_s[161]
    DIRECTION INPUT ;
    USE SIGNAL ;
    PORT
      LAYER M5 ;
        RECT  334.416 0 334.44 0.084 ;
    END
  END vi_s[161]
  PIN vi_s[162]
    DIRECTION INPUT ;
    USE SIGNAL ;
    PORT
      LAYER M5 ;
        RECT  334.512 0 334.536 0.084 ;
    END
  END vi_s[162]
  PIN vi_s[163]
    DIRECTION INPUT ;
    USE SIGNAL ;
    PORT
      LAYER M5 ;
        RECT  334.608 0 334.632 0.084 ;
    END
  END vi_s[163]
  PIN vi_s[164]
    DIRECTION INPUT ;
    USE SIGNAL ;
    PORT
      LAYER M5 ;
        RECT  334.704 0 334.728 0.084 ;
    END
  END vi_s[164]
  PIN vi_s[165]
    DIRECTION INPUT ;
    USE SIGNAL ;
    PORT
      LAYER M5 ;
        RECT  334.8 0 334.824 0.084 ;
    END
  END vi_s[165]
  PIN vi_s[166]
    DIRECTION INPUT ;
    USE SIGNAL ;
    PORT
      LAYER M5 ;
        RECT  334.896 0 334.92 0.084 ;
    END
  END vi_s[166]
  PIN vi_s[167]
    DIRECTION INPUT ;
    USE SIGNAL ;
    PORT
      LAYER M5 ;
        RECT  334.992 0 335.016 0.084 ;
    END
  END vi_s[167]
  PIN vi_s[168]
    DIRECTION INPUT ;
    USE SIGNAL ;
    PORT
      LAYER M5 ;
        RECT  335.088 0 335.112 0.084 ;
    END
  END vi_s[168]
  PIN vi_s[169]
    DIRECTION INPUT ;
    USE SIGNAL ;
    PORT
      LAYER M5 ;
        RECT  335.184 0 335.208 0.084 ;
    END
  END vi_s[169]
  PIN vi_s[16]
    DIRECTION INPUT ;
    USE SIGNAL ;
    PORT
      LAYER M5 ;
        RECT  320.496 0 320.52 0.084 ;
    END
  END vi_s[16]
  PIN vi_s[170]
    DIRECTION INPUT ;
    USE SIGNAL ;
    PORT
      LAYER M5 ;
        RECT  335.28 0 335.304 0.084 ;
    END
  END vi_s[170]
  PIN vi_s[171]
    DIRECTION INPUT ;
    USE SIGNAL ;
    PORT
      LAYER M5 ;
        RECT  335.376 0 335.4 0.084 ;
    END
  END vi_s[171]
  PIN vi_s[172]
    DIRECTION INPUT ;
    USE SIGNAL ;
    PORT
      LAYER M5 ;
        RECT  335.472 0 335.496 0.084 ;
    END
  END vi_s[172]
  PIN vi_s[173]
    DIRECTION INPUT ;
    USE SIGNAL ;
    PORT
      LAYER M5 ;
        RECT  335.568 0 335.592 0.084 ;
    END
  END vi_s[173]
  PIN vi_s[174]
    DIRECTION INPUT ;
    USE SIGNAL ;
    PORT
      LAYER M5 ;
        RECT  335.664 0 335.688 0.084 ;
    END
  END vi_s[174]
  PIN vi_s[175]
    DIRECTION INPUT ;
    USE SIGNAL ;
    PORT
      LAYER M5 ;
        RECT  335.76 0 335.784 0.084 ;
    END
  END vi_s[175]
  PIN vi_s[176]
    DIRECTION INPUT ;
    USE SIGNAL ;
    PORT
      LAYER M5 ;
        RECT  335.856 0 335.88 0.084 ;
    END
  END vi_s[176]
  PIN vi_s[177]
    DIRECTION INPUT ;
    USE SIGNAL ;
    PORT
      LAYER M5 ;
        RECT  335.952 0 335.976 0.084 ;
    END
  END vi_s[177]
  PIN vi_s[178]
    DIRECTION INPUT ;
    USE SIGNAL ;
    PORT
      LAYER M5 ;
        RECT  336.048 0 336.072 0.084 ;
    END
  END vi_s[178]
  PIN vi_s[179]
    DIRECTION INPUT ;
    USE SIGNAL ;
    PORT
      LAYER M5 ;
        RECT  336.144 0 336.168 0.084 ;
    END
  END vi_s[179]
  PIN vi_s[17]
    DIRECTION INPUT ;
    USE SIGNAL ;
    PORT
      LAYER M5 ;
        RECT  320.592 0 320.616 0.084 ;
    END
  END vi_s[17]
  PIN vi_s[180]
    DIRECTION INPUT ;
    USE SIGNAL ;
    PORT
      LAYER M5 ;
        RECT  336.24 0 336.264 0.084 ;
    END
  END vi_s[180]
  PIN vi_s[181]
    DIRECTION INPUT ;
    USE SIGNAL ;
    PORT
      LAYER M5 ;
        RECT  336.336 0 336.36 0.084 ;
    END
  END vi_s[181]
  PIN vi_s[182]
    DIRECTION INPUT ;
    USE SIGNAL ;
    PORT
      LAYER M5 ;
        RECT  336.432 0 336.456 0.084 ;
    END
  END vi_s[182]
  PIN vi_s[183]
    DIRECTION INPUT ;
    USE SIGNAL ;
    PORT
      LAYER M5 ;
        RECT  336.528 0 336.552 0.084 ;
    END
  END vi_s[183]
  PIN vi_s[184]
    DIRECTION INPUT ;
    USE SIGNAL ;
    PORT
      LAYER M5 ;
        RECT  336.624 0 336.648 0.084 ;
    END
  END vi_s[184]
  PIN vi_s[185]
    DIRECTION INPUT ;
    USE SIGNAL ;
    PORT
      LAYER M5 ;
        RECT  336.72 0 336.744 0.084 ;
    END
  END vi_s[185]
  PIN vi_s[186]
    DIRECTION INPUT ;
    USE SIGNAL ;
    PORT
      LAYER M5 ;
        RECT  336.816 0 336.84 0.084 ;
    END
  END vi_s[186]
  PIN vi_s[187]
    DIRECTION INPUT ;
    USE SIGNAL ;
    PORT
      LAYER M5 ;
        RECT  336.912 0 336.936 0.084 ;
    END
  END vi_s[187]
  PIN vi_s[188]
    DIRECTION INPUT ;
    USE SIGNAL ;
    PORT
      LAYER M5 ;
        RECT  337.008 0 337.032 0.084 ;
    END
  END vi_s[188]
  PIN vi_s[189]
    DIRECTION INPUT ;
    USE SIGNAL ;
    PORT
      LAYER M5 ;
        RECT  337.104 0 337.128 0.084 ;
    END
  END vi_s[189]
  PIN vi_s[18]
    DIRECTION INPUT ;
    USE SIGNAL ;
    PORT
      LAYER M5 ;
        RECT  320.688 0 320.712 0.084 ;
    END
  END vi_s[18]
  PIN vi_s[190]
    DIRECTION INPUT ;
    USE SIGNAL ;
    PORT
      LAYER M5 ;
        RECT  337.2 0 337.224 0.084 ;
    END
  END vi_s[190]
  PIN vi_s[191]
    DIRECTION INPUT ;
    USE SIGNAL ;
    PORT
      LAYER M5 ;
        RECT  337.296 0 337.32 0.084 ;
    END
  END vi_s[191]
  PIN vi_s[192]
    DIRECTION INPUT ;
    USE SIGNAL ;
    PORT
      LAYER M5 ;
        RECT  337.392 0 337.416 0.084 ;
    END
  END vi_s[192]
  PIN vi_s[193]
    DIRECTION INPUT ;
    USE SIGNAL ;
    PORT
      LAYER M5 ;
        RECT  337.488 0 337.512 0.084 ;
    END
  END vi_s[193]
  PIN vi_s[194]
    DIRECTION INPUT ;
    USE SIGNAL ;
    PORT
      LAYER M5 ;
        RECT  337.584 0 337.608 0.084 ;
    END
  END vi_s[194]
  PIN vi_s[195]
    DIRECTION INPUT ;
    USE SIGNAL ;
    PORT
      LAYER M5 ;
        RECT  337.68 0 337.704 0.084 ;
    END
  END vi_s[195]
  PIN vi_s[196]
    DIRECTION INPUT ;
    USE SIGNAL ;
    PORT
      LAYER M5 ;
        RECT  337.776 0 337.8 0.084 ;
    END
  END vi_s[196]
  PIN vi_s[197]
    DIRECTION INPUT ;
    USE SIGNAL ;
    PORT
      LAYER M5 ;
        RECT  337.872 0 337.896 0.084 ;
    END
  END vi_s[197]
  PIN vi_s[198]
    DIRECTION INPUT ;
    USE SIGNAL ;
    PORT
      LAYER M5 ;
        RECT  337.968 0 337.992 0.084 ;
    END
  END vi_s[198]
  PIN vi_s[199]
    DIRECTION INPUT ;
    USE SIGNAL ;
    PORT
      LAYER M5 ;
        RECT  338.064 0 338.088 0.084 ;
    END
  END vi_s[199]
  PIN vi_s[19]
    DIRECTION INPUT ;
    USE SIGNAL ;
    PORT
      LAYER M5 ;
        RECT  320.784 0 320.808 0.084 ;
    END
  END vi_s[19]
  PIN vi_s[1]
    DIRECTION INPUT ;
    USE SIGNAL ;
    PORT
      LAYER M5 ;
        RECT  319.056 0 319.08 0.084 ;
    END
  END vi_s[1]
  PIN vi_s[200]
    DIRECTION INPUT ;
    USE SIGNAL ;
    PORT
      LAYER M5 ;
        RECT  338.16 0 338.184 0.084 ;
    END
  END vi_s[200]
  PIN vi_s[201]
    DIRECTION INPUT ;
    USE SIGNAL ;
    PORT
      LAYER M5 ;
        RECT  338.256 0 338.28 0.084 ;
    END
  END vi_s[201]
  PIN vi_s[202]
    DIRECTION INPUT ;
    USE SIGNAL ;
    PORT
      LAYER M5 ;
        RECT  338.352 0 338.376 0.084 ;
    END
  END vi_s[202]
  PIN vi_s[203]
    DIRECTION INPUT ;
    USE SIGNAL ;
    PORT
      LAYER M5 ;
        RECT  338.448 0 338.472 0.084 ;
    END
  END vi_s[203]
  PIN vi_s[204]
    DIRECTION INPUT ;
    USE SIGNAL ;
    PORT
      LAYER M5 ;
        RECT  338.544 0 338.568 0.084 ;
    END
  END vi_s[204]
  PIN vi_s[205]
    DIRECTION INPUT ;
    USE SIGNAL ;
    PORT
      LAYER M5 ;
        RECT  338.64 0 338.664 0.084 ;
    END
  END vi_s[205]
  PIN vi_s[206]
    DIRECTION INPUT ;
    USE SIGNAL ;
    PORT
      LAYER M5 ;
        RECT  338.736 0 338.76 0.084 ;
    END
  END vi_s[206]
  PIN vi_s[207]
    DIRECTION INPUT ;
    USE SIGNAL ;
    PORT
      LAYER M5 ;
        RECT  338.832 0 338.856 0.084 ;
    END
  END vi_s[207]
  PIN vi_s[208]
    DIRECTION INPUT ;
    USE SIGNAL ;
    PORT
      LAYER M5 ;
        RECT  338.928 0 338.952 0.084 ;
    END
  END vi_s[208]
  PIN vi_s[209]
    DIRECTION INPUT ;
    USE SIGNAL ;
    PORT
      LAYER M5 ;
        RECT  339.024 0 339.048 0.084 ;
    END
  END vi_s[209]
  PIN vi_s[20]
    DIRECTION INPUT ;
    USE SIGNAL ;
    PORT
      LAYER M5 ;
        RECT  320.88 0 320.904 0.084 ;
    END
  END vi_s[20]
  PIN vi_s[210]
    DIRECTION INPUT ;
    USE SIGNAL ;
    PORT
      LAYER M5 ;
        RECT  339.12 0 339.144 0.084 ;
    END
  END vi_s[210]
  PIN vi_s[211]
    DIRECTION INPUT ;
    USE SIGNAL ;
    PORT
      LAYER M5 ;
        RECT  339.216 0 339.24 0.084 ;
    END
  END vi_s[211]
  PIN vi_s[212]
    DIRECTION INPUT ;
    USE SIGNAL ;
    PORT
      LAYER M5 ;
        RECT  339.312 0 339.336 0.084 ;
    END
  END vi_s[212]
  PIN vi_s[213]
    DIRECTION INPUT ;
    USE SIGNAL ;
    PORT
      LAYER M5 ;
        RECT  339.408 0 339.432 0.084 ;
    END
  END vi_s[213]
  PIN vi_s[214]
    DIRECTION INPUT ;
    USE SIGNAL ;
    PORT
      LAYER M5 ;
        RECT  339.504 0 339.528 0.084 ;
    END
  END vi_s[214]
  PIN vi_s[215]
    DIRECTION INPUT ;
    USE SIGNAL ;
    PORT
      LAYER M5 ;
        RECT  339.6 0 339.624 0.084 ;
    END
  END vi_s[215]
  PIN vi_s[216]
    DIRECTION INPUT ;
    USE SIGNAL ;
    PORT
      LAYER M5 ;
        RECT  339.696 0 339.72 0.084 ;
    END
  END vi_s[216]
  PIN vi_s[217]
    DIRECTION INPUT ;
    USE SIGNAL ;
    PORT
      LAYER M5 ;
        RECT  339.792 0 339.816 0.084 ;
    END
  END vi_s[217]
  PIN vi_s[218]
    DIRECTION INPUT ;
    USE SIGNAL ;
    PORT
      LAYER M5 ;
        RECT  339.888 0 339.912 0.084 ;
    END
  END vi_s[218]
  PIN vi_s[219]
    DIRECTION INPUT ;
    USE SIGNAL ;
    PORT
      LAYER M5 ;
        RECT  339.984 0 340.008 0.084 ;
    END
  END vi_s[219]
  PIN vi_s[21]
    DIRECTION INPUT ;
    USE SIGNAL ;
    PORT
      LAYER M5 ;
        RECT  320.976 0 321 0.084 ;
    END
  END vi_s[21]
  PIN vi_s[220]
    DIRECTION INPUT ;
    USE SIGNAL ;
    PORT
      LAYER M5 ;
        RECT  340.08 0 340.104 0.084 ;
    END
  END vi_s[220]
  PIN vi_s[221]
    DIRECTION INPUT ;
    USE SIGNAL ;
    PORT
      LAYER M5 ;
        RECT  340.176 0 340.2 0.084 ;
    END
  END vi_s[221]
  PIN vi_s[222]
    DIRECTION INPUT ;
    USE SIGNAL ;
    PORT
      LAYER M5 ;
        RECT  340.272 0 340.296 0.084 ;
    END
  END vi_s[222]
  PIN vi_s[223]
    DIRECTION INPUT ;
    USE SIGNAL ;
    PORT
      LAYER M5 ;
        RECT  340.368 0 340.392 0.084 ;
    END
  END vi_s[223]
  PIN vi_s[224]
    DIRECTION INPUT ;
    USE SIGNAL ;
    PORT
      LAYER M5 ;
        RECT  340.464 0 340.488 0.084 ;
    END
  END vi_s[224]
  PIN vi_s[225]
    DIRECTION INPUT ;
    USE SIGNAL ;
    PORT
      LAYER M5 ;
        RECT  340.56 0 340.584 0.084 ;
    END
  END vi_s[225]
  PIN vi_s[226]
    DIRECTION INPUT ;
    USE SIGNAL ;
    PORT
      LAYER M5 ;
        RECT  340.656 0 340.68 0.084 ;
    END
  END vi_s[226]
  PIN vi_s[227]
    DIRECTION INPUT ;
    USE SIGNAL ;
    PORT
      LAYER M5 ;
        RECT  340.752 0 340.776 0.084 ;
    END
  END vi_s[227]
  PIN vi_s[228]
    DIRECTION INPUT ;
    USE SIGNAL ;
    PORT
      LAYER M5 ;
        RECT  340.848 0 340.872 0.084 ;
    END
  END vi_s[228]
  PIN vi_s[229]
    DIRECTION INPUT ;
    USE SIGNAL ;
    PORT
      LAYER M5 ;
        RECT  340.944 0 340.968 0.084 ;
    END
  END vi_s[229]
  PIN vi_s[22]
    DIRECTION INPUT ;
    USE SIGNAL ;
    PORT
      LAYER M5 ;
        RECT  321.072 0 321.096 0.084 ;
    END
  END vi_s[22]
  PIN vi_s[230]
    DIRECTION INPUT ;
    USE SIGNAL ;
    PORT
      LAYER M5 ;
        RECT  341.04 0 341.064 0.084 ;
    END
  END vi_s[230]
  PIN vi_s[231]
    DIRECTION INPUT ;
    USE SIGNAL ;
    PORT
      LAYER M5 ;
        RECT  341.136 0 341.16 0.084 ;
    END
  END vi_s[231]
  PIN vi_s[232]
    DIRECTION INPUT ;
    USE SIGNAL ;
    PORT
      LAYER M5 ;
        RECT  341.232 0 341.256 0.084 ;
    END
  END vi_s[232]
  PIN vi_s[233]
    DIRECTION INPUT ;
    USE SIGNAL ;
    PORT
      LAYER M5 ;
        RECT  341.328 0 341.352 0.084 ;
    END
  END vi_s[233]
  PIN vi_s[234]
    DIRECTION INPUT ;
    USE SIGNAL ;
    PORT
      LAYER M5 ;
        RECT  341.424 0 341.448 0.084 ;
    END
  END vi_s[234]
  PIN vi_s[235]
    DIRECTION INPUT ;
    USE SIGNAL ;
    PORT
      LAYER M5 ;
        RECT  341.52 0 341.544 0.084 ;
    END
  END vi_s[235]
  PIN vi_s[236]
    DIRECTION INPUT ;
    USE SIGNAL ;
    PORT
      LAYER M5 ;
        RECT  341.616 0 341.64 0.084 ;
    END
  END vi_s[236]
  PIN vi_s[237]
    DIRECTION INPUT ;
    USE SIGNAL ;
    PORT
      LAYER M5 ;
        RECT  341.712 0 341.736 0.084 ;
    END
  END vi_s[237]
  PIN vi_s[238]
    DIRECTION INPUT ;
    USE SIGNAL ;
    PORT
      LAYER M5 ;
        RECT  341.808 0 341.832 0.084 ;
    END
  END vi_s[238]
  PIN vi_s[239]
    DIRECTION INPUT ;
    USE SIGNAL ;
    PORT
      LAYER M5 ;
        RECT  341.904 0 341.928 0.084 ;
    END
  END vi_s[239]
  PIN vi_s[23]
    DIRECTION INPUT ;
    USE SIGNAL ;
    PORT
      LAYER M5 ;
        RECT  321.168 0 321.192 0.084 ;
    END
  END vi_s[23]
  PIN vi_s[240]
    DIRECTION INPUT ;
    USE SIGNAL ;
    PORT
      LAYER M5 ;
        RECT  342 0 342.024 0.084 ;
    END
  END vi_s[240]
  PIN vi_s[241]
    DIRECTION INPUT ;
    USE SIGNAL ;
    PORT
      LAYER M5 ;
        RECT  342.096 0 342.12 0.084 ;
    END
  END vi_s[241]
  PIN vi_s[242]
    DIRECTION INPUT ;
    USE SIGNAL ;
    PORT
      LAYER M5 ;
        RECT  342.192 0 342.216 0.084 ;
    END
  END vi_s[242]
  PIN vi_s[243]
    DIRECTION INPUT ;
    USE SIGNAL ;
    PORT
      LAYER M5 ;
        RECT  342.288 0 342.312 0.084 ;
    END
  END vi_s[243]
  PIN vi_s[244]
    DIRECTION INPUT ;
    USE SIGNAL ;
    PORT
      LAYER M5 ;
        RECT  342.384 0 342.408 0.084 ;
    END
  END vi_s[244]
  PIN vi_s[245]
    DIRECTION INPUT ;
    USE SIGNAL ;
    PORT
      LAYER M5 ;
        RECT  342.48 0 342.504 0.084 ;
    END
  END vi_s[245]
  PIN vi_s[246]
    DIRECTION INPUT ;
    USE SIGNAL ;
    PORT
      LAYER M5 ;
        RECT  342.576 0 342.6 0.084 ;
    END
  END vi_s[246]
  PIN vi_s[247]
    DIRECTION INPUT ;
    USE SIGNAL ;
    PORT
      LAYER M5 ;
        RECT  342.672 0 342.696 0.084 ;
    END
  END vi_s[247]
  PIN vi_s[248]
    DIRECTION INPUT ;
    USE SIGNAL ;
    PORT
      LAYER M5 ;
        RECT  342.768 0 342.792 0.084 ;
    END
  END vi_s[248]
  PIN vi_s[249]
    DIRECTION INPUT ;
    USE SIGNAL ;
    PORT
      LAYER M5 ;
        RECT  342.864 0 342.888 0.084 ;
    END
  END vi_s[249]
  PIN vi_s[24]
    DIRECTION INPUT ;
    USE SIGNAL ;
    PORT
      LAYER M5 ;
        RECT  321.264 0 321.288 0.084 ;
    END
  END vi_s[24]
  PIN vi_s[250]
    DIRECTION INPUT ;
    USE SIGNAL ;
    PORT
      LAYER M5 ;
        RECT  342.96 0 342.984 0.084 ;
    END
  END vi_s[250]
  PIN vi_s[251]
    DIRECTION INPUT ;
    USE SIGNAL ;
    PORT
      LAYER M5 ;
        RECT  343.056 0 343.08 0.084 ;
    END
  END vi_s[251]
  PIN vi_s[252]
    DIRECTION INPUT ;
    USE SIGNAL ;
    PORT
      LAYER M5 ;
        RECT  343.152 0 343.176 0.084 ;
    END
  END vi_s[252]
  PIN vi_s[253]
    DIRECTION INPUT ;
    USE SIGNAL ;
    PORT
      LAYER M5 ;
        RECT  343.248 0 343.272 0.084 ;
    END
  END vi_s[253]
  PIN vi_s[254]
    DIRECTION INPUT ;
    USE SIGNAL ;
    PORT
      LAYER M5 ;
        RECT  343.344 0 343.368 0.084 ;
    END
  END vi_s[254]
  PIN vi_s[255]
    DIRECTION INPUT ;
    USE SIGNAL ;
    PORT
      LAYER M5 ;
        RECT  343.44 0 343.464 0.084 ;
    END
  END vi_s[255]
  PIN vi_s[256]
    DIRECTION INPUT ;
    USE SIGNAL ;
    PORT
      LAYER M5 ;
        RECT  343.536 0 343.56 0.084 ;
    END
  END vi_s[256]
  PIN vi_s[257]
    DIRECTION INPUT ;
    USE SIGNAL ;
    PORT
      LAYER M5 ;
        RECT  343.632 0 343.656 0.084 ;
    END
  END vi_s[257]
  PIN vi_s[258]
    DIRECTION INPUT ;
    USE SIGNAL ;
    PORT
      LAYER M5 ;
        RECT  343.728 0 343.752 0.084 ;
    END
  END vi_s[258]
  PIN vi_s[259]
    DIRECTION INPUT ;
    USE SIGNAL ;
    PORT
      LAYER M5 ;
        RECT  343.824 0 343.848 0.084 ;
    END
  END vi_s[259]
  PIN vi_s[25]
    DIRECTION INPUT ;
    USE SIGNAL ;
    PORT
      LAYER M5 ;
        RECT  321.36 0 321.384 0.084 ;
    END
  END vi_s[25]
  PIN vi_s[260]
    DIRECTION INPUT ;
    USE SIGNAL ;
    PORT
      LAYER M5 ;
        RECT  343.92 0 343.944 0.084 ;
    END
  END vi_s[260]
  PIN vi_s[261]
    DIRECTION INPUT ;
    USE SIGNAL ;
    PORT
      LAYER M5 ;
        RECT  344.016 0 344.04 0.084 ;
    END
  END vi_s[261]
  PIN vi_s[262]
    DIRECTION INPUT ;
    USE SIGNAL ;
    PORT
      LAYER M5 ;
        RECT  344.112 0 344.136 0.084 ;
    END
  END vi_s[262]
  PIN vi_s[263]
    DIRECTION INPUT ;
    USE SIGNAL ;
    PORT
      LAYER M5 ;
        RECT  344.208 0 344.232 0.084 ;
    END
  END vi_s[263]
  PIN vi_s[264]
    DIRECTION INPUT ;
    USE SIGNAL ;
    PORT
      LAYER M5 ;
        RECT  344.304 0 344.328 0.084 ;
    END
  END vi_s[264]
  PIN vi_s[265]
    DIRECTION INPUT ;
    USE SIGNAL ;
    PORT
      LAYER M5 ;
        RECT  344.4 0 344.424 0.084 ;
    END
  END vi_s[265]
  PIN vi_s[266]
    DIRECTION INPUT ;
    USE SIGNAL ;
    PORT
      LAYER M5 ;
        RECT  344.496 0 344.52 0.084 ;
    END
  END vi_s[266]
  PIN vi_s[267]
    DIRECTION INPUT ;
    USE SIGNAL ;
    PORT
      LAYER M5 ;
        RECT  344.592 0 344.616 0.084 ;
    END
  END vi_s[267]
  PIN vi_s[268]
    DIRECTION INPUT ;
    USE SIGNAL ;
    PORT
      LAYER M5 ;
        RECT  344.688 0 344.712 0.084 ;
    END
  END vi_s[268]
  PIN vi_s[269]
    DIRECTION INPUT ;
    USE SIGNAL ;
    PORT
      LAYER M5 ;
        RECT  344.784 0 344.808 0.084 ;
    END
  END vi_s[269]
  PIN vi_s[26]
    DIRECTION INPUT ;
    USE SIGNAL ;
    PORT
      LAYER M5 ;
        RECT  321.456 0 321.48 0.084 ;
    END
  END vi_s[26]
  PIN vi_s[270]
    DIRECTION INPUT ;
    USE SIGNAL ;
    PORT
      LAYER M5 ;
        RECT  344.88 0 344.904 0.084 ;
    END
  END vi_s[270]
  PIN vi_s[271]
    DIRECTION INPUT ;
    USE SIGNAL ;
    PORT
      LAYER M5 ;
        RECT  344.976 0 345 0.084 ;
    END
  END vi_s[271]
  PIN vi_s[272]
    DIRECTION INPUT ;
    USE SIGNAL ;
    PORT
      LAYER M5 ;
        RECT  345.072 0 345.096 0.084 ;
    END
  END vi_s[272]
  PIN vi_s[273]
    DIRECTION INPUT ;
    USE SIGNAL ;
    PORT
      LAYER M5 ;
        RECT  345.168 0 345.192 0.084 ;
    END
  END vi_s[273]
  PIN vi_s[274]
    DIRECTION INPUT ;
    USE SIGNAL ;
    PORT
      LAYER M5 ;
        RECT  345.264 0 345.288 0.084 ;
    END
  END vi_s[274]
  PIN vi_s[275]
    DIRECTION INPUT ;
    USE SIGNAL ;
    PORT
      LAYER M5 ;
        RECT  345.36 0 345.384 0.084 ;
    END
  END vi_s[275]
  PIN vi_s[27]
    DIRECTION INPUT ;
    USE SIGNAL ;
    PORT
      LAYER M5 ;
        RECT  321.552 0 321.576 0.084 ;
    END
  END vi_s[27]
  PIN vi_s[28]
    DIRECTION INPUT ;
    USE SIGNAL ;
    PORT
      LAYER M5 ;
        RECT  321.648 0 321.672 0.084 ;
    END
  END vi_s[28]
  PIN vi_s[29]
    DIRECTION INPUT ;
    USE SIGNAL ;
    PORT
      LAYER M5 ;
        RECT  321.744 0 321.768 0.084 ;
    END
  END vi_s[29]
  PIN vi_s[2]
    DIRECTION INPUT ;
    USE SIGNAL ;
    PORT
      LAYER M5 ;
        RECT  319.152 0 319.176 0.084 ;
    END
  END vi_s[2]
  PIN vi_s[30]
    DIRECTION INPUT ;
    USE SIGNAL ;
    PORT
      LAYER M5 ;
        RECT  321.84 0 321.864 0.084 ;
    END
  END vi_s[30]
  PIN vi_s[31]
    DIRECTION INPUT ;
    USE SIGNAL ;
    PORT
      LAYER M5 ;
        RECT  321.936 0 321.96 0.084 ;
    END
  END vi_s[31]
  PIN vi_s[32]
    DIRECTION INPUT ;
    USE SIGNAL ;
    PORT
      LAYER M5 ;
        RECT  322.032 0 322.056 0.084 ;
    END
  END vi_s[32]
  PIN vi_s[33]
    DIRECTION INPUT ;
    USE SIGNAL ;
    PORT
      LAYER M5 ;
        RECT  322.128 0 322.152 0.084 ;
    END
  END vi_s[33]
  PIN vi_s[34]
    DIRECTION INPUT ;
    USE SIGNAL ;
    PORT
      LAYER M5 ;
        RECT  322.224 0 322.248 0.084 ;
    END
  END vi_s[34]
  PIN vi_s[35]
    DIRECTION INPUT ;
    USE SIGNAL ;
    PORT
      LAYER M5 ;
        RECT  322.32 0 322.344 0.084 ;
    END
  END vi_s[35]
  PIN vi_s[36]
    DIRECTION INPUT ;
    USE SIGNAL ;
    PORT
      LAYER M5 ;
        RECT  322.416 0 322.44 0.084 ;
    END
  END vi_s[36]
  PIN vi_s[37]
    DIRECTION INPUT ;
    USE SIGNAL ;
    PORT
      LAYER M5 ;
        RECT  322.512 0 322.536 0.084 ;
    END
  END vi_s[37]
  PIN vi_s[38]
    DIRECTION INPUT ;
    USE SIGNAL ;
    PORT
      LAYER M5 ;
        RECT  322.608 0 322.632 0.084 ;
    END
  END vi_s[38]
  PIN vi_s[39]
    DIRECTION INPUT ;
    USE SIGNAL ;
    PORT
      LAYER M5 ;
        RECT  322.704 0 322.728 0.084 ;
    END
  END vi_s[39]
  PIN vi_s[3]
    DIRECTION INPUT ;
    USE SIGNAL ;
    PORT
      LAYER M5 ;
        RECT  319.248 0 319.272 0.084 ;
    END
  END vi_s[3]
  PIN vi_s[40]
    DIRECTION INPUT ;
    USE SIGNAL ;
    PORT
      LAYER M5 ;
        RECT  322.8 0 322.824 0.084 ;
    END
  END vi_s[40]
  PIN vi_s[41]
    DIRECTION INPUT ;
    USE SIGNAL ;
    PORT
      LAYER M5 ;
        RECT  322.896 0 322.92 0.084 ;
    END
  END vi_s[41]
  PIN vi_s[42]
    DIRECTION INPUT ;
    USE SIGNAL ;
    PORT
      LAYER M5 ;
        RECT  322.992 0 323.016 0.084 ;
    END
  END vi_s[42]
  PIN vi_s[43]
    DIRECTION INPUT ;
    USE SIGNAL ;
    PORT
      LAYER M5 ;
        RECT  323.088 0 323.112 0.084 ;
    END
  END vi_s[43]
  PIN vi_s[44]
    DIRECTION INPUT ;
    USE SIGNAL ;
    PORT
      LAYER M5 ;
        RECT  323.184 0 323.208 0.084 ;
    END
  END vi_s[44]
  PIN vi_s[45]
    DIRECTION INPUT ;
    USE SIGNAL ;
    PORT
      LAYER M5 ;
        RECT  323.28 0 323.304 0.084 ;
    END
  END vi_s[45]
  PIN vi_s[46]
    DIRECTION INPUT ;
    USE SIGNAL ;
    PORT
      LAYER M5 ;
        RECT  323.376 0 323.4 0.084 ;
    END
  END vi_s[46]
  PIN vi_s[47]
    DIRECTION INPUT ;
    USE SIGNAL ;
    PORT
      LAYER M5 ;
        RECT  323.472 0 323.496 0.084 ;
    END
  END vi_s[47]
  PIN vi_s[48]
    DIRECTION INPUT ;
    USE SIGNAL ;
    PORT
      LAYER M5 ;
        RECT  323.568 0 323.592 0.084 ;
    END
  END vi_s[48]
  PIN vi_s[49]
    DIRECTION INPUT ;
    USE SIGNAL ;
    PORT
      LAYER M5 ;
        RECT  323.664 0 323.688 0.084 ;
    END
  END vi_s[49]
  PIN vi_s[4]
    DIRECTION INPUT ;
    USE SIGNAL ;
    PORT
      LAYER M5 ;
        RECT  319.344 0 319.368 0.084 ;
    END
  END vi_s[4]
  PIN vi_s[50]
    DIRECTION INPUT ;
    USE SIGNAL ;
    PORT
      LAYER M5 ;
        RECT  323.76 0 323.784 0.084 ;
    END
  END vi_s[50]
  PIN vi_s[51]
    DIRECTION INPUT ;
    USE SIGNAL ;
    PORT
      LAYER M5 ;
        RECT  323.856 0 323.88 0.084 ;
    END
  END vi_s[51]
  PIN vi_s[52]
    DIRECTION INPUT ;
    USE SIGNAL ;
    PORT
      LAYER M5 ;
        RECT  323.952 0 323.976 0.084 ;
    END
  END vi_s[52]
  PIN vi_s[53]
    DIRECTION INPUT ;
    USE SIGNAL ;
    PORT
      LAYER M5 ;
        RECT  324.048 0 324.072 0.084 ;
    END
  END vi_s[53]
  PIN vi_s[54]
    DIRECTION INPUT ;
    USE SIGNAL ;
    PORT
      LAYER M5 ;
        RECT  324.144 0 324.168 0.084 ;
    END
  END vi_s[54]
  PIN vi_s[55]
    DIRECTION INPUT ;
    USE SIGNAL ;
    PORT
      LAYER M5 ;
        RECT  324.24 0 324.264 0.084 ;
    END
  END vi_s[55]
  PIN vi_s[56]
    DIRECTION INPUT ;
    USE SIGNAL ;
    PORT
      LAYER M5 ;
        RECT  324.336 0 324.36 0.084 ;
    END
  END vi_s[56]
  PIN vi_s[57]
    DIRECTION INPUT ;
    USE SIGNAL ;
    PORT
      LAYER M5 ;
        RECT  324.432 0 324.456 0.084 ;
    END
  END vi_s[57]
  PIN vi_s[58]
    DIRECTION INPUT ;
    USE SIGNAL ;
    PORT
      LAYER M5 ;
        RECT  324.528 0 324.552 0.084 ;
    END
  END vi_s[58]
  PIN vi_s[59]
    DIRECTION INPUT ;
    USE SIGNAL ;
    PORT
      LAYER M5 ;
        RECT  324.624 0 324.648 0.084 ;
    END
  END vi_s[59]
  PIN vi_s[5]
    DIRECTION INPUT ;
    USE SIGNAL ;
    PORT
      LAYER M5 ;
        RECT  319.44 0 319.464 0.084 ;
    END
  END vi_s[5]
  PIN vi_s[60]
    DIRECTION INPUT ;
    USE SIGNAL ;
    PORT
      LAYER M5 ;
        RECT  324.72 0 324.744 0.084 ;
    END
  END vi_s[60]
  PIN vi_s[61]
    DIRECTION INPUT ;
    USE SIGNAL ;
    PORT
      LAYER M5 ;
        RECT  324.816 0 324.84 0.084 ;
    END
  END vi_s[61]
  PIN vi_s[62]
    DIRECTION INPUT ;
    USE SIGNAL ;
    PORT
      LAYER M5 ;
        RECT  324.912 0 324.936 0.084 ;
    END
  END vi_s[62]
  PIN vi_s[63]
    DIRECTION INPUT ;
    USE SIGNAL ;
    PORT
      LAYER M5 ;
        RECT  325.008 0 325.032 0.084 ;
    END
  END vi_s[63]
  PIN vi_s[64]
    DIRECTION INPUT ;
    USE SIGNAL ;
    PORT
      LAYER M5 ;
        RECT  325.104 0 325.128 0.084 ;
    END
  END vi_s[64]
  PIN vi_s[65]
    DIRECTION INPUT ;
    USE SIGNAL ;
    PORT
      LAYER M5 ;
        RECT  325.2 0 325.224 0.084 ;
    END
  END vi_s[65]
  PIN vi_s[66]
    DIRECTION INPUT ;
    USE SIGNAL ;
    PORT
      LAYER M5 ;
        RECT  325.296 0 325.32 0.084 ;
    END
  END vi_s[66]
  PIN vi_s[67]
    DIRECTION INPUT ;
    USE SIGNAL ;
    PORT
      LAYER M5 ;
        RECT  325.392 0 325.416 0.084 ;
    END
  END vi_s[67]
  PIN vi_s[68]
    DIRECTION INPUT ;
    USE SIGNAL ;
    PORT
      LAYER M5 ;
        RECT  325.488 0 325.512 0.084 ;
    END
  END vi_s[68]
  PIN vi_s[69]
    DIRECTION INPUT ;
    USE SIGNAL ;
    PORT
      LAYER M5 ;
        RECT  325.584 0 325.608 0.084 ;
    END
  END vi_s[69]
  PIN vi_s[6]
    DIRECTION INPUT ;
    USE SIGNAL ;
    PORT
      LAYER M5 ;
        RECT  319.536 0 319.56 0.084 ;
    END
  END vi_s[6]
  PIN vi_s[70]
    DIRECTION INPUT ;
    USE SIGNAL ;
    PORT
      LAYER M5 ;
        RECT  325.68 0 325.704 0.084 ;
    END
  END vi_s[70]
  PIN vi_s[71]
    DIRECTION INPUT ;
    USE SIGNAL ;
    PORT
      LAYER M5 ;
        RECT  325.776 0 325.8 0.084 ;
    END
  END vi_s[71]
  PIN vi_s[72]
    DIRECTION INPUT ;
    USE SIGNAL ;
    PORT
      LAYER M5 ;
        RECT  325.872 0 325.896 0.084 ;
    END
  END vi_s[72]
  PIN vi_s[73]
    DIRECTION INPUT ;
    USE SIGNAL ;
    PORT
      LAYER M5 ;
        RECT  325.968 0 325.992 0.084 ;
    END
  END vi_s[73]
  PIN vi_s[74]
    DIRECTION INPUT ;
    USE SIGNAL ;
    PORT
      LAYER M5 ;
        RECT  326.064 0 326.088 0.084 ;
    END
  END vi_s[74]
  PIN vi_s[75]
    DIRECTION INPUT ;
    USE SIGNAL ;
    PORT
      LAYER M5 ;
        RECT  326.16 0 326.184 0.084 ;
    END
  END vi_s[75]
  PIN vi_s[76]
    DIRECTION INPUT ;
    USE SIGNAL ;
    PORT
      LAYER M5 ;
        RECT  326.256 0 326.28 0.084 ;
    END
  END vi_s[76]
  PIN vi_s[77]
    DIRECTION INPUT ;
    USE SIGNAL ;
    PORT
      LAYER M5 ;
        RECT  326.352 0 326.376 0.084 ;
    END
  END vi_s[77]
  PIN vi_s[78]
    DIRECTION INPUT ;
    USE SIGNAL ;
    PORT
      LAYER M5 ;
        RECT  326.448 0 326.472 0.084 ;
    END
  END vi_s[78]
  PIN vi_s[79]
    DIRECTION INPUT ;
    USE SIGNAL ;
    PORT
      LAYER M5 ;
        RECT  326.544 0 326.568 0.084 ;
    END
  END vi_s[79]
  PIN vi_s[7]
    DIRECTION INPUT ;
    USE SIGNAL ;
    PORT
      LAYER M5 ;
        RECT  319.632 0 319.656 0.084 ;
    END
  END vi_s[7]
  PIN vi_s[80]
    DIRECTION INPUT ;
    USE SIGNAL ;
    PORT
      LAYER M5 ;
        RECT  326.64 0 326.664 0.084 ;
    END
  END vi_s[80]
  PIN vi_s[81]
    DIRECTION INPUT ;
    USE SIGNAL ;
    PORT
      LAYER M5 ;
        RECT  326.736 0 326.76 0.084 ;
    END
  END vi_s[81]
  PIN vi_s[82]
    DIRECTION INPUT ;
    USE SIGNAL ;
    PORT
      LAYER M5 ;
        RECT  326.832 0 326.856 0.084 ;
    END
  END vi_s[82]
  PIN vi_s[83]
    DIRECTION INPUT ;
    USE SIGNAL ;
    PORT
      LAYER M5 ;
        RECT  326.928 0 326.952 0.084 ;
    END
  END vi_s[83]
  PIN vi_s[84]
    DIRECTION INPUT ;
    USE SIGNAL ;
    PORT
      LAYER M5 ;
        RECT  327.024 0 327.048 0.084 ;
    END
  END vi_s[84]
  PIN vi_s[85]
    DIRECTION INPUT ;
    USE SIGNAL ;
    PORT
      LAYER M5 ;
        RECT  327.12 0 327.144 0.084 ;
    END
  END vi_s[85]
  PIN vi_s[86]
    DIRECTION INPUT ;
    USE SIGNAL ;
    PORT
      LAYER M5 ;
        RECT  327.216 0 327.24 0.084 ;
    END
  END vi_s[86]
  PIN vi_s[87]
    DIRECTION INPUT ;
    USE SIGNAL ;
    PORT
      LAYER M5 ;
        RECT  327.312 0 327.336 0.084 ;
    END
  END vi_s[87]
  PIN vi_s[88]
    DIRECTION INPUT ;
    USE SIGNAL ;
    PORT
      LAYER M5 ;
        RECT  327.408 0 327.432 0.084 ;
    END
  END vi_s[88]
  PIN vi_s[89]
    DIRECTION INPUT ;
    USE SIGNAL ;
    PORT
      LAYER M5 ;
        RECT  327.504 0 327.528 0.084 ;
    END
  END vi_s[89]
  PIN vi_s[8]
    DIRECTION INPUT ;
    USE SIGNAL ;
    PORT
      LAYER M5 ;
        RECT  319.728 0 319.752 0.084 ;
    END
  END vi_s[8]
  PIN vi_s[90]
    DIRECTION INPUT ;
    USE SIGNAL ;
    PORT
      LAYER M5 ;
        RECT  327.6 0 327.624 0.084 ;
    END
  END vi_s[90]
  PIN vi_s[91]
    DIRECTION INPUT ;
    USE SIGNAL ;
    PORT
      LAYER M5 ;
        RECT  327.696 0 327.72 0.084 ;
    END
  END vi_s[91]
  PIN vi_s[92]
    DIRECTION INPUT ;
    USE SIGNAL ;
    PORT
      LAYER M5 ;
        RECT  327.792 0 327.816 0.084 ;
    END
  END vi_s[92]
  PIN vi_s[93]
    DIRECTION INPUT ;
    USE SIGNAL ;
    PORT
      LAYER M5 ;
        RECT  327.888 0 327.912 0.084 ;
    END
  END vi_s[93]
  PIN vi_s[94]
    DIRECTION INPUT ;
    USE SIGNAL ;
    PORT
      LAYER M5 ;
        RECT  327.984 0 328.008 0.084 ;
    END
  END vi_s[94]
  PIN vi_s[95]
    DIRECTION INPUT ;
    USE SIGNAL ;
    PORT
      LAYER M5 ;
        RECT  328.08 0 328.104 0.084 ;
    END
  END vi_s[95]
  PIN vi_s[96]
    DIRECTION INPUT ;
    USE SIGNAL ;
    PORT
      LAYER M5 ;
        RECT  328.176 0 328.2 0.084 ;
    END
  END vi_s[96]
  PIN vi_s[97]
    DIRECTION INPUT ;
    USE SIGNAL ;
    PORT
      LAYER M5 ;
        RECT  328.272 0 328.296 0.084 ;
    END
  END vi_s[97]
  PIN vi_s[98]
    DIRECTION INPUT ;
    USE SIGNAL ;
    PORT
      LAYER M5 ;
        RECT  328.368 0 328.392 0.084 ;
    END
  END vi_s[98]
  PIN vi_s[99]
    DIRECTION INPUT ;
    USE SIGNAL ;
    PORT
      LAYER M5 ;
        RECT  328.464 0 328.488 0.084 ;
    END
  END vi_s[99]
  PIN vi_s[9]
    DIRECTION INPUT ;
    USE SIGNAL ;
    PORT
      LAYER M5 ;
        RECT  319.824 0 319.848 0.084 ;
    END
  END vi_s[9]
  PIN vo_s[0]
    DIRECTION OUTPUT ;
    USE SIGNAL ;
    PORT
      LAYER M5 ;
        RECT  0.24 0 0.264 0.084 ;
    END
  END vo_s[0]
  PIN vo_s[100]
    DIRECTION OUTPUT ;
    USE SIGNAL ;
    PORT
      LAYER M5 ;
        RECT  9.84 0 9.864 0.084 ;
    END
  END vo_s[100]
  PIN vo_s[101]
    DIRECTION OUTPUT ;
    USE SIGNAL ;
    PORT
      LAYER M5 ;
        RECT  9.936 0 9.96 0.084 ;
    END
  END vo_s[101]
  PIN vo_s[102]
    DIRECTION OUTPUT ;
    USE SIGNAL ;
    PORT
      LAYER M5 ;
        RECT  10.032 0 10.056 0.084 ;
    END
  END vo_s[102]
  PIN vo_s[103]
    DIRECTION OUTPUT ;
    USE SIGNAL ;
    PORT
      LAYER M5 ;
        RECT  10.128 0 10.152 0.084 ;
    END
  END vo_s[103]
  PIN vo_s[104]
    DIRECTION OUTPUT ;
    USE SIGNAL ;
    PORT
      LAYER M5 ;
        RECT  10.224 0 10.248 0.084 ;
    END
  END vo_s[104]
  PIN vo_s[105]
    DIRECTION OUTPUT ;
    USE SIGNAL ;
    PORT
      LAYER M5 ;
        RECT  10.32 0 10.344 0.084 ;
    END
  END vo_s[105]
  PIN vo_s[106]
    DIRECTION OUTPUT ;
    USE SIGNAL ;
    PORT
      LAYER M5 ;
        RECT  10.416 0 10.44 0.084 ;
    END
  END vo_s[106]
  PIN vo_s[107]
    DIRECTION OUTPUT ;
    USE SIGNAL ;
    PORT
      LAYER M5 ;
        RECT  10.512 0 10.536 0.084 ;
    END
  END vo_s[107]
  PIN vo_s[108]
    DIRECTION OUTPUT ;
    USE SIGNAL ;
    PORT
      LAYER M5 ;
        RECT  10.608 0 10.632 0.084 ;
    END
  END vo_s[108]
  PIN vo_s[109]
    DIRECTION OUTPUT ;
    USE SIGNAL ;
    PORT
      LAYER M5 ;
        RECT  10.704 0 10.728 0.084 ;
    END
  END vo_s[109]
  PIN vo_s[10]
    DIRECTION OUTPUT ;
    USE SIGNAL ;
    PORT
      LAYER M5 ;
        RECT  1.2 0 1.224 0.084 ;
    END
  END vo_s[10]
  PIN vo_s[110]
    DIRECTION OUTPUT ;
    USE SIGNAL ;
    PORT
      LAYER M5 ;
        RECT  10.8 0 10.824 0.084 ;
    END
  END vo_s[110]
  PIN vo_s[111]
    DIRECTION OUTPUT ;
    USE SIGNAL ;
    PORT
      LAYER M5 ;
        RECT  10.896 0 10.92 0.084 ;
    END
  END vo_s[111]
  PIN vo_s[112]
    DIRECTION OUTPUT ;
    USE SIGNAL ;
    PORT
      LAYER M5 ;
        RECT  10.992 0 11.016 0.084 ;
    END
  END vo_s[112]
  PIN vo_s[113]
    DIRECTION OUTPUT ;
    USE SIGNAL ;
    PORT
      LAYER M5 ;
        RECT  11.088 0 11.112 0.084 ;
    END
  END vo_s[113]
  PIN vo_s[114]
    DIRECTION OUTPUT ;
    USE SIGNAL ;
    PORT
      LAYER M5 ;
        RECT  11.184 0 11.208 0.084 ;
    END
  END vo_s[114]
  PIN vo_s[115]
    DIRECTION OUTPUT ;
    USE SIGNAL ;
    PORT
      LAYER M5 ;
        RECT  11.28 0 11.304 0.084 ;
    END
  END vo_s[115]
  PIN vo_s[116]
    DIRECTION OUTPUT ;
    USE SIGNAL ;
    PORT
      LAYER M5 ;
        RECT  11.376 0 11.4 0.084 ;
    END
  END vo_s[116]
  PIN vo_s[117]
    DIRECTION OUTPUT ;
    USE SIGNAL ;
    PORT
      LAYER M5 ;
        RECT  11.472 0 11.496 0.084 ;
    END
  END vo_s[117]
  PIN vo_s[118]
    DIRECTION OUTPUT ;
    USE SIGNAL ;
    PORT
      LAYER M5 ;
        RECT  11.568 0 11.592 0.084 ;
    END
  END vo_s[118]
  PIN vo_s[119]
    DIRECTION OUTPUT ;
    USE SIGNAL ;
    PORT
      LAYER M5 ;
        RECT  11.664 0 11.688 0.084 ;
    END
  END vo_s[119]
  PIN vo_s[11]
    DIRECTION OUTPUT ;
    USE SIGNAL ;
    PORT
      LAYER M5 ;
        RECT  1.296 0 1.32 0.084 ;
    END
  END vo_s[11]
  PIN vo_s[120]
    DIRECTION OUTPUT ;
    USE SIGNAL ;
    PORT
      LAYER M5 ;
        RECT  11.76 0 11.784 0.084 ;
    END
  END vo_s[120]
  PIN vo_s[121]
    DIRECTION OUTPUT ;
    USE SIGNAL ;
    PORT
      LAYER M5 ;
        RECT  11.856 0 11.88 0.084 ;
    END
  END vo_s[121]
  PIN vo_s[122]
    DIRECTION OUTPUT ;
    USE SIGNAL ;
    PORT
      LAYER M5 ;
        RECT  11.952 0 11.976 0.084 ;
    END
  END vo_s[122]
  PIN vo_s[123]
    DIRECTION OUTPUT ;
    USE SIGNAL ;
    PORT
      LAYER M5 ;
        RECT  12.048 0 12.072 0.084 ;
    END
  END vo_s[123]
  PIN vo_s[124]
    DIRECTION OUTPUT ;
    USE SIGNAL ;
    PORT
      LAYER M5 ;
        RECT  12.144 0 12.168 0.084 ;
    END
  END vo_s[124]
  PIN vo_s[125]
    DIRECTION OUTPUT ;
    USE SIGNAL ;
    PORT
      LAYER M5 ;
        RECT  12.24 0 12.264 0.084 ;
    END
  END vo_s[125]
  PIN vo_s[126]
    DIRECTION OUTPUT ;
    USE SIGNAL ;
    PORT
      LAYER M5 ;
        RECT  12.336 0 12.36 0.084 ;
    END
  END vo_s[126]
  PIN vo_s[127]
    DIRECTION OUTPUT ;
    USE SIGNAL ;
    PORT
      LAYER M5 ;
        RECT  12.432 0 12.456 0.084 ;
    END
  END vo_s[127]
  PIN vo_s[128]
    DIRECTION OUTPUT ;
    USE SIGNAL ;
    PORT
      LAYER M5 ;
        RECT  12.528 0 12.552 0.084 ;
    END
  END vo_s[128]
  PIN vo_s[129]
    DIRECTION OUTPUT ;
    USE SIGNAL ;
    PORT
      LAYER M5 ;
        RECT  12.624 0 12.648 0.084 ;
    END
  END vo_s[129]
  PIN vo_s[12]
    DIRECTION OUTPUT ;
    USE SIGNAL ;
    PORT
      LAYER M5 ;
        RECT  1.392 0 1.416 0.084 ;
    END
  END vo_s[12]
  PIN vo_s[130]
    DIRECTION OUTPUT ;
    USE SIGNAL ;
    PORT
      LAYER M5 ;
        RECT  12.72 0 12.744 0.084 ;
    END
  END vo_s[130]
  PIN vo_s[131]
    DIRECTION OUTPUT ;
    USE SIGNAL ;
    PORT
      LAYER M5 ;
        RECT  12.816 0 12.84 0.084 ;
    END
  END vo_s[131]
  PIN vo_s[132]
    DIRECTION OUTPUT ;
    USE SIGNAL ;
    PORT
      LAYER M5 ;
        RECT  12.912 0 12.936 0.084 ;
    END
  END vo_s[132]
  PIN vo_s[133]
    DIRECTION OUTPUT ;
    USE SIGNAL ;
    PORT
      LAYER M5 ;
        RECT  13.008 0 13.032 0.084 ;
    END
  END vo_s[133]
  PIN vo_s[134]
    DIRECTION OUTPUT ;
    USE SIGNAL ;
    PORT
      LAYER M5 ;
        RECT  13.104 0 13.128 0.084 ;
    END
  END vo_s[134]
  PIN vo_s[135]
    DIRECTION OUTPUT ;
    USE SIGNAL ;
    PORT
      LAYER M5 ;
        RECT  13.2 0 13.224 0.084 ;
    END
  END vo_s[135]
  PIN vo_s[136]
    DIRECTION OUTPUT ;
    USE SIGNAL ;
    PORT
      LAYER M5 ;
        RECT  13.296 0 13.32 0.084 ;
    END
  END vo_s[136]
  PIN vo_s[137]
    DIRECTION OUTPUT ;
    USE SIGNAL ;
    PORT
      LAYER M5 ;
        RECT  13.392 0 13.416 0.084 ;
    END
  END vo_s[137]
  PIN vo_s[138]
    DIRECTION OUTPUT ;
    USE SIGNAL ;
    PORT
      LAYER M5 ;
        RECT  13.488 0 13.512 0.084 ;
    END
  END vo_s[138]
  PIN vo_s[139]
    DIRECTION OUTPUT ;
    USE SIGNAL ;
    PORT
      LAYER M5 ;
        RECT  13.584 0 13.608 0.084 ;
    END
  END vo_s[139]
  PIN vo_s[13]
    DIRECTION OUTPUT ;
    USE SIGNAL ;
    PORT
      LAYER M5 ;
        RECT  1.488 0 1.512 0.084 ;
    END
  END vo_s[13]
  PIN vo_s[140]
    DIRECTION OUTPUT ;
    USE SIGNAL ;
    PORT
      LAYER M5 ;
        RECT  13.68 0 13.704 0.084 ;
    END
  END vo_s[140]
  PIN vo_s[141]
    DIRECTION OUTPUT ;
    USE SIGNAL ;
    PORT
      LAYER M5 ;
        RECT  13.776 0 13.8 0.084 ;
    END
  END vo_s[141]
  PIN vo_s[142]
    DIRECTION OUTPUT ;
    USE SIGNAL ;
    PORT
      LAYER M5 ;
        RECT  13.872 0 13.896 0.084 ;
    END
  END vo_s[142]
  PIN vo_s[143]
    DIRECTION OUTPUT ;
    USE SIGNAL ;
    PORT
      LAYER M5 ;
        RECT  13.968 0 13.992 0.084 ;
    END
  END vo_s[143]
  PIN vo_s[144]
    DIRECTION OUTPUT ;
    USE SIGNAL ;
    PORT
      LAYER M5 ;
        RECT  14.064 0 14.088 0.084 ;
    END
  END vo_s[144]
  PIN vo_s[145]
    DIRECTION OUTPUT ;
    USE SIGNAL ;
    PORT
      LAYER M5 ;
        RECT  14.16 0 14.184 0.084 ;
    END
  END vo_s[145]
  PIN vo_s[146]
    DIRECTION OUTPUT ;
    USE SIGNAL ;
    PORT
      LAYER M5 ;
        RECT  14.256 0 14.28 0.084 ;
    END
  END vo_s[146]
  PIN vo_s[147]
    DIRECTION OUTPUT ;
    USE SIGNAL ;
    PORT
      LAYER M5 ;
        RECT  14.352 0 14.376 0.084 ;
    END
  END vo_s[147]
  PIN vo_s[148]
    DIRECTION OUTPUT ;
    USE SIGNAL ;
    PORT
      LAYER M5 ;
        RECT  14.448 0 14.472 0.084 ;
    END
  END vo_s[148]
  PIN vo_s[149]
    DIRECTION OUTPUT ;
    USE SIGNAL ;
    PORT
      LAYER M5 ;
        RECT  14.544 0 14.568 0.084 ;
    END
  END vo_s[149]
  PIN vo_s[14]
    DIRECTION OUTPUT ;
    USE SIGNAL ;
    PORT
      LAYER M5 ;
        RECT  1.584 0 1.608 0.084 ;
    END
  END vo_s[14]
  PIN vo_s[150]
    DIRECTION OUTPUT ;
    USE SIGNAL ;
    PORT
      LAYER M5 ;
        RECT  14.64 0 14.664 0.084 ;
    END
  END vo_s[150]
  PIN vo_s[151]
    DIRECTION OUTPUT ;
    USE SIGNAL ;
    PORT
      LAYER M5 ;
        RECT  14.736 0 14.76 0.084 ;
    END
  END vo_s[151]
  PIN vo_s[152]
    DIRECTION OUTPUT ;
    USE SIGNAL ;
    PORT
      LAYER M5 ;
        RECT  14.832 0 14.856 0.084 ;
    END
  END vo_s[152]
  PIN vo_s[153]
    DIRECTION OUTPUT ;
    USE SIGNAL ;
    PORT
      LAYER M5 ;
        RECT  14.928 0 14.952 0.084 ;
    END
  END vo_s[153]
  PIN vo_s[154]
    DIRECTION OUTPUT ;
    USE SIGNAL ;
    PORT
      LAYER M5 ;
        RECT  15.024 0 15.048 0.084 ;
    END
  END vo_s[154]
  PIN vo_s[155]
    DIRECTION OUTPUT ;
    USE SIGNAL ;
    PORT
      LAYER M5 ;
        RECT  15.12 0 15.144 0.084 ;
    END
  END vo_s[155]
  PIN vo_s[156]
    DIRECTION OUTPUT ;
    USE SIGNAL ;
    PORT
      LAYER M5 ;
        RECT  15.216 0 15.24 0.084 ;
    END
  END vo_s[156]
  PIN vo_s[157]
    DIRECTION OUTPUT ;
    USE SIGNAL ;
    PORT
      LAYER M5 ;
        RECT  15.312 0 15.336 0.084 ;
    END
  END vo_s[157]
  PIN vo_s[158]
    DIRECTION OUTPUT ;
    USE SIGNAL ;
    PORT
      LAYER M5 ;
        RECT  15.408 0 15.432 0.084 ;
    END
  END vo_s[158]
  PIN vo_s[159]
    DIRECTION OUTPUT ;
    USE SIGNAL ;
    PORT
      LAYER M5 ;
        RECT  15.504 0 15.528 0.084 ;
    END
  END vo_s[159]
  PIN vo_s[15]
    DIRECTION OUTPUT ;
    USE SIGNAL ;
    PORT
      LAYER M5 ;
        RECT  1.68 0 1.704 0.084 ;
    END
  END vo_s[15]
  PIN vo_s[160]
    DIRECTION OUTPUT ;
    USE SIGNAL ;
    PORT
      LAYER M5 ;
        RECT  15.6 0 15.624 0.084 ;
    END
  END vo_s[160]
  PIN vo_s[161]
    DIRECTION OUTPUT ;
    USE SIGNAL ;
    PORT
      LAYER M5 ;
        RECT  15.696 0 15.72 0.084 ;
    END
  END vo_s[161]
  PIN vo_s[162]
    DIRECTION OUTPUT ;
    USE SIGNAL ;
    PORT
      LAYER M5 ;
        RECT  15.792 0 15.816 0.084 ;
    END
  END vo_s[162]
  PIN vo_s[163]
    DIRECTION OUTPUT ;
    USE SIGNAL ;
    PORT
      LAYER M5 ;
        RECT  15.888 0 15.912 0.084 ;
    END
  END vo_s[163]
  PIN vo_s[164]
    DIRECTION OUTPUT ;
    USE SIGNAL ;
    PORT
      LAYER M5 ;
        RECT  15.984 0 16.008 0.084 ;
    END
  END vo_s[164]
  PIN vo_s[165]
    DIRECTION OUTPUT ;
    USE SIGNAL ;
    PORT
      LAYER M5 ;
        RECT  16.08 0 16.104 0.084 ;
    END
  END vo_s[165]
  PIN vo_s[166]
    DIRECTION OUTPUT ;
    USE SIGNAL ;
    PORT
      LAYER M5 ;
        RECT  16.176 0 16.2 0.084 ;
    END
  END vo_s[166]
  PIN vo_s[167]
    DIRECTION OUTPUT ;
    USE SIGNAL ;
    PORT
      LAYER M5 ;
        RECT  16.272 0 16.296 0.084 ;
    END
  END vo_s[167]
  PIN vo_s[168]
    DIRECTION OUTPUT ;
    USE SIGNAL ;
    PORT
      LAYER M5 ;
        RECT  16.368 0 16.392 0.084 ;
    END
  END vo_s[168]
  PIN vo_s[169]
    DIRECTION OUTPUT ;
    USE SIGNAL ;
    PORT
      LAYER M5 ;
        RECT  16.464 0 16.488 0.084 ;
    END
  END vo_s[169]
  PIN vo_s[16]
    DIRECTION OUTPUT ;
    USE SIGNAL ;
    PORT
      LAYER M5 ;
        RECT  1.776 0 1.8 0.084 ;
    END
  END vo_s[16]
  PIN vo_s[170]
    DIRECTION OUTPUT ;
    USE SIGNAL ;
    PORT
      LAYER M5 ;
        RECT  16.56 0 16.584 0.084 ;
    END
  END vo_s[170]
  PIN vo_s[171]
    DIRECTION OUTPUT ;
    USE SIGNAL ;
    PORT
      LAYER M5 ;
        RECT  16.656 0 16.68 0.084 ;
    END
  END vo_s[171]
  PIN vo_s[172]
    DIRECTION OUTPUT ;
    USE SIGNAL ;
    PORT
      LAYER M5 ;
        RECT  16.752 0 16.776 0.084 ;
    END
  END vo_s[172]
  PIN vo_s[173]
    DIRECTION OUTPUT ;
    USE SIGNAL ;
    PORT
      LAYER M5 ;
        RECT  16.848 0 16.872 0.084 ;
    END
  END vo_s[173]
  PIN vo_s[174]
    DIRECTION OUTPUT ;
    USE SIGNAL ;
    PORT
      LAYER M5 ;
        RECT  16.944 0 16.968 0.084 ;
    END
  END vo_s[174]
  PIN vo_s[175]
    DIRECTION OUTPUT ;
    USE SIGNAL ;
    PORT
      LAYER M5 ;
        RECT  17.04 0 17.064 0.084 ;
    END
  END vo_s[175]
  PIN vo_s[176]
    DIRECTION OUTPUT ;
    USE SIGNAL ;
    PORT
      LAYER M5 ;
        RECT  17.136 0 17.16 0.084 ;
    END
  END vo_s[176]
  PIN vo_s[177]
    DIRECTION OUTPUT ;
    USE SIGNAL ;
    PORT
      LAYER M5 ;
        RECT  17.232 0 17.256 0.084 ;
    END
  END vo_s[177]
  PIN vo_s[178]
    DIRECTION OUTPUT ;
    USE SIGNAL ;
    PORT
      LAYER M5 ;
        RECT  17.328 0 17.352 0.084 ;
    END
  END vo_s[178]
  PIN vo_s[179]
    DIRECTION OUTPUT ;
    USE SIGNAL ;
    PORT
      LAYER M5 ;
        RECT  17.424 0 17.448 0.084 ;
    END
  END vo_s[179]
  PIN vo_s[17]
    DIRECTION OUTPUT ;
    USE SIGNAL ;
    PORT
      LAYER M5 ;
        RECT  1.872 0 1.896 0.084 ;
    END
  END vo_s[17]
  PIN vo_s[180]
    DIRECTION OUTPUT ;
    USE SIGNAL ;
    PORT
      LAYER M5 ;
        RECT  17.52 0 17.544 0.084 ;
    END
  END vo_s[180]
  PIN vo_s[181]
    DIRECTION OUTPUT ;
    USE SIGNAL ;
    PORT
      LAYER M5 ;
        RECT  17.616 0 17.64 0.084 ;
    END
  END vo_s[181]
  PIN vo_s[182]
    DIRECTION OUTPUT ;
    USE SIGNAL ;
    PORT
      LAYER M5 ;
        RECT  17.712 0 17.736 0.084 ;
    END
  END vo_s[182]
  PIN vo_s[183]
    DIRECTION OUTPUT ;
    USE SIGNAL ;
    PORT
      LAYER M5 ;
        RECT  17.808 0 17.832 0.084 ;
    END
  END vo_s[183]
  PIN vo_s[184]
    DIRECTION OUTPUT ;
    USE SIGNAL ;
    PORT
      LAYER M5 ;
        RECT  17.904 0 17.928 0.084 ;
    END
  END vo_s[184]
  PIN vo_s[185]
    DIRECTION OUTPUT ;
    USE SIGNAL ;
    PORT
      LAYER M5 ;
        RECT  18 0 18.024 0.084 ;
    END
  END vo_s[185]
  PIN vo_s[186]
    DIRECTION OUTPUT ;
    USE SIGNAL ;
    PORT
      LAYER M5 ;
        RECT  18.096 0 18.12 0.084 ;
    END
  END vo_s[186]
  PIN vo_s[187]
    DIRECTION OUTPUT ;
    USE SIGNAL ;
    PORT
      LAYER M5 ;
        RECT  18.192 0 18.216 0.084 ;
    END
  END vo_s[187]
  PIN vo_s[188]
    DIRECTION OUTPUT ;
    USE SIGNAL ;
    PORT
      LAYER M5 ;
        RECT  18.288 0 18.312 0.084 ;
    END
  END vo_s[188]
  PIN vo_s[189]
    DIRECTION OUTPUT ;
    USE SIGNAL ;
    PORT
      LAYER M5 ;
        RECT  18.384 0 18.408 0.084 ;
    END
  END vo_s[189]
  PIN vo_s[18]
    DIRECTION OUTPUT ;
    USE SIGNAL ;
    PORT
      LAYER M5 ;
        RECT  1.968 0 1.992 0.084 ;
    END
  END vo_s[18]
  PIN vo_s[190]
    DIRECTION OUTPUT ;
    USE SIGNAL ;
    PORT
      LAYER M5 ;
        RECT  18.48 0 18.504 0.084 ;
    END
  END vo_s[190]
  PIN vo_s[191]
    DIRECTION OUTPUT ;
    USE SIGNAL ;
    PORT
      LAYER M5 ;
        RECT  18.576 0 18.6 0.084 ;
    END
  END vo_s[191]
  PIN vo_s[192]
    DIRECTION OUTPUT ;
    USE SIGNAL ;
    PORT
      LAYER M5 ;
        RECT  18.672 0 18.696 0.084 ;
    END
  END vo_s[192]
  PIN vo_s[193]
    DIRECTION OUTPUT ;
    USE SIGNAL ;
    PORT
      LAYER M5 ;
        RECT  18.768 0 18.792 0.084 ;
    END
  END vo_s[193]
  PIN vo_s[194]
    DIRECTION OUTPUT ;
    USE SIGNAL ;
    PORT
      LAYER M5 ;
        RECT  18.864 0 18.888 0.084 ;
    END
  END vo_s[194]
  PIN vo_s[195]
    DIRECTION OUTPUT ;
    USE SIGNAL ;
    PORT
      LAYER M5 ;
        RECT  18.96 0 18.984 0.084 ;
    END
  END vo_s[195]
  PIN vo_s[196]
    DIRECTION OUTPUT ;
    USE SIGNAL ;
    PORT
      LAYER M5 ;
        RECT  19.056 0 19.08 0.084 ;
    END
  END vo_s[196]
  PIN vo_s[197]
    DIRECTION OUTPUT ;
    USE SIGNAL ;
    PORT
      LAYER M5 ;
        RECT  19.152 0 19.176 0.084 ;
    END
  END vo_s[197]
  PIN vo_s[198]
    DIRECTION OUTPUT ;
    USE SIGNAL ;
    PORT
      LAYER M5 ;
        RECT  19.248 0 19.272 0.084 ;
    END
  END vo_s[198]
  PIN vo_s[199]
    DIRECTION OUTPUT ;
    USE SIGNAL ;
    PORT
      LAYER M5 ;
        RECT  19.344 0 19.368 0.084 ;
    END
  END vo_s[199]
  PIN vo_s[19]
    DIRECTION OUTPUT ;
    USE SIGNAL ;
    PORT
      LAYER M5 ;
        RECT  2.064 0 2.088 0.084 ;
    END
  END vo_s[19]
  PIN vo_s[1]
    DIRECTION OUTPUT ;
    USE SIGNAL ;
    PORT
      LAYER M5 ;
        RECT  0.336 0 0.36 0.084 ;
    END
  END vo_s[1]
  PIN vo_s[200]
    DIRECTION OUTPUT ;
    USE SIGNAL ;
    PORT
      LAYER M5 ;
        RECT  19.44 0 19.464 0.084 ;
    END
  END vo_s[200]
  PIN vo_s[201]
    DIRECTION OUTPUT ;
    USE SIGNAL ;
    PORT
      LAYER M5 ;
        RECT  19.536 0 19.56 0.084 ;
    END
  END vo_s[201]
  PIN vo_s[202]
    DIRECTION OUTPUT ;
    USE SIGNAL ;
    PORT
      LAYER M5 ;
        RECT  19.632 0 19.656 0.084 ;
    END
  END vo_s[202]
  PIN vo_s[203]
    DIRECTION OUTPUT ;
    USE SIGNAL ;
    PORT
      LAYER M5 ;
        RECT  19.728 0 19.752 0.084 ;
    END
  END vo_s[203]
  PIN vo_s[204]
    DIRECTION OUTPUT ;
    USE SIGNAL ;
    PORT
      LAYER M5 ;
        RECT  19.824 0 19.848 0.084 ;
    END
  END vo_s[204]
  PIN vo_s[205]
    DIRECTION OUTPUT ;
    USE SIGNAL ;
    PORT
      LAYER M5 ;
        RECT  19.92 0 19.944 0.084 ;
    END
  END vo_s[205]
  PIN vo_s[206]
    DIRECTION OUTPUT ;
    USE SIGNAL ;
    PORT
      LAYER M5 ;
        RECT  20.016 0 20.04 0.084 ;
    END
  END vo_s[206]
  PIN vo_s[207]
    DIRECTION OUTPUT ;
    USE SIGNAL ;
    PORT
      LAYER M5 ;
        RECT  20.112 0 20.136 0.084 ;
    END
  END vo_s[207]
  PIN vo_s[208]
    DIRECTION OUTPUT ;
    USE SIGNAL ;
    PORT
      LAYER M5 ;
        RECT  20.208 0 20.232 0.084 ;
    END
  END vo_s[208]
  PIN vo_s[209]
    DIRECTION OUTPUT ;
    USE SIGNAL ;
    PORT
      LAYER M5 ;
        RECT  20.304 0 20.328 0.084 ;
    END
  END vo_s[209]
  PIN vo_s[20]
    DIRECTION OUTPUT ;
    USE SIGNAL ;
    PORT
      LAYER M5 ;
        RECT  2.16 0 2.184 0.084 ;
    END
  END vo_s[20]
  PIN vo_s[210]
    DIRECTION OUTPUT ;
    USE SIGNAL ;
    PORT
      LAYER M5 ;
        RECT  20.4 0 20.424 0.084 ;
    END
  END vo_s[210]
  PIN vo_s[211]
    DIRECTION OUTPUT ;
    USE SIGNAL ;
    PORT
      LAYER M5 ;
        RECT  20.496 0 20.52 0.084 ;
    END
  END vo_s[211]
  PIN vo_s[212]
    DIRECTION OUTPUT ;
    USE SIGNAL ;
    PORT
      LAYER M5 ;
        RECT  20.592 0 20.616 0.084 ;
    END
  END vo_s[212]
  PIN vo_s[213]
    DIRECTION OUTPUT ;
    USE SIGNAL ;
    PORT
      LAYER M5 ;
        RECT  20.688 0 20.712 0.084 ;
    END
  END vo_s[213]
  PIN vo_s[214]
    DIRECTION OUTPUT ;
    USE SIGNAL ;
    PORT
      LAYER M5 ;
        RECT  20.784 0 20.808 0.084 ;
    END
  END vo_s[214]
  PIN vo_s[215]
    DIRECTION OUTPUT ;
    USE SIGNAL ;
    PORT
      LAYER M5 ;
        RECT  20.88 0 20.904 0.084 ;
    END
  END vo_s[215]
  PIN vo_s[216]
    DIRECTION OUTPUT ;
    USE SIGNAL ;
    PORT
      LAYER M5 ;
        RECT  20.976 0 21 0.084 ;
    END
  END vo_s[216]
  PIN vo_s[217]
    DIRECTION OUTPUT ;
    USE SIGNAL ;
    PORT
      LAYER M5 ;
        RECT  21.072 0 21.096 0.084 ;
    END
  END vo_s[217]
  PIN vo_s[218]
    DIRECTION OUTPUT ;
    USE SIGNAL ;
    PORT
      LAYER M5 ;
        RECT  21.168 0 21.192 0.084 ;
    END
  END vo_s[218]
  PIN vo_s[219]
    DIRECTION OUTPUT ;
    USE SIGNAL ;
    PORT
      LAYER M5 ;
        RECT  21.264 0 21.288 0.084 ;
    END
  END vo_s[219]
  PIN vo_s[21]
    DIRECTION OUTPUT ;
    USE SIGNAL ;
    PORT
      LAYER M5 ;
        RECT  2.256 0 2.28 0.084 ;
    END
  END vo_s[21]
  PIN vo_s[220]
    DIRECTION OUTPUT ;
    USE SIGNAL ;
    PORT
      LAYER M5 ;
        RECT  21.36 0 21.384 0.084 ;
    END
  END vo_s[220]
  PIN vo_s[221]
    DIRECTION OUTPUT ;
    USE SIGNAL ;
    PORT
      LAYER M5 ;
        RECT  21.456 0 21.48 0.084 ;
    END
  END vo_s[221]
  PIN vo_s[222]
    DIRECTION OUTPUT ;
    USE SIGNAL ;
    PORT
      LAYER M5 ;
        RECT  21.552 0 21.576 0.084 ;
    END
  END vo_s[222]
  PIN vo_s[223]
    DIRECTION OUTPUT ;
    USE SIGNAL ;
    PORT
      LAYER M5 ;
        RECT  21.648 0 21.672 0.084 ;
    END
  END vo_s[223]
  PIN vo_s[224]
    DIRECTION OUTPUT ;
    USE SIGNAL ;
    PORT
      LAYER M5 ;
        RECT  21.744 0 21.768 0.084 ;
    END
  END vo_s[224]
  PIN vo_s[225]
    DIRECTION OUTPUT ;
    USE SIGNAL ;
    PORT
      LAYER M5 ;
        RECT  21.84 0 21.864 0.084 ;
    END
  END vo_s[225]
  PIN vo_s[226]
    DIRECTION OUTPUT ;
    USE SIGNAL ;
    PORT
      LAYER M5 ;
        RECT  21.936 0 21.96 0.084 ;
    END
  END vo_s[226]
  PIN vo_s[227]
    DIRECTION OUTPUT ;
    USE SIGNAL ;
    PORT
      LAYER M5 ;
        RECT  22.032 0 22.056 0.084 ;
    END
  END vo_s[227]
  PIN vo_s[228]
    DIRECTION OUTPUT ;
    USE SIGNAL ;
    PORT
      LAYER M5 ;
        RECT  22.128 0 22.152 0.084 ;
    END
  END vo_s[228]
  PIN vo_s[229]
    DIRECTION OUTPUT ;
    USE SIGNAL ;
    PORT
      LAYER M5 ;
        RECT  22.224 0 22.248 0.084 ;
    END
  END vo_s[229]
  PIN vo_s[22]
    DIRECTION OUTPUT ;
    USE SIGNAL ;
    PORT
      LAYER M5 ;
        RECT  2.352 0 2.376 0.084 ;
    END
  END vo_s[22]
  PIN vo_s[230]
    DIRECTION OUTPUT ;
    USE SIGNAL ;
    PORT
      LAYER M5 ;
        RECT  22.32 0 22.344 0.084 ;
    END
  END vo_s[230]
  PIN vo_s[231]
    DIRECTION OUTPUT ;
    USE SIGNAL ;
    PORT
      LAYER M5 ;
        RECT  22.416 0 22.44 0.084 ;
    END
  END vo_s[231]
  PIN vo_s[232]
    DIRECTION OUTPUT ;
    USE SIGNAL ;
    PORT
      LAYER M5 ;
        RECT  22.512 0 22.536 0.084 ;
    END
  END vo_s[232]
  PIN vo_s[233]
    DIRECTION OUTPUT ;
    USE SIGNAL ;
    PORT
      LAYER M5 ;
        RECT  22.608 0 22.632 0.084 ;
    END
  END vo_s[233]
  PIN vo_s[234]
    DIRECTION OUTPUT ;
    USE SIGNAL ;
    PORT
      LAYER M5 ;
        RECT  22.704 0 22.728 0.084 ;
    END
  END vo_s[234]
  PIN vo_s[235]
    DIRECTION OUTPUT ;
    USE SIGNAL ;
    PORT
      LAYER M5 ;
        RECT  22.8 0 22.824 0.084 ;
    END
  END vo_s[235]
  PIN vo_s[236]
    DIRECTION OUTPUT ;
    USE SIGNAL ;
    PORT
      LAYER M5 ;
        RECT  22.896 0 22.92 0.084 ;
    END
  END vo_s[236]
  PIN vo_s[237]
    DIRECTION OUTPUT ;
    USE SIGNAL ;
    PORT
      LAYER M5 ;
        RECT  22.992 0 23.016 0.084 ;
    END
  END vo_s[237]
  PIN vo_s[238]
    DIRECTION OUTPUT ;
    USE SIGNAL ;
    PORT
      LAYER M5 ;
        RECT  23.088 0 23.112 0.084 ;
    END
  END vo_s[238]
  PIN vo_s[239]
    DIRECTION OUTPUT ;
    USE SIGNAL ;
    PORT
      LAYER M5 ;
        RECT  23.184 0 23.208 0.084 ;
    END
  END vo_s[239]
  PIN vo_s[23]
    DIRECTION OUTPUT ;
    USE SIGNAL ;
    PORT
      LAYER M5 ;
        RECT  2.448 0 2.472 0.084 ;
    END
  END vo_s[23]
  PIN vo_s[240]
    DIRECTION OUTPUT ;
    USE SIGNAL ;
    PORT
      LAYER M5 ;
        RECT  23.28 0 23.304 0.084 ;
    END
  END vo_s[240]
  PIN vo_s[241]
    DIRECTION OUTPUT ;
    USE SIGNAL ;
    PORT
      LAYER M5 ;
        RECT  23.376 0 23.4 0.084 ;
    END
  END vo_s[241]
  PIN vo_s[242]
    DIRECTION OUTPUT ;
    USE SIGNAL ;
    PORT
      LAYER M5 ;
        RECT  23.472 0 23.496 0.084 ;
    END
  END vo_s[242]
  PIN vo_s[243]
    DIRECTION OUTPUT ;
    USE SIGNAL ;
    PORT
      LAYER M5 ;
        RECT  23.568 0 23.592 0.084 ;
    END
  END vo_s[243]
  PIN vo_s[244]
    DIRECTION OUTPUT ;
    USE SIGNAL ;
    PORT
      LAYER M5 ;
        RECT  23.664 0 23.688 0.084 ;
    END
  END vo_s[244]
  PIN vo_s[245]
    DIRECTION OUTPUT ;
    USE SIGNAL ;
    PORT
      LAYER M5 ;
        RECT  23.76 0 23.784 0.084 ;
    END
  END vo_s[245]
  PIN vo_s[246]
    DIRECTION OUTPUT ;
    USE SIGNAL ;
    PORT
      LAYER M5 ;
        RECT  23.856 0 23.88 0.084 ;
    END
  END vo_s[246]
  PIN vo_s[247]
    DIRECTION OUTPUT ;
    USE SIGNAL ;
    PORT
      LAYER M5 ;
        RECT  23.952 0 23.976 0.084 ;
    END
  END vo_s[247]
  PIN vo_s[248]
    DIRECTION OUTPUT ;
    USE SIGNAL ;
    PORT
      LAYER M5 ;
        RECT  24.048 0 24.072 0.084 ;
    END
  END vo_s[248]
  PIN vo_s[249]
    DIRECTION OUTPUT ;
    USE SIGNAL ;
    PORT
      LAYER M5 ;
        RECT  24.144 0 24.168 0.084 ;
    END
  END vo_s[249]
  PIN vo_s[24]
    DIRECTION OUTPUT ;
    USE SIGNAL ;
    PORT
      LAYER M5 ;
        RECT  2.544 0 2.568 0.084 ;
    END
  END vo_s[24]
  PIN vo_s[250]
    DIRECTION OUTPUT ;
    USE SIGNAL ;
    PORT
      LAYER M5 ;
        RECT  24.24 0 24.264 0.084 ;
    END
  END vo_s[250]
  PIN vo_s[251]
    DIRECTION OUTPUT ;
    USE SIGNAL ;
    PORT
      LAYER M5 ;
        RECT  24.336 0 24.36 0.084 ;
    END
  END vo_s[251]
  PIN vo_s[252]
    DIRECTION OUTPUT ;
    USE SIGNAL ;
    PORT
      LAYER M5 ;
        RECT  24.432 0 24.456 0.084 ;
    END
  END vo_s[252]
  PIN vo_s[253]
    DIRECTION OUTPUT ;
    USE SIGNAL ;
    PORT
      LAYER M5 ;
        RECT  24.528 0 24.552 0.084 ;
    END
  END vo_s[253]
  PIN vo_s[254]
    DIRECTION OUTPUT ;
    USE SIGNAL ;
    PORT
      LAYER M5 ;
        RECT  24.624 0 24.648 0.084 ;
    END
  END vo_s[254]
  PIN vo_s[255]
    DIRECTION OUTPUT ;
    USE SIGNAL ;
    PORT
      LAYER M5 ;
        RECT  24.72 0 24.744 0.084 ;
    END
  END vo_s[255]
  PIN vo_s[256]
    DIRECTION OUTPUT ;
    USE SIGNAL ;
    PORT
      LAYER M5 ;
        RECT  24.816 0 24.84 0.084 ;
    END
  END vo_s[256]
  PIN vo_s[257]
    DIRECTION OUTPUT ;
    USE SIGNAL ;
    PORT
      LAYER M5 ;
        RECT  24.912 0 24.936 0.084 ;
    END
  END vo_s[257]
  PIN vo_s[258]
    DIRECTION OUTPUT ;
    USE SIGNAL ;
    PORT
      LAYER M5 ;
        RECT  25.008 0 25.032 0.084 ;
    END
  END vo_s[258]
  PIN vo_s[259]
    DIRECTION OUTPUT ;
    USE SIGNAL ;
    PORT
      LAYER M5 ;
        RECT  25.104 0 25.128 0.084 ;
    END
  END vo_s[259]
  PIN vo_s[25]
    DIRECTION OUTPUT ;
    USE SIGNAL ;
    PORT
      LAYER M5 ;
        RECT  2.64 0 2.664 0.084 ;
    END
  END vo_s[25]
  PIN vo_s[260]
    DIRECTION OUTPUT ;
    USE SIGNAL ;
    PORT
      LAYER M5 ;
        RECT  25.2 0 25.224 0.084 ;
    END
  END vo_s[260]
  PIN vo_s[261]
    DIRECTION OUTPUT ;
    USE SIGNAL ;
    PORT
      LAYER M5 ;
        RECT  25.296 0 25.32 0.084 ;
    END
  END vo_s[261]
  PIN vo_s[262]
    DIRECTION OUTPUT ;
    USE SIGNAL ;
    PORT
      LAYER M5 ;
        RECT  25.392 0 25.416 0.084 ;
    END
  END vo_s[262]
  PIN vo_s[263]
    DIRECTION OUTPUT ;
    USE SIGNAL ;
    PORT
      LAYER M5 ;
        RECT  25.488 0 25.512 0.084 ;
    END
  END vo_s[263]
  PIN vo_s[264]
    DIRECTION OUTPUT ;
    USE SIGNAL ;
    PORT
      LAYER M5 ;
        RECT  25.584 0 25.608 0.084 ;
    END
  END vo_s[264]
  PIN vo_s[265]
    DIRECTION OUTPUT ;
    USE SIGNAL ;
    PORT
      LAYER M5 ;
        RECT  25.68 0 25.704 0.084 ;
    END
  END vo_s[265]
  PIN vo_s[266]
    DIRECTION OUTPUT ;
    USE SIGNAL ;
    PORT
      LAYER M5 ;
        RECT  25.776 0 25.8 0.084 ;
    END
  END vo_s[266]
  PIN vo_s[267]
    DIRECTION OUTPUT ;
    USE SIGNAL ;
    PORT
      LAYER M5 ;
        RECT  25.872 0 25.896 0.084 ;
    END
  END vo_s[267]
  PIN vo_s[268]
    DIRECTION OUTPUT ;
    USE SIGNAL ;
    PORT
      LAYER M5 ;
        RECT  25.968 0 25.992 0.084 ;
    END
  END vo_s[268]
  PIN vo_s[269]
    DIRECTION OUTPUT ;
    USE SIGNAL ;
    PORT
      LAYER M5 ;
        RECT  26.064 0 26.088 0.084 ;
    END
  END vo_s[269]
  PIN vo_s[26]
    DIRECTION OUTPUT ;
    USE SIGNAL ;
    PORT
      LAYER M5 ;
        RECT  2.736 0 2.76 0.084 ;
    END
  END vo_s[26]
  PIN vo_s[270]
    DIRECTION OUTPUT ;
    USE SIGNAL ;
    PORT
      LAYER M5 ;
        RECT  26.16 0 26.184 0.084 ;
    END
  END vo_s[270]
  PIN vo_s[271]
    DIRECTION OUTPUT ;
    USE SIGNAL ;
    PORT
      LAYER M5 ;
        RECT  26.256 0 26.28 0.084 ;
    END
  END vo_s[271]
  PIN vo_s[272]
    DIRECTION OUTPUT ;
    USE SIGNAL ;
    PORT
      LAYER M5 ;
        RECT  26.352 0 26.376 0.084 ;
    END
  END vo_s[272]
  PIN vo_s[273]
    DIRECTION OUTPUT ;
    USE SIGNAL ;
    PORT
      LAYER M5 ;
        RECT  26.448 0 26.472 0.084 ;
    END
  END vo_s[273]
  PIN vo_s[274]
    DIRECTION OUTPUT ;
    USE SIGNAL ;
    PORT
      LAYER M5 ;
        RECT  26.544 0 26.568 0.084 ;
    END
  END vo_s[274]
  PIN vo_s[275]
    DIRECTION OUTPUT ;
    USE SIGNAL ;
    PORT
      LAYER M5 ;
        RECT  26.64 0 26.664 0.084 ;
    END
  END vo_s[275]
  PIN vo_s[27]
    DIRECTION OUTPUT ;
    USE SIGNAL ;
    PORT
      LAYER M5 ;
        RECT  2.832 0 2.856 0.084 ;
    END
  END vo_s[27]
  PIN vo_s[28]
    DIRECTION OUTPUT ;
    USE SIGNAL ;
    PORT
      LAYER M5 ;
        RECT  2.928 0 2.952 0.084 ;
    END
  END vo_s[28]
  PIN vo_s[29]
    DIRECTION OUTPUT ;
    USE SIGNAL ;
    PORT
      LAYER M5 ;
        RECT  3.024 0 3.048 0.084 ;
    END
  END vo_s[29]
  PIN vo_s[2]
    DIRECTION OUTPUT ;
    USE SIGNAL ;
    PORT
      LAYER M5 ;
        RECT  0.432 0 0.456 0.084 ;
    END
  END vo_s[2]
  PIN vo_s[30]
    DIRECTION OUTPUT ;
    USE SIGNAL ;
    PORT
      LAYER M5 ;
        RECT  3.12 0 3.144 0.084 ;
    END
  END vo_s[30]
  PIN vo_s[31]
    DIRECTION OUTPUT ;
    USE SIGNAL ;
    PORT
      LAYER M5 ;
        RECT  3.216 0 3.24 0.084 ;
    END
  END vo_s[31]
  PIN vo_s[32]
    DIRECTION OUTPUT ;
    USE SIGNAL ;
    PORT
      LAYER M5 ;
        RECT  3.312 0 3.336 0.084 ;
    END
  END vo_s[32]
  PIN vo_s[33]
    DIRECTION OUTPUT ;
    USE SIGNAL ;
    PORT
      LAYER M5 ;
        RECT  3.408 0 3.432 0.084 ;
    END
  END vo_s[33]
  PIN vo_s[34]
    DIRECTION OUTPUT ;
    USE SIGNAL ;
    PORT
      LAYER M5 ;
        RECT  3.504 0 3.528 0.084 ;
    END
  END vo_s[34]
  PIN vo_s[35]
    DIRECTION OUTPUT ;
    USE SIGNAL ;
    PORT
      LAYER M5 ;
        RECT  3.6 0 3.624 0.084 ;
    END
  END vo_s[35]
  PIN vo_s[36]
    DIRECTION OUTPUT ;
    USE SIGNAL ;
    PORT
      LAYER M5 ;
        RECT  3.696 0 3.72 0.084 ;
    END
  END vo_s[36]
  PIN vo_s[37]
    DIRECTION OUTPUT ;
    USE SIGNAL ;
    PORT
      LAYER M5 ;
        RECT  3.792 0 3.816 0.084 ;
    END
  END vo_s[37]
  PIN vo_s[38]
    DIRECTION OUTPUT ;
    USE SIGNAL ;
    PORT
      LAYER M5 ;
        RECT  3.888 0 3.912 0.084 ;
    END
  END vo_s[38]
  PIN vo_s[39]
    DIRECTION OUTPUT ;
    USE SIGNAL ;
    PORT
      LAYER M5 ;
        RECT  3.984 0 4.008 0.084 ;
    END
  END vo_s[39]
  PIN vo_s[3]
    DIRECTION OUTPUT ;
    USE SIGNAL ;
    PORT
      LAYER M5 ;
        RECT  0.528 0 0.552 0.084 ;
    END
  END vo_s[3]
  PIN vo_s[40]
    DIRECTION OUTPUT ;
    USE SIGNAL ;
    PORT
      LAYER M5 ;
        RECT  4.08 0 4.104 0.084 ;
    END
  END vo_s[40]
  PIN vo_s[41]
    DIRECTION OUTPUT ;
    USE SIGNAL ;
    PORT
      LAYER M5 ;
        RECT  4.176 0 4.2 0.084 ;
    END
  END vo_s[41]
  PIN vo_s[42]
    DIRECTION OUTPUT ;
    USE SIGNAL ;
    PORT
      LAYER M5 ;
        RECT  4.272 0 4.296 0.084 ;
    END
  END vo_s[42]
  PIN vo_s[43]
    DIRECTION OUTPUT ;
    USE SIGNAL ;
    PORT
      LAYER M5 ;
        RECT  4.368 0 4.392 0.084 ;
    END
  END vo_s[43]
  PIN vo_s[44]
    DIRECTION OUTPUT ;
    USE SIGNAL ;
    PORT
      LAYER M5 ;
        RECT  4.464 0 4.488 0.084 ;
    END
  END vo_s[44]
  PIN vo_s[45]
    DIRECTION OUTPUT ;
    USE SIGNAL ;
    PORT
      LAYER M5 ;
        RECT  4.56 0 4.584 0.084 ;
    END
  END vo_s[45]
  PIN vo_s[46]
    DIRECTION OUTPUT ;
    USE SIGNAL ;
    PORT
      LAYER M5 ;
        RECT  4.656 0 4.68 0.084 ;
    END
  END vo_s[46]
  PIN vo_s[47]
    DIRECTION OUTPUT ;
    USE SIGNAL ;
    PORT
      LAYER M5 ;
        RECT  4.752 0 4.776 0.084 ;
    END
  END vo_s[47]
  PIN vo_s[48]
    DIRECTION OUTPUT ;
    USE SIGNAL ;
    PORT
      LAYER M5 ;
        RECT  4.848 0 4.872 0.084 ;
    END
  END vo_s[48]
  PIN vo_s[49]
    DIRECTION OUTPUT ;
    USE SIGNAL ;
    PORT
      LAYER M5 ;
        RECT  4.944 0 4.968 0.084 ;
    END
  END vo_s[49]
  PIN vo_s[4]
    DIRECTION OUTPUT ;
    USE SIGNAL ;
    PORT
      LAYER M5 ;
        RECT  0.624 0 0.648 0.084 ;
    END
  END vo_s[4]
  PIN vo_s[50]
    DIRECTION OUTPUT ;
    USE SIGNAL ;
    PORT
      LAYER M5 ;
        RECT  5.04 0 5.064 0.084 ;
    END
  END vo_s[50]
  PIN vo_s[51]
    DIRECTION OUTPUT ;
    USE SIGNAL ;
    PORT
      LAYER M5 ;
        RECT  5.136 0 5.16 0.084 ;
    END
  END vo_s[51]
  PIN vo_s[52]
    DIRECTION OUTPUT ;
    USE SIGNAL ;
    PORT
      LAYER M5 ;
        RECT  5.232 0 5.256 0.084 ;
    END
  END vo_s[52]
  PIN vo_s[53]
    DIRECTION OUTPUT ;
    USE SIGNAL ;
    PORT
      LAYER M5 ;
        RECT  5.328 0 5.352 0.084 ;
    END
  END vo_s[53]
  PIN vo_s[54]
    DIRECTION OUTPUT ;
    USE SIGNAL ;
    PORT
      LAYER M5 ;
        RECT  5.424 0 5.448 0.084 ;
    END
  END vo_s[54]
  PIN vo_s[55]
    DIRECTION OUTPUT ;
    USE SIGNAL ;
    PORT
      LAYER M5 ;
        RECT  5.52 0 5.544 0.084 ;
    END
  END vo_s[55]
  PIN vo_s[56]
    DIRECTION OUTPUT ;
    USE SIGNAL ;
    PORT
      LAYER M5 ;
        RECT  5.616 0 5.64 0.084 ;
    END
  END vo_s[56]
  PIN vo_s[57]
    DIRECTION OUTPUT ;
    USE SIGNAL ;
    PORT
      LAYER M5 ;
        RECT  5.712 0 5.736 0.084 ;
    END
  END vo_s[57]
  PIN vo_s[58]
    DIRECTION OUTPUT ;
    USE SIGNAL ;
    PORT
      LAYER M5 ;
        RECT  5.808 0 5.832 0.084 ;
    END
  END vo_s[58]
  PIN vo_s[59]
    DIRECTION OUTPUT ;
    USE SIGNAL ;
    PORT
      LAYER M5 ;
        RECT  5.904 0 5.928 0.084 ;
    END
  END vo_s[59]
  PIN vo_s[5]
    DIRECTION OUTPUT ;
    USE SIGNAL ;
    PORT
      LAYER M5 ;
        RECT  0.72 0 0.744 0.084 ;
    END
  END vo_s[5]
  PIN vo_s[60]
    DIRECTION OUTPUT ;
    USE SIGNAL ;
    PORT
      LAYER M5 ;
        RECT  6 0 6.024 0.084 ;
    END
  END vo_s[60]
  PIN vo_s[61]
    DIRECTION OUTPUT ;
    USE SIGNAL ;
    PORT
      LAYER M5 ;
        RECT  6.096 0 6.12 0.084 ;
    END
  END vo_s[61]
  PIN vo_s[62]
    DIRECTION OUTPUT ;
    USE SIGNAL ;
    PORT
      LAYER M5 ;
        RECT  6.192 0 6.216 0.084 ;
    END
  END vo_s[62]
  PIN vo_s[63]
    DIRECTION OUTPUT ;
    USE SIGNAL ;
    PORT
      LAYER M5 ;
        RECT  6.288 0 6.312 0.084 ;
    END
  END vo_s[63]
  PIN vo_s[64]
    DIRECTION OUTPUT ;
    USE SIGNAL ;
    PORT
      LAYER M5 ;
        RECT  6.384 0 6.408 0.084 ;
    END
  END vo_s[64]
  PIN vo_s[65]
    DIRECTION OUTPUT ;
    USE SIGNAL ;
    PORT
      LAYER M5 ;
        RECT  6.48 0 6.504 0.084 ;
    END
  END vo_s[65]
  PIN vo_s[66]
    DIRECTION OUTPUT ;
    USE SIGNAL ;
    PORT
      LAYER M5 ;
        RECT  6.576 0 6.6 0.084 ;
    END
  END vo_s[66]
  PIN vo_s[67]
    DIRECTION OUTPUT ;
    USE SIGNAL ;
    PORT
      LAYER M5 ;
        RECT  6.672 0 6.696 0.084 ;
    END
  END vo_s[67]
  PIN vo_s[68]
    DIRECTION OUTPUT ;
    USE SIGNAL ;
    PORT
      LAYER M5 ;
        RECT  6.768 0 6.792 0.084 ;
    END
  END vo_s[68]
  PIN vo_s[69]
    DIRECTION OUTPUT ;
    USE SIGNAL ;
    PORT
      LAYER M5 ;
        RECT  6.864 0 6.888 0.084 ;
    END
  END vo_s[69]
  PIN vo_s[6]
    DIRECTION OUTPUT ;
    USE SIGNAL ;
    PORT
      LAYER M5 ;
        RECT  0.816 0 0.84 0.084 ;
    END
  END vo_s[6]
  PIN vo_s[70]
    DIRECTION OUTPUT ;
    USE SIGNAL ;
    PORT
      LAYER M5 ;
        RECT  6.96 0 6.984 0.084 ;
    END
  END vo_s[70]
  PIN vo_s[71]
    DIRECTION OUTPUT ;
    USE SIGNAL ;
    PORT
      LAYER M5 ;
        RECT  7.056 0 7.08 0.084 ;
    END
  END vo_s[71]
  PIN vo_s[72]
    DIRECTION OUTPUT ;
    USE SIGNAL ;
    PORT
      LAYER M5 ;
        RECT  7.152 0 7.176 0.084 ;
    END
  END vo_s[72]
  PIN vo_s[73]
    DIRECTION OUTPUT ;
    USE SIGNAL ;
    PORT
      LAYER M5 ;
        RECT  7.248 0 7.272 0.084 ;
    END
  END vo_s[73]
  PIN vo_s[74]
    DIRECTION OUTPUT ;
    USE SIGNAL ;
    PORT
      LAYER M5 ;
        RECT  7.344 0 7.368 0.084 ;
    END
  END vo_s[74]
  PIN vo_s[75]
    DIRECTION OUTPUT ;
    USE SIGNAL ;
    PORT
      LAYER M5 ;
        RECT  7.44 0 7.464 0.084 ;
    END
  END vo_s[75]
  PIN vo_s[76]
    DIRECTION OUTPUT ;
    USE SIGNAL ;
    PORT
      LAYER M5 ;
        RECT  7.536 0 7.56 0.084 ;
    END
  END vo_s[76]
  PIN vo_s[77]
    DIRECTION OUTPUT ;
    USE SIGNAL ;
    PORT
      LAYER M5 ;
        RECT  7.632 0 7.656 0.084 ;
    END
  END vo_s[77]
  PIN vo_s[78]
    DIRECTION OUTPUT ;
    USE SIGNAL ;
    PORT
      LAYER M5 ;
        RECT  7.728 0 7.752 0.084 ;
    END
  END vo_s[78]
  PIN vo_s[79]
    DIRECTION OUTPUT ;
    USE SIGNAL ;
    PORT
      LAYER M5 ;
        RECT  7.824 0 7.848 0.084 ;
    END
  END vo_s[79]
  PIN vo_s[7]
    DIRECTION OUTPUT ;
    USE SIGNAL ;
    PORT
      LAYER M5 ;
        RECT  0.912 0 0.936 0.084 ;
    END
  END vo_s[7]
  PIN vo_s[80]
    DIRECTION OUTPUT ;
    USE SIGNAL ;
    PORT
      LAYER M5 ;
        RECT  7.92 0 7.944 0.084 ;
    END
  END vo_s[80]
  PIN vo_s[81]
    DIRECTION OUTPUT ;
    USE SIGNAL ;
    PORT
      LAYER M5 ;
        RECT  8.016 0 8.04 0.084 ;
    END
  END vo_s[81]
  PIN vo_s[82]
    DIRECTION OUTPUT ;
    USE SIGNAL ;
    PORT
      LAYER M5 ;
        RECT  8.112 0 8.136 0.084 ;
    END
  END vo_s[82]
  PIN vo_s[83]
    DIRECTION OUTPUT ;
    USE SIGNAL ;
    PORT
      LAYER M5 ;
        RECT  8.208 0 8.232 0.084 ;
    END
  END vo_s[83]
  PIN vo_s[84]
    DIRECTION OUTPUT ;
    USE SIGNAL ;
    PORT
      LAYER M5 ;
        RECT  8.304 0 8.328 0.084 ;
    END
  END vo_s[84]
  PIN vo_s[85]
    DIRECTION OUTPUT ;
    USE SIGNAL ;
    PORT
      LAYER M5 ;
        RECT  8.4 0 8.424 0.084 ;
    END
  END vo_s[85]
  PIN vo_s[86]
    DIRECTION OUTPUT ;
    USE SIGNAL ;
    PORT
      LAYER M5 ;
        RECT  8.496 0 8.52 0.084 ;
    END
  END vo_s[86]
  PIN vo_s[87]
    DIRECTION OUTPUT ;
    USE SIGNAL ;
    PORT
      LAYER M5 ;
        RECT  8.592 0 8.616 0.084 ;
    END
  END vo_s[87]
  PIN vo_s[88]
    DIRECTION OUTPUT ;
    USE SIGNAL ;
    PORT
      LAYER M5 ;
        RECT  8.688 0 8.712 0.084 ;
    END
  END vo_s[88]
  PIN vo_s[89]
    DIRECTION OUTPUT ;
    USE SIGNAL ;
    PORT
      LAYER M5 ;
        RECT  8.784 0 8.808 0.084 ;
    END
  END vo_s[89]
  PIN vo_s[8]
    DIRECTION OUTPUT ;
    USE SIGNAL ;
    PORT
      LAYER M5 ;
        RECT  1.008 0 1.032 0.084 ;
    END
  END vo_s[8]
  PIN vo_s[90]
    DIRECTION OUTPUT ;
    USE SIGNAL ;
    PORT
      LAYER M5 ;
        RECT  8.88 0 8.904 0.084 ;
    END
  END vo_s[90]
  PIN vo_s[91]
    DIRECTION OUTPUT ;
    USE SIGNAL ;
    PORT
      LAYER M5 ;
        RECT  8.976 0 9 0.084 ;
    END
  END vo_s[91]
  PIN vo_s[92]
    DIRECTION OUTPUT ;
    USE SIGNAL ;
    PORT
      LAYER M5 ;
        RECT  9.072 0 9.096 0.084 ;
    END
  END vo_s[92]
  PIN vo_s[93]
    DIRECTION OUTPUT ;
    USE SIGNAL ;
    PORT
      LAYER M5 ;
        RECT  9.168 0 9.192 0.084 ;
    END
  END vo_s[93]
  PIN vo_s[94]
    DIRECTION OUTPUT ;
    USE SIGNAL ;
    PORT
      LAYER M5 ;
        RECT  9.264 0 9.288 0.084 ;
    END
  END vo_s[94]
  PIN vo_s[95]
    DIRECTION OUTPUT ;
    USE SIGNAL ;
    PORT
      LAYER M5 ;
        RECT  9.36 0 9.384 0.084 ;
    END
  END vo_s[95]
  PIN vo_s[96]
    DIRECTION OUTPUT ;
    USE SIGNAL ;
    PORT
      LAYER M5 ;
        RECT  9.456 0 9.48 0.084 ;
    END
  END vo_s[96]
  PIN vo_s[97]
    DIRECTION OUTPUT ;
    USE SIGNAL ;
    PORT
      LAYER M5 ;
        RECT  9.552 0 9.576 0.084 ;
    END
  END vo_s[97]
  PIN vo_s[98]
    DIRECTION OUTPUT ;
    USE SIGNAL ;
    PORT
      LAYER M5 ;
        RECT  9.648 0 9.672 0.084 ;
    END
  END vo_s[98]
  PIN vo_s[99]
    DIRECTION OUTPUT ;
    USE SIGNAL ;
    PORT
      LAYER M5 ;
        RECT  9.744 0 9.768 0.084 ;
    END
  END vo_s[99]
  PIN vo_s[9]
    DIRECTION OUTPUT ;
    USE SIGNAL ;
    PORT
      LAYER M5 ;
        RECT  1.104 0 1.128 0.084 ;
    END
  END vo_s[9]
  PIN w_b[0]
    DIRECTION OUTPUT ;
    USE SIGNAL ;
    PORT
      LAYER M5 ;
        RECT  148.176 172.716 148.2 172.8 ;
    END
  END w_b[0]
  PIN w_b[100]
    DIRECTION OUTPUT ;
    USE SIGNAL ;
    PORT
      LAYER M5 ;
        RECT  217.968 172.716 217.992 172.8 ;
    END
  END w_b[100]
  PIN w_b[101]
    DIRECTION OUTPUT ;
    USE SIGNAL ;
    PORT
      LAYER M5 ;
        RECT  218.064 172.716 218.088 172.8 ;
    END
  END w_b[101]
  PIN w_b[102]
    DIRECTION OUTPUT ;
    USE SIGNAL ;
    PORT
      LAYER M5 ;
        RECT  218.16 172.716 218.184 172.8 ;
    END
  END w_b[102]
  PIN w_b[103]
    DIRECTION OUTPUT ;
    USE SIGNAL ;
    PORT
      LAYER M5 ;
        RECT  218.256 172.716 218.28 172.8 ;
    END
  END w_b[103]
  PIN w_b[104]
    DIRECTION OUTPUT ;
    USE SIGNAL ;
    PORT
      LAYER M5 ;
        RECT  218.352 172.716 218.376 172.8 ;
    END
  END w_b[104]
  PIN w_b[105]
    DIRECTION OUTPUT ;
    USE SIGNAL ;
    PORT
      LAYER M5 ;
        RECT  218.448 172.716 218.472 172.8 ;
    END
  END w_b[105]
  PIN w_b[106]
    DIRECTION OUTPUT ;
    USE SIGNAL ;
    PORT
      LAYER M5 ;
        RECT  218.544 172.716 218.568 172.8 ;
    END
  END w_b[106]
  PIN w_b[107]
    DIRECTION OUTPUT ;
    USE SIGNAL ;
    PORT
      LAYER M5 ;
        RECT  218.64 172.716 218.664 172.8 ;
    END
  END w_b[107]
  PIN w_b[108]
    DIRECTION OUTPUT ;
    USE SIGNAL ;
    PORT
      LAYER M5 ;
        RECT  218.736 172.716 218.76 172.8 ;
    END
  END w_b[108]
  PIN w_b[109]
    DIRECTION OUTPUT ;
    USE SIGNAL ;
    PORT
      LAYER M5 ;
        RECT  218.832 172.716 218.856 172.8 ;
    END
  END w_b[109]
  PIN w_b[10]
    DIRECTION OUTPUT ;
    USE SIGNAL ;
    PORT
      LAYER M5 ;
        RECT  212.112 172.716 212.136 172.8 ;
    END
  END w_b[10]
  PIN w_b[110]
    DIRECTION OUTPUT ;
    USE SIGNAL ;
    PORT
      LAYER M5 ;
        RECT  218.928 172.716 218.952 172.8 ;
    END
  END w_b[110]
  PIN w_b[111]
    DIRECTION OUTPUT ;
    USE SIGNAL ;
    PORT
      LAYER M5 ;
        RECT  219.024 172.716 219.048 172.8 ;
    END
  END w_b[111]
  PIN w_b[112]
    DIRECTION OUTPUT ;
    USE SIGNAL ;
    PORT
      LAYER M5 ;
        RECT  219.12 172.716 219.144 172.8 ;
    END
  END w_b[112]
  PIN w_b[113]
    DIRECTION OUTPUT ;
    USE SIGNAL ;
    PORT
      LAYER M5 ;
        RECT  219.216 172.716 219.24 172.8 ;
    END
  END w_b[113]
  PIN w_b[114]
    DIRECTION OUTPUT ;
    USE SIGNAL ;
    PORT
      LAYER M5 ;
        RECT  219.312 172.716 219.336 172.8 ;
    END
  END w_b[114]
  PIN w_b[115]
    DIRECTION OUTPUT ;
    USE SIGNAL ;
    PORT
      LAYER M5 ;
        RECT  219.408 172.716 219.432 172.8 ;
    END
  END w_b[115]
  PIN w_b[116]
    DIRECTION OUTPUT ;
    USE SIGNAL ;
    PORT
      LAYER M5 ;
        RECT  219.504 172.716 219.528 172.8 ;
    END
  END w_b[116]
  PIN w_b[117]
    DIRECTION OUTPUT ;
    USE SIGNAL ;
    PORT
      LAYER M5 ;
        RECT  219.6 172.716 219.624 172.8 ;
    END
  END w_b[117]
  PIN w_b[118]
    DIRECTION OUTPUT ;
    USE SIGNAL ;
    PORT
      LAYER M5 ;
        RECT  219.696 172.716 219.72 172.8 ;
    END
  END w_b[118]
  PIN w_b[119]
    DIRECTION OUTPUT ;
    USE SIGNAL ;
    PORT
      LAYER M5 ;
        RECT  219.792 172.716 219.816 172.8 ;
    END
  END w_b[119]
  PIN w_b[11]
    DIRECTION OUTPUT ;
    USE SIGNAL ;
    PORT
      LAYER M5 ;
        RECT  212.208 172.716 212.232 172.8 ;
    END
  END w_b[11]
  PIN w_b[120]
    DIRECTION OUTPUT ;
    USE SIGNAL ;
    PORT
      LAYER M5 ;
        RECT  219.888 172.716 219.912 172.8 ;
    END
  END w_b[120]
  PIN w_b[121]
    DIRECTION OUTPUT ;
    USE SIGNAL ;
    PORT
      LAYER M5 ;
        RECT  219.984 172.716 220.008 172.8 ;
    END
  END w_b[121]
  PIN w_b[122]
    DIRECTION OUTPUT ;
    USE SIGNAL ;
    PORT
      LAYER M5 ;
        RECT  220.08 172.716 220.104 172.8 ;
    END
  END w_b[122]
  PIN w_b[123]
    DIRECTION OUTPUT ;
    USE SIGNAL ;
    PORT
      LAYER M5 ;
        RECT  220.176 172.716 220.2 172.8 ;
    END
  END w_b[123]
  PIN w_b[124]
    DIRECTION OUTPUT ;
    USE SIGNAL ;
    PORT
      LAYER M5 ;
        RECT  220.272 172.716 220.296 172.8 ;
    END
  END w_b[124]
  PIN w_b[125]
    DIRECTION OUTPUT ;
    USE SIGNAL ;
    PORT
      LAYER M5 ;
        RECT  220.368 172.716 220.392 172.8 ;
    END
  END w_b[125]
  PIN w_b[126]
    DIRECTION OUTPUT ;
    USE SIGNAL ;
    PORT
      LAYER M5 ;
        RECT  223.536 172.716 223.56 172.8 ;
    END
  END w_b[126]
  PIN w_b[127]
    DIRECTION OUTPUT ;
    USE SIGNAL ;
    PORT
      LAYER M5 ;
        RECT  223.632 172.716 223.656 172.8 ;
    END
  END w_b[127]
  PIN w_b[128]
    DIRECTION OUTPUT ;
    USE SIGNAL ;
    PORT
      LAYER M5 ;
        RECT  223.728 172.716 223.752 172.8 ;
    END
  END w_b[128]
  PIN w_b[129]
    DIRECTION OUTPUT ;
    USE SIGNAL ;
    PORT
      LAYER M5 ;
        RECT  223.824 172.716 223.848 172.8 ;
    END
  END w_b[129]
  PIN w_b[12]
    DIRECTION OUTPUT ;
    USE SIGNAL ;
    PORT
      LAYER M5 ;
        RECT  212.304 172.716 212.328 172.8 ;
    END
  END w_b[12]
  PIN w_b[130]
    DIRECTION OUTPUT ;
    USE SIGNAL ;
    PORT
      LAYER M5 ;
        RECT  223.92 172.716 223.944 172.8 ;
    END
  END w_b[130]
  PIN w_b[131]
    DIRECTION OUTPUT ;
    USE SIGNAL ;
    PORT
      LAYER M5 ;
        RECT  224.016 172.716 224.04 172.8 ;
    END
  END w_b[131]
  PIN w_b[132]
    DIRECTION OUTPUT ;
    USE SIGNAL ;
    PORT
      LAYER M5 ;
        RECT  224.112 172.716 224.136 172.8 ;
    END
  END w_b[132]
  PIN w_b[133]
    DIRECTION OUTPUT ;
    USE SIGNAL ;
    PORT
      LAYER M5 ;
        RECT  224.208 172.716 224.232 172.8 ;
    END
  END w_b[133]
  PIN w_b[134]
    DIRECTION OUTPUT ;
    USE SIGNAL ;
    PORT
      LAYER M5 ;
        RECT  224.304 172.716 224.328 172.8 ;
    END
  END w_b[134]
  PIN w_b[135]
    DIRECTION OUTPUT ;
    USE SIGNAL ;
    PORT
      LAYER M5 ;
        RECT  224.4 172.716 224.424 172.8 ;
    END
  END w_b[135]
  PIN w_b[136]
    DIRECTION OUTPUT ;
    USE SIGNAL ;
    PORT
      LAYER M5 ;
        RECT  224.496 172.716 224.52 172.8 ;
    END
  END w_b[136]
  PIN w_b[137]
    DIRECTION OUTPUT ;
    USE SIGNAL ;
    PORT
      LAYER M5 ;
        RECT  224.592 172.716 224.616 172.8 ;
    END
  END w_b[137]
  PIN w_b[138]
    DIRECTION OUTPUT ;
    USE SIGNAL ;
    PORT
      LAYER M5 ;
        RECT  224.688 172.716 224.712 172.8 ;
    END
  END w_b[138]
  PIN w_b[139]
    DIRECTION OUTPUT ;
    USE SIGNAL ;
    PORT
      LAYER M5 ;
        RECT  224.784 172.716 224.808 172.8 ;
    END
  END w_b[139]
  PIN w_b[13]
    DIRECTION OUTPUT ;
    USE SIGNAL ;
    PORT
      LAYER M5 ;
        RECT  212.4 172.716 212.424 172.8 ;
    END
  END w_b[13]
  PIN w_b[140]
    DIRECTION OUTPUT ;
    USE SIGNAL ;
    PORT
      LAYER M5 ;
        RECT  224.88 172.716 224.904 172.8 ;
    END
  END w_b[140]
  PIN w_b[141]
    DIRECTION OUTPUT ;
    USE SIGNAL ;
    PORT
      LAYER M5 ;
        RECT  224.976 172.716 225 172.8 ;
    END
  END w_b[141]
  PIN w_b[142]
    DIRECTION OUTPUT ;
    USE SIGNAL ;
    PORT
      LAYER M5 ;
        RECT  225.072 172.716 225.096 172.8 ;
    END
  END w_b[142]
  PIN w_b[143]
    DIRECTION OUTPUT ;
    USE SIGNAL ;
    PORT
      LAYER M5 ;
        RECT  225.168 172.716 225.192 172.8 ;
    END
  END w_b[143]
  PIN w_b[144]
    DIRECTION OUTPUT ;
    USE SIGNAL ;
    PORT
      LAYER M5 ;
        RECT  225.264 172.716 225.288 172.8 ;
    END
  END w_b[144]
  PIN w_b[145]
    DIRECTION OUTPUT ;
    USE SIGNAL ;
    PORT
      LAYER M5 ;
        RECT  225.36 172.716 225.384 172.8 ;
    END
  END w_b[145]
  PIN w_b[146]
    DIRECTION OUTPUT ;
    USE SIGNAL ;
    PORT
      LAYER M5 ;
        RECT  225.456 172.716 225.48 172.8 ;
    END
  END w_b[146]
  PIN w_b[147]
    DIRECTION OUTPUT ;
    USE SIGNAL ;
    PORT
      LAYER M5 ;
        RECT  225.552 172.716 225.576 172.8 ;
    END
  END w_b[147]
  PIN w_b[148]
    DIRECTION OUTPUT ;
    USE SIGNAL ;
    PORT
      LAYER M5 ;
        RECT  225.648 172.716 225.672 172.8 ;
    END
  END w_b[148]
  PIN w_b[149]
    DIRECTION OUTPUT ;
    USE SIGNAL ;
    PORT
      LAYER M5 ;
        RECT  225.744 172.716 225.768 172.8 ;
    END
  END w_b[149]
  PIN w_b[14]
    DIRECTION OUTPUT ;
    USE SIGNAL ;
    PORT
      LAYER M5 ;
        RECT  212.496 172.716 212.52 172.8 ;
    END
  END w_b[14]
  PIN w_b[150]
    DIRECTION OUTPUT ;
    USE SIGNAL ;
    PORT
      LAYER M5 ;
        RECT  225.84 172.716 225.864 172.8 ;
    END
  END w_b[150]
  PIN w_b[151]
    DIRECTION OUTPUT ;
    USE SIGNAL ;
    PORT
      LAYER M5 ;
        RECT  225.936 172.716 225.96 172.8 ;
    END
  END w_b[151]
  PIN w_b[152]
    DIRECTION OUTPUT ;
    USE SIGNAL ;
    PORT
      LAYER M5 ;
        RECT  226.032 172.716 226.056 172.8 ;
    END
  END w_b[152]
  PIN w_b[153]
    DIRECTION OUTPUT ;
    USE SIGNAL ;
    PORT
      LAYER M5 ;
        RECT  226.128 172.716 226.152 172.8 ;
    END
  END w_b[153]
  PIN w_b[154]
    DIRECTION OUTPUT ;
    USE SIGNAL ;
    PORT
      LAYER M5 ;
        RECT  226.224 172.716 226.248 172.8 ;
    END
  END w_b[154]
  PIN w_b[155]
    DIRECTION OUTPUT ;
    USE SIGNAL ;
    PORT
      LAYER M5 ;
        RECT  226.32 172.716 226.344 172.8 ;
    END
  END w_b[155]
  PIN w_b[156]
    DIRECTION OUTPUT ;
    USE SIGNAL ;
    PORT
      LAYER M5 ;
        RECT  226.416 172.716 226.44 172.8 ;
    END
  END w_b[156]
  PIN w_b[157]
    DIRECTION OUTPUT ;
    USE SIGNAL ;
    PORT
      LAYER M5 ;
        RECT  226.512 172.716 226.536 172.8 ;
    END
  END w_b[157]
  PIN w_b[158]
    DIRECTION OUTPUT ;
    USE SIGNAL ;
    PORT
      LAYER M5 ;
        RECT  214.32 172.716 214.344 172.8 ;
    END
  END w_b[158]
  PIN w_b[159]
    DIRECTION OUTPUT ;
    USE SIGNAL ;
    PORT
      LAYER M5 ;
        RECT  214.416 172.716 214.44 172.8 ;
    END
  END w_b[159]
  PIN w_b[15]
    DIRECTION OUTPUT ;
    USE SIGNAL ;
    PORT
      LAYER M5 ;
        RECT  212.592 172.716 212.616 172.8 ;
    END
  END w_b[15]
  PIN w_b[160]
    DIRECTION OUTPUT ;
    USE SIGNAL ;
    PORT
      LAYER M5 ;
        RECT  214.512 172.716 214.536 172.8 ;
    END
  END w_b[160]
  PIN w_b[161]
    DIRECTION OUTPUT ;
    USE SIGNAL ;
    PORT
      LAYER M5 ;
        RECT  214.608 172.716 214.632 172.8 ;
    END
  END w_b[161]
  PIN w_b[162]
    DIRECTION OUTPUT ;
    USE SIGNAL ;
    PORT
      LAYER M5 ;
        RECT  214.704 172.716 214.728 172.8 ;
    END
  END w_b[162]
  PIN w_b[163]
    DIRECTION OUTPUT ;
    USE SIGNAL ;
    PORT
      LAYER M5 ;
        RECT  214.8 172.716 214.824 172.8 ;
    END
  END w_b[163]
  PIN w_b[164]
    DIRECTION OUTPUT ;
    USE SIGNAL ;
    PORT
      LAYER M5 ;
        RECT  214.896 172.716 214.92 172.8 ;
    END
  END w_b[164]
  PIN w_b[165]
    DIRECTION OUTPUT ;
    USE SIGNAL ;
    PORT
      LAYER M5 ;
        RECT  214.992 172.716 215.016 172.8 ;
    END
  END w_b[165]
  PIN w_b[166]
    DIRECTION OUTPUT ;
    USE SIGNAL ;
    PORT
      LAYER M5 ;
        RECT  215.088 172.716 215.112 172.8 ;
    END
  END w_b[166]
  PIN w_b[167]
    DIRECTION OUTPUT ;
    USE SIGNAL ;
    PORT
      LAYER M5 ;
        RECT  215.184 172.716 215.208 172.8 ;
    END
  END w_b[167]
  PIN w_b[168]
    DIRECTION OUTPUT ;
    USE SIGNAL ;
    PORT
      LAYER M5 ;
        RECT  215.28 172.716 215.304 172.8 ;
    END
  END w_b[168]
  PIN w_b[169]
    DIRECTION OUTPUT ;
    USE SIGNAL ;
    PORT
      LAYER M5 ;
        RECT  215.376 172.716 215.4 172.8 ;
    END
  END w_b[169]
  PIN w_b[16]
    DIRECTION OUTPUT ;
    USE SIGNAL ;
    PORT
      LAYER M5 ;
        RECT  212.688 172.716 212.712 172.8 ;
    END
  END w_b[16]
  PIN w_b[17]
    DIRECTION OUTPUT ;
    USE SIGNAL ;
    PORT
      LAYER M5 ;
        RECT  212.784 172.716 212.808 172.8 ;
    END
  END w_b[17]
  PIN w_b[18]
    DIRECTION OUTPUT ;
    USE SIGNAL ;
    PORT
      LAYER M5 ;
        RECT  212.88 172.716 212.904 172.8 ;
    END
  END w_b[18]
  PIN w_b[19]
    DIRECTION OUTPUT ;
    USE SIGNAL ;
    PORT
      LAYER M5 ;
        RECT  212.976 172.716 213 172.8 ;
    END
  END w_b[19]
  PIN w_b[1]
    DIRECTION OUTPUT ;
    USE SIGNAL ;
    PORT
      LAYER M5 ;
        RECT  149.04 172.716 149.064 172.8 ;
    END
  END w_b[1]
  PIN w_b[20]
    DIRECTION OUTPUT ;
    USE SIGNAL ;
    PORT
      LAYER M5 ;
        RECT  213.072 172.716 213.096 172.8 ;
    END
  END w_b[20]
  PIN w_b[21]
    DIRECTION OUTPUT ;
    USE SIGNAL ;
    PORT
      LAYER M5 ;
        RECT  213.168 172.716 213.192 172.8 ;
    END
  END w_b[21]
  PIN w_b[22]
    DIRECTION OUTPUT ;
    USE SIGNAL ;
    PORT
      LAYER M5 ;
        RECT  213.36 172.716 213.384 172.8 ;
    END
  END w_b[22]
  PIN w_b[23]
    DIRECTION OUTPUT ;
    USE SIGNAL ;
    PORT
      LAYER M5 ;
        RECT  213.648 172.716 213.672 172.8 ;
    END
  END w_b[23]
  PIN w_b[24]
    DIRECTION OUTPUT ;
    USE SIGNAL ;
    PORT
      LAYER M5 ;
        RECT  213.744 172.716 213.768 172.8 ;
    END
  END w_b[24]
  PIN w_b[25]
    DIRECTION OUTPUT ;
    USE SIGNAL ;
    PORT
      LAYER M5 ;
        RECT  213.84 172.716 213.864 172.8 ;
    END
  END w_b[25]
  PIN w_b[26]
    DIRECTION OUTPUT ;
    USE SIGNAL ;
    PORT
      LAYER M5 ;
        RECT  213.936 172.716 213.96 172.8 ;
    END
  END w_b[26]
  PIN w_b[27]
    DIRECTION OUTPUT ;
    USE SIGNAL ;
    PORT
      LAYER M5 ;
        RECT  214.032 172.716 214.056 172.8 ;
    END
  END w_b[27]
  PIN w_b[28]
    DIRECTION OUTPUT ;
    USE SIGNAL ;
    PORT
      LAYER M5 ;
        RECT  214.128 172.716 214.152 172.8 ;
    END
  END w_b[28]
  PIN w_b[29]
    DIRECTION OUTPUT ;
    USE SIGNAL ;
    PORT
      LAYER M5 ;
        RECT  214.224 172.716 214.248 172.8 ;
    END
  END w_b[29]
  PIN w_b[2]
    DIRECTION OUTPUT ;
    USE SIGNAL ;
    PORT
      LAYER M5 ;
        RECT  149.136 172.716 149.16 172.8 ;
    END
  END w_b[2]
  PIN w_b[30]
    DIRECTION OUTPUT ;
    USE SIGNAL ;
    PORT
      LAYER M5 ;
        RECT  220.464 172.716 220.488 172.8 ;
    END
  END w_b[30]
  PIN w_b[31]
    DIRECTION OUTPUT ;
    USE SIGNAL ;
    PORT
      LAYER M5 ;
        RECT  220.56 172.716 220.584 172.8 ;
    END
  END w_b[31]
  PIN w_b[32]
    DIRECTION OUTPUT ;
    USE SIGNAL ;
    PORT
      LAYER M5 ;
        RECT  220.656 172.716 220.68 172.8 ;
    END
  END w_b[32]
  PIN w_b[33]
    DIRECTION OUTPUT ;
    USE SIGNAL ;
    PORT
      LAYER M5 ;
        RECT  220.752 172.716 220.776 172.8 ;
    END
  END w_b[33]
  PIN w_b[34]
    DIRECTION OUTPUT ;
    USE SIGNAL ;
    PORT
      LAYER M5 ;
        RECT  220.848 172.716 220.872 172.8 ;
    END
  END w_b[34]
  PIN w_b[35]
    DIRECTION OUTPUT ;
    USE SIGNAL ;
    PORT
      LAYER M5 ;
        RECT  220.944 172.716 220.968 172.8 ;
    END
  END w_b[35]
  PIN w_b[36]
    DIRECTION OUTPUT ;
    USE SIGNAL ;
    PORT
      LAYER M5 ;
        RECT  221.04 172.716 221.064 172.8 ;
    END
  END w_b[36]
  PIN w_b[37]
    DIRECTION OUTPUT ;
    USE SIGNAL ;
    PORT
      LAYER M5 ;
        RECT  221.136 172.716 221.16 172.8 ;
    END
  END w_b[37]
  PIN w_b[38]
    DIRECTION OUTPUT ;
    USE SIGNAL ;
    PORT
      LAYER M5 ;
        RECT  221.232 172.716 221.256 172.8 ;
    END
  END w_b[38]
  PIN w_b[39]
    DIRECTION OUTPUT ;
    USE SIGNAL ;
    PORT
      LAYER M5 ;
        RECT  221.328 172.716 221.352 172.8 ;
    END
  END w_b[39]
  PIN w_b[3]
    DIRECTION OUTPUT ;
    USE SIGNAL ;
    PORT
      LAYER M5 ;
        RECT  149.232 172.716 149.256 172.8 ;
    END
  END w_b[3]
  PIN w_b[40]
    DIRECTION OUTPUT ;
    USE SIGNAL ;
    PORT
      LAYER M5 ;
        RECT  221.424 172.716 221.448 172.8 ;
    END
  END w_b[40]
  PIN w_b[41]
    DIRECTION OUTPUT ;
    USE SIGNAL ;
    PORT
      LAYER M5 ;
        RECT  221.52 172.716 221.544 172.8 ;
    END
  END w_b[41]
  PIN w_b[42]
    DIRECTION OUTPUT ;
    USE SIGNAL ;
    PORT
      LAYER M5 ;
        RECT  221.616 172.716 221.64 172.8 ;
    END
  END w_b[42]
  PIN w_b[43]
    DIRECTION OUTPUT ;
    USE SIGNAL ;
    PORT
      LAYER M5 ;
        RECT  221.712 172.716 221.736 172.8 ;
    END
  END w_b[43]
  PIN w_b[44]
    DIRECTION OUTPUT ;
    USE SIGNAL ;
    PORT
      LAYER M5 ;
        RECT  221.808 172.716 221.832 172.8 ;
    END
  END w_b[44]
  PIN w_b[45]
    DIRECTION OUTPUT ;
    USE SIGNAL ;
    PORT
      LAYER M5 ;
        RECT  221.904 172.716 221.928 172.8 ;
    END
  END w_b[45]
  PIN w_b[46]
    DIRECTION OUTPUT ;
    USE SIGNAL ;
    PORT
      LAYER M5 ;
        RECT  222 172.716 222.024 172.8 ;
    END
  END w_b[46]
  PIN w_b[47]
    DIRECTION OUTPUT ;
    USE SIGNAL ;
    PORT
      LAYER M5 ;
        RECT  222.096 172.716 222.12 172.8 ;
    END
  END w_b[47]
  PIN w_b[48]
    DIRECTION OUTPUT ;
    USE SIGNAL ;
    PORT
      LAYER M5 ;
        RECT  222.192 172.716 222.216 172.8 ;
    END
  END w_b[48]
  PIN w_b[49]
    DIRECTION OUTPUT ;
    USE SIGNAL ;
    PORT
      LAYER M5 ;
        RECT  222.288 172.716 222.312 172.8 ;
    END
  END w_b[49]
  PIN w_b[4]
    DIRECTION OUTPUT ;
    USE SIGNAL ;
    PORT
      LAYER M5 ;
        RECT  149.328 172.716 149.352 172.8 ;
    END
  END w_b[4]
  PIN w_b[50]
    DIRECTION OUTPUT ;
    USE SIGNAL ;
    PORT
      LAYER M5 ;
        RECT  222.384 172.716 222.408 172.8 ;
    END
  END w_b[50]
  PIN w_b[51]
    DIRECTION OUTPUT ;
    USE SIGNAL ;
    PORT
      LAYER M5 ;
        RECT  222.48 172.716 222.504 172.8 ;
    END
  END w_b[51]
  PIN w_b[52]
    DIRECTION OUTPUT ;
    USE SIGNAL ;
    PORT
      LAYER M5 ;
        RECT  222.576 172.716 222.6 172.8 ;
    END
  END w_b[52]
  PIN w_b[53]
    DIRECTION OUTPUT ;
    USE SIGNAL ;
    PORT
      LAYER M5 ;
        RECT  222.672 172.716 222.696 172.8 ;
    END
  END w_b[53]
  PIN w_b[54]
    DIRECTION OUTPUT ;
    USE SIGNAL ;
    PORT
      LAYER M5 ;
        RECT  222.768 172.716 222.792 172.8 ;
    END
  END w_b[54]
  PIN w_b[55]
    DIRECTION OUTPUT ;
    USE SIGNAL ;
    PORT
      LAYER M5 ;
        RECT  222.864 172.716 222.888 172.8 ;
    END
  END w_b[55]
  PIN w_b[56]
    DIRECTION OUTPUT ;
    USE SIGNAL ;
    PORT
      LAYER M5 ;
        RECT  222.96 172.716 222.984 172.8 ;
    END
  END w_b[56]
  PIN w_b[57]
    DIRECTION OUTPUT ;
    USE SIGNAL ;
    PORT
      LAYER M5 ;
        RECT  223.056 172.716 223.08 172.8 ;
    END
  END w_b[57]
  PIN w_b[58]
    DIRECTION OUTPUT ;
    USE SIGNAL ;
    PORT
      LAYER M5 ;
        RECT  223.152 172.716 223.176 172.8 ;
    END
  END w_b[58]
  PIN w_b[59]
    DIRECTION OUTPUT ;
    USE SIGNAL ;
    PORT
      LAYER M5 ;
        RECT  223.248 172.716 223.272 172.8 ;
    END
  END w_b[59]
  PIN w_b[5]
    DIRECTION OUTPUT ;
    USE SIGNAL ;
    PORT
      LAYER M5 ;
        RECT  211.632 172.716 211.656 172.8 ;
    END
  END w_b[5]
  PIN w_b[60]
    DIRECTION OUTPUT ;
    USE SIGNAL ;
    PORT
      LAYER M5 ;
        RECT  223.344 172.716 223.368 172.8 ;
    END
  END w_b[60]
  PIN w_b[61]
    DIRECTION OUTPUT ;
    USE SIGNAL ;
    PORT
      LAYER M5 ;
        RECT  223.44 172.716 223.464 172.8 ;
    END
  END w_b[61]
  PIN w_b[62]
    DIRECTION OUTPUT ;
    USE SIGNAL ;
    PORT
      LAYER M5 ;
        RECT  226.608 172.716 226.632 172.8 ;
    END
  END w_b[62]
  PIN w_b[63]
    DIRECTION OUTPUT ;
    USE SIGNAL ;
    PORT
      LAYER M5 ;
        RECT  226.704 172.716 226.728 172.8 ;
    END
  END w_b[63]
  PIN w_b[64]
    DIRECTION OUTPUT ;
    USE SIGNAL ;
    PORT
      LAYER M5 ;
        RECT  226.8 172.716 226.824 172.8 ;
    END
  END w_b[64]
  PIN w_b[65]
    DIRECTION OUTPUT ;
    USE SIGNAL ;
    PORT
      LAYER M5 ;
        RECT  226.896 172.716 226.92 172.8 ;
    END
  END w_b[65]
  PIN w_b[66]
    DIRECTION OUTPUT ;
    USE SIGNAL ;
    PORT
      LAYER M5 ;
        RECT  226.992 172.716 227.016 172.8 ;
    END
  END w_b[66]
  PIN w_b[67]
    DIRECTION OUTPUT ;
    USE SIGNAL ;
    PORT
      LAYER M5 ;
        RECT  227.088 172.716 227.112 172.8 ;
    END
  END w_b[67]
  PIN w_b[68]
    DIRECTION OUTPUT ;
    USE SIGNAL ;
    PORT
      LAYER M5 ;
        RECT  227.184 172.716 227.208 172.8 ;
    END
  END w_b[68]
  PIN w_b[69]
    DIRECTION OUTPUT ;
    USE SIGNAL ;
    PORT
      LAYER M5 ;
        RECT  227.28 172.716 227.304 172.8 ;
    END
  END w_b[69]
  PIN w_b[6]
    DIRECTION OUTPUT ;
    USE SIGNAL ;
    PORT
      LAYER M5 ;
        RECT  211.728 172.716 211.752 172.8 ;
    END
  END w_b[6]
  PIN w_b[70]
    DIRECTION OUTPUT ;
    USE SIGNAL ;
    PORT
      LAYER M5 ;
        RECT  227.376 172.716 227.4 172.8 ;
    END
  END w_b[70]
  PIN w_b[71]
    DIRECTION OUTPUT ;
    USE SIGNAL ;
    PORT
      LAYER M5 ;
        RECT  227.472 172.716 227.496 172.8 ;
    END
  END w_b[71]
  PIN w_b[72]
    DIRECTION OUTPUT ;
    USE SIGNAL ;
    PORT
      LAYER M5 ;
        RECT  227.568 172.716 227.592 172.8 ;
    END
  END w_b[72]
  PIN w_b[73]
    DIRECTION OUTPUT ;
    USE SIGNAL ;
    PORT
      LAYER M5 ;
        RECT  227.664 172.716 227.688 172.8 ;
    END
  END w_b[73]
  PIN w_b[74]
    DIRECTION OUTPUT ;
    USE SIGNAL ;
    PORT
      LAYER M5 ;
        RECT  227.76 172.716 227.784 172.8 ;
    END
  END w_b[74]
  PIN w_b[75]
    DIRECTION OUTPUT ;
    USE SIGNAL ;
    PORT
      LAYER M5 ;
        RECT  227.856 172.716 227.88 172.8 ;
    END
  END w_b[75]
  PIN w_b[76]
    DIRECTION OUTPUT ;
    USE SIGNAL ;
    PORT
      LAYER M5 ;
        RECT  227.952 172.716 227.976 172.8 ;
    END
  END w_b[76]
  PIN w_b[77]
    DIRECTION OUTPUT ;
    USE SIGNAL ;
    PORT
      LAYER M5 ;
        RECT  228.048 172.716 228.072 172.8 ;
    END
  END w_b[77]
  PIN w_b[78]
    DIRECTION OUTPUT ;
    USE SIGNAL ;
    PORT
      LAYER M5 ;
        RECT  228.144 172.716 228.168 172.8 ;
    END
  END w_b[78]
  PIN w_b[79]
    DIRECTION OUTPUT ;
    USE SIGNAL ;
    PORT
      LAYER M5 ;
        RECT  228.24 172.716 228.264 172.8 ;
    END
  END w_b[79]
  PIN w_b[7]
    DIRECTION OUTPUT ;
    USE SIGNAL ;
    PORT
      LAYER M5 ;
        RECT  211.824 172.716 211.848 172.8 ;
    END
  END w_b[7]
  PIN w_b[80]
    DIRECTION OUTPUT ;
    USE SIGNAL ;
    PORT
      LAYER M5 ;
        RECT  228.336 172.716 228.36 172.8 ;
    END
  END w_b[80]
  PIN w_b[81]
    DIRECTION OUTPUT ;
    USE SIGNAL ;
    PORT
      LAYER M5 ;
        RECT  228.432 172.716 228.456 172.8 ;
    END
  END w_b[81]
  PIN w_b[82]
    DIRECTION OUTPUT ;
    USE SIGNAL ;
    PORT
      LAYER M5 ;
        RECT  228.528 172.716 228.552 172.8 ;
    END
  END w_b[82]
  PIN w_b[83]
    DIRECTION OUTPUT ;
    USE SIGNAL ;
    PORT
      LAYER M5 ;
        RECT  228.624 172.716 228.648 172.8 ;
    END
  END w_b[83]
  PIN w_b[84]
    DIRECTION OUTPUT ;
    USE SIGNAL ;
    PORT
      LAYER M5 ;
        RECT  228.72 172.716 228.744 172.8 ;
    END
  END w_b[84]
  PIN w_b[85]
    DIRECTION OUTPUT ;
    USE SIGNAL ;
    PORT
      LAYER M5 ;
        RECT  228.816 172.716 228.84 172.8 ;
    END
  END w_b[85]
  PIN w_b[86]
    DIRECTION OUTPUT ;
    USE SIGNAL ;
    PORT
      LAYER M5 ;
        RECT  228.912 172.716 228.936 172.8 ;
    END
  END w_b[86]
  PIN w_b[87]
    DIRECTION OUTPUT ;
    USE SIGNAL ;
    PORT
      LAYER M5 ;
        RECT  229.008 172.716 229.032 172.8 ;
    END
  END w_b[87]
  PIN w_b[88]
    DIRECTION OUTPUT ;
    USE SIGNAL ;
    PORT
      LAYER M5 ;
        RECT  229.104 172.716 229.128 172.8 ;
    END
  END w_b[88]
  PIN w_b[89]
    DIRECTION OUTPUT ;
    USE SIGNAL ;
    PORT
      LAYER M5 ;
        RECT  229.2 172.716 229.224 172.8 ;
    END
  END w_b[89]
  PIN w_b[8]
    DIRECTION OUTPUT ;
    USE SIGNAL ;
    PORT
      LAYER M5 ;
        RECT  211.92 172.716 211.944 172.8 ;
    END
  END w_b[8]
  PIN w_b[90]
    DIRECTION OUTPUT ;
    USE SIGNAL ;
    PORT
      LAYER M5 ;
        RECT  229.296 172.716 229.32 172.8 ;
    END
  END w_b[90]
  PIN w_b[91]
    DIRECTION OUTPUT ;
    USE SIGNAL ;
    PORT
      LAYER M5 ;
        RECT  229.392 172.716 229.416 172.8 ;
    END
  END w_b[91]
  PIN w_b[92]
    DIRECTION OUTPUT ;
    USE SIGNAL ;
    PORT
      LAYER M5 ;
        RECT  229.488 172.716 229.512 172.8 ;
    END
  END w_b[92]
  PIN w_b[93]
    DIRECTION OUTPUT ;
    USE SIGNAL ;
    PORT
      LAYER M5 ;
        RECT  229.584 172.716 229.608 172.8 ;
    END
  END w_b[93]
  PIN w_b[94]
    DIRECTION OUTPUT ;
    USE SIGNAL ;
    PORT
      LAYER M5 ;
        RECT  217.392 172.716 217.416 172.8 ;
    END
  END w_b[94]
  PIN w_b[95]
    DIRECTION OUTPUT ;
    USE SIGNAL ;
    PORT
      LAYER M5 ;
        RECT  217.488 172.716 217.512 172.8 ;
    END
  END w_b[95]
  PIN w_b[96]
    DIRECTION OUTPUT ;
    USE SIGNAL ;
    PORT
      LAYER M5 ;
        RECT  217.584 172.716 217.608 172.8 ;
    END
  END w_b[96]
  PIN w_b[97]
    DIRECTION OUTPUT ;
    USE SIGNAL ;
    PORT
      LAYER M5 ;
        RECT  217.68 172.716 217.704 172.8 ;
    END
  END w_b[97]
  PIN w_b[98]
    DIRECTION OUTPUT ;
    USE SIGNAL ;
    PORT
      LAYER M5 ;
        RECT  217.776 172.716 217.8 172.8 ;
    END
  END w_b[98]
  PIN w_b[99]
    DIRECTION OUTPUT ;
    USE SIGNAL ;
    PORT
      LAYER M5 ;
        RECT  217.872 172.716 217.896 172.8 ;
    END
  END w_b[99]
  PIN w_b[9]
    DIRECTION OUTPUT ;
    USE SIGNAL ;
    PORT
      LAYER M5 ;
        RECT  212.016 172.716 212.04 172.8 ;
    END
  END w_b[9]
  PIN w_v
    DIRECTION OUTPUT ;
    USE SIGNAL ;
    PORT
      LAYER M5 ;
        RECT  191.952 172.716 191.976 172.8 ;
    END
  END w_v
  PIN VDD
    DIRECTION INOUT ;
    USE POWER ;
    PORT
      LAYER M5 ;
        RECT  339.156 4.311 339.276 168.489 ;
        RECT  334.836 4.311 334.956 168.489 ;
        RECT  330.516 4.311 330.636 168.489 ;
        RECT  326.196 4.311 326.316 168.489 ;
        RECT  321.876 4.311 321.996 168.489 ;
        RECT  317.556 4.311 317.676 168.489 ;
        RECT  313.236 4.311 313.356 168.489 ;
        RECT  308.916 4.311 309.036 168.489 ;
        RECT  304.596 4.311 304.716 168.489 ;
        RECT  300.276 4.311 300.396 168.489 ;
        RECT  295.956 4.311 296.076 168.489 ;
        RECT  291.636 4.311 291.756 168.489 ;
        RECT  287.316 4.311 287.436 168.489 ;
        RECT  282.996 4.311 283.116 168.489 ;
        RECT  278.676 4.311 278.796 168.489 ;
        RECT  274.356 4.311 274.476 168.489 ;
        RECT  270.036 4.311 270.156 168.489 ;
        RECT  265.716 4.311 265.836 168.489 ;
        RECT  261.396 4.311 261.516 168.489 ;
        RECT  257.076 4.311 257.196 168.489 ;
        RECT  252.756 4.311 252.876 168.489 ;
        RECT  248.436 4.311 248.556 168.489 ;
        RECT  244.116 4.311 244.236 168.489 ;
        RECT  239.796 4.311 239.916 168.489 ;
        RECT  235.476 4.311 235.596 168.489 ;
        RECT  231.156 4.311 231.276 168.489 ;
        RECT  226.836 4.311 226.956 168.489 ;
        RECT  222.516 4.311 222.636 168.489 ;
        RECT  218.196 4.311 218.316 168.489 ;
        RECT  213.876 4.311 213.996 168.489 ;
        RECT  209.556 4.311 209.676 168.489 ;
        RECT  205.236 4.311 205.356 168.489 ;
        RECT  200.916 4.311 201.036 168.489 ;
        RECT  196.596 4.311 196.716 168.489 ;
        RECT  192.276 4.311 192.396 168.489 ;
        RECT  187.956 4.311 188.076 168.489 ;
        RECT  183.636 4.311 183.756 168.489 ;
        RECT  179.316 4.311 179.436 168.489 ;
        RECT  174.996 4.311 175.116 168.489 ;
        RECT  170.676 4.311 170.796 168.489 ;
        RECT  166.356 4.311 166.476 168.489 ;
        RECT  162.036 4.311 162.156 168.489 ;
        RECT  157.716 4.311 157.836 168.489 ;
        RECT  153.396 4.311 153.516 168.489 ;
        RECT  149.076 4.311 149.196 168.489 ;
        RECT  144.756 4.311 144.876 168.489 ;
        RECT  140.436 4.311 140.556 168.489 ;
        RECT  136.116 4.311 136.236 168.489 ;
        RECT  131.796 4.311 131.916 168.489 ;
        RECT  127.476 4.311 127.596 168.489 ;
        RECT  123.156 4.311 123.276 168.489 ;
        RECT  118.836 4.311 118.956 168.489 ;
        RECT  114.516 4.311 114.636 168.489 ;
        RECT  110.196 4.311 110.316 168.489 ;
        RECT  105.876 4.311 105.996 168.489 ;
        RECT  101.556 4.311 101.676 168.489 ;
        RECT  97.236 4.311 97.356 168.489 ;
        RECT  92.916 4.311 93.036 168.489 ;
        RECT  88.596 4.311 88.716 168.489 ;
        RECT  84.276 4.311 84.396 168.489 ;
        RECT  79.956 4.311 80.076 168.489 ;
        RECT  75.636 4.311 75.756 168.489 ;
        RECT  71.316 4.311 71.436 168.489 ;
        RECT  66.996 4.311 67.116 168.489 ;
        RECT  62.676 4.311 62.796 168.489 ;
        RECT  58.356 4.311 58.476 168.489 ;
        RECT  54.036 4.311 54.156 168.489 ;
        RECT  49.716 4.311 49.836 168.489 ;
        RECT  45.396 4.311 45.516 168.489 ;
        RECT  41.076 4.311 41.196 168.489 ;
        RECT  36.756 4.311 36.876 168.489 ;
        RECT  32.436 4.311 32.556 168.489 ;
        RECT  28.116 4.311 28.236 168.489 ;
        RECT  23.796 4.311 23.916 168.489 ;
        RECT  19.476 4.311 19.596 168.489 ;
        RECT  15.156 4.311 15.276 168.489 ;
        RECT  10.836 4.311 10.956 168.489 ;
        RECT  6.516 4.311 6.636 168.489 ;
    END
  END VDD
  PIN VSS
    DIRECTION INOUT ;
    USE GROUND ;
    PORT
      LAYER M5 ;
        RECT  338.964 4.297 339.084 168.503 ;
        RECT  334.644 4.297 334.764 168.503 ;
        RECT  330.324 4.297 330.444 168.503 ;
        RECT  326.004 4.297 326.124 168.503 ;
        RECT  321.684 4.297 321.804 168.503 ;
        RECT  317.364 4.297 317.484 168.503 ;
        RECT  313.044 4.297 313.164 168.503 ;
        RECT  308.724 4.297 308.844 168.503 ;
        RECT  304.404 4.297 304.524 168.503 ;
        RECT  300.084 4.297 300.204 168.503 ;
        RECT  295.764 4.297 295.884 168.503 ;
        RECT  291.444 4.297 291.564 168.503 ;
        RECT  287.124 4.297 287.244 168.503 ;
        RECT  282.804 4.297 282.924 168.503 ;
        RECT  278.484 4.297 278.604 168.503 ;
        RECT  274.164 4.297 274.284 168.503 ;
        RECT  269.844 4.297 269.964 168.503 ;
        RECT  265.524 4.297 265.644 168.503 ;
        RECT  261.204 4.297 261.324 168.503 ;
        RECT  256.884 4.297 257.004 168.503 ;
        RECT  252.564 4.297 252.684 168.503 ;
        RECT  248.244 4.297 248.364 168.503 ;
        RECT  243.924 4.297 244.044 168.503 ;
        RECT  239.604 4.297 239.724 168.503 ;
        RECT  235.284 4.297 235.404 168.503 ;
        RECT  230.964 4.297 231.084 168.503 ;
        RECT  226.644 4.297 226.764 168.503 ;
        RECT  222.324 4.297 222.444 168.503 ;
        RECT  218.004 4.297 218.124 168.503 ;
        RECT  213.684 4.297 213.804 168.503 ;
        RECT  209.364 4.297 209.484 168.503 ;
        RECT  205.044 4.297 205.164 168.503 ;
        RECT  200.724 4.297 200.844 168.503 ;
        RECT  196.404 4.297 196.524 168.503 ;
        RECT  192.084 4.297 192.204 168.503 ;
        RECT  187.764 4.297 187.884 168.503 ;
        RECT  183.444 4.297 183.564 168.503 ;
        RECT  179.124 4.297 179.244 168.503 ;
        RECT  174.804 4.297 174.924 168.503 ;
        RECT  170.484 4.297 170.604 168.503 ;
        RECT  166.164 4.297 166.284 168.503 ;
        RECT  161.844 4.297 161.964 168.503 ;
        RECT  157.524 4.297 157.644 168.503 ;
        RECT  153.204 4.297 153.324 168.503 ;
        RECT  148.884 4.297 149.004 168.503 ;
        RECT  144.564 4.297 144.684 168.503 ;
        RECT  140.244 4.297 140.364 168.503 ;
        RECT  135.924 4.297 136.044 168.503 ;
        RECT  131.604 4.297 131.724 168.503 ;
        RECT  127.284 4.297 127.404 168.503 ;
        RECT  122.964 4.297 123.084 168.503 ;
        RECT  118.644 4.297 118.764 168.503 ;
        RECT  114.324 4.297 114.444 168.503 ;
        RECT  110.004 4.297 110.124 168.503 ;
        RECT  105.684 4.297 105.804 168.503 ;
        RECT  101.364 4.297 101.484 168.503 ;
        RECT  97.044 4.297 97.164 168.503 ;
        RECT  92.724 4.297 92.844 168.503 ;
        RECT  88.404 4.297 88.524 168.503 ;
        RECT  84.084 4.297 84.204 168.503 ;
        RECT  79.764 4.297 79.884 168.503 ;
        RECT  75.444 4.297 75.564 168.503 ;
        RECT  71.124 4.297 71.244 168.503 ;
        RECT  66.804 4.297 66.924 168.503 ;
        RECT  62.484 4.297 62.604 168.503 ;
        RECT  58.164 4.297 58.284 168.503 ;
        RECT  53.844 4.297 53.964 168.503 ;
        RECT  49.524 4.297 49.644 168.503 ;
        RECT  45.204 4.297 45.324 168.503 ;
        RECT  40.884 4.297 41.004 168.503 ;
        RECT  36.564 4.297 36.684 168.503 ;
        RECT  32.244 4.297 32.364 168.503 ;
        RECT  27.924 4.297 28.044 168.503 ;
        RECT  23.604 4.297 23.724 168.503 ;
        RECT  19.284 4.297 19.404 168.503 ;
        RECT  14.964 4.297 15.084 168.503 ;
        RECT  10.644 4.297 10.764 168.503 ;
        RECT  6.324 4.297 6.444 168.503 ;
    END
  END VSS
  OBS
    LAYER RVTN ;
     RECT  0.229 0 345.6 172.8 ;
    LAYER RVTP ;
     RECT  0.229 0 345.6 172.8 ;
    LAYER M1 ;
     RECT  0.229 0 345.6 172.8 ;
    LAYER M2 ;
     RECT  0.229 0 345.6 172.8 ;
    LAYER M3 ;
     RECT  0.229 0 345.6 172.8 ;
    LAYER M4 ;
     RECT  0.229 0 345.6 172.8 ;
    LAYER M5 ;
     RECT  0.229 0 345.6 172.8 ;
  END
END dsdv_gunit_l3
END LIBRARY
